VERSION 5.4 ;
NAMESCASESENSITIVE ON ;
BUSBITCHARS "[]" ;
DIVIDERCHAR "/" ;
UNITS
  DATABASE MICRONS 2000 ;
END UNITS
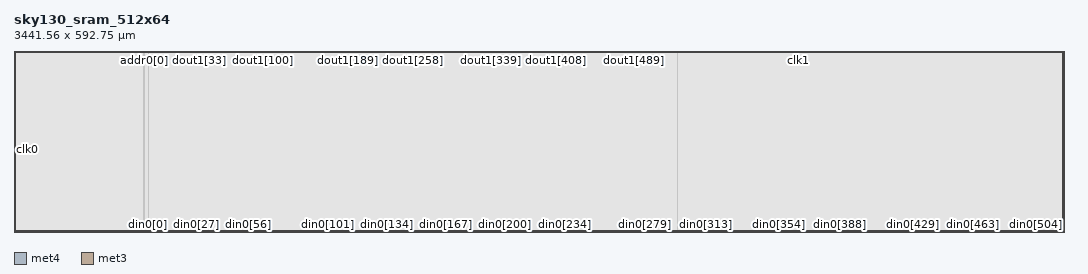
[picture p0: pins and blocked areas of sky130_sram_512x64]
MACRO sky130_sram_512x64
   CLASS BLOCK ;
   SIZE 3441.56 BY 592.75 ;
   SYMMETRY X Y R90 ;
   PIN din0[0]
      DIRECTION INPUT ;
      PORT
         LAYER met4 ;
         RECT  439.9 0.0 440.28 0.38 ;
      END
   END din0[0]
   PIN din0[1]
      DIRECTION INPUT ;
      PORT
         LAYER met4 ;
         RECT  445.74 0.0 446.12 0.38 ;
      END
   END din0[1]
   PIN din0[2]
      DIRECTION INPUT ;
      PORT
         LAYER met4 ;
         RECT  451.58 0.0 451.96 0.38 ;
      END
   END din0[2]
   PIN din0[3]
      DIRECTION INPUT ;
      PORT
         LAYER met4 ;
         RECT  457.42 0.0 457.8 0.38 ;
      END
   END din0[3]
   PIN din0[4]
      DIRECTION INPUT ;
      PORT
         LAYER met4 ;
         RECT  463.26 0.0 463.64 0.38 ;
      END
   END din0[4]
   PIN din0[5]
      DIRECTION INPUT ;
      PORT
         LAYER met4 ;
         RECT  469.1 0.0 469.48 0.38 ;
      END
   END din0[5]
   PIN din0[6]
      DIRECTION INPUT ;
      PORT
         LAYER met4 ;
         RECT  474.94 0.0 475.32 0.38 ;
      END
   END din0[6]
   PIN din0[7]
      DIRECTION INPUT ;
      PORT
         LAYER met4 ;
         RECT  480.78 0.0 481.16 0.38 ;
      END
   END din0[7]
   PIN din0[8]
      DIRECTION INPUT ;
      PORT
         LAYER met4 ;
         RECT  486.62 0.0 487.0 0.38 ;
      END
   END din0[8]
   PIN din0[9]
      DIRECTION INPUT ;
      PORT
         LAYER met4 ;
         RECT  492.46 0.0 492.84 0.38 ;
      END
   END din0[9]
   PIN din0[10]
      DIRECTION INPUT ;
      PORT
         LAYER met4 ;
         RECT  498.3 0.0 498.68 0.38 ;
      END
   END din0[10]
   PIN din0[11]
      DIRECTION INPUT ;
      PORT
         LAYER met4 ;
         RECT  504.14 0.0 504.52 0.38 ;
      END
   END din0[11]
   PIN din0[12]
      DIRECTION INPUT ;
      PORT
         LAYER met4 ;
         RECT  509.98 0.0 510.36 0.38 ;
      END
   END din0[12]
   PIN din0[13]
      DIRECTION INPUT ;
      PORT
         LAYER met4 ;
         RECT  515.82 0.0 516.2 0.38 ;
      END
   END din0[13]
   PIN din0[14]
      DIRECTION INPUT ;
      PORT
         LAYER met4 ;
         RECT  521.66 0.0 522.04 0.38 ;
      END
   END din0[14]
   PIN din0[15]
      DIRECTION INPUT ;
      PORT
         LAYER met4 ;
         RECT  527.5 0.0 527.88 0.38 ;
      END
   END din0[15]
   PIN din0[16]
      DIRECTION INPUT ;
      PORT
         LAYER met4 ;
         RECT  533.34 0.0 533.72 0.38 ;
      END
   END din0[16]
   PIN din0[17]
      DIRECTION INPUT ;
      PORT
         LAYER met4 ;
         RECT  539.18 0.0 539.56 0.38 ;
      END
   END din0[17]
   PIN din0[18]
      DIRECTION INPUT ;
      PORT
         LAYER met4 ;
         RECT  545.02 0.0 545.4 0.38 ;
      END
   END din0[18]
   PIN din0[19]
      DIRECTION INPUT ;
      PORT
         LAYER met4 ;
         RECT  550.86 0.0 551.24 0.38 ;
      END
   END din0[19]
   PIN din0[20]
      DIRECTION INPUT ;
      PORT
         LAYER met4 ;
         RECT  556.7 0.0 557.08 0.38 ;
      END
   END din0[20]
   PIN din0[21]
      DIRECTION INPUT ;
      PORT
         LAYER met4 ;
         RECT  562.54 0.0 562.92 0.38 ;
      END
   END din0[21]
   PIN din0[22]
      DIRECTION INPUT ;
      PORT
         LAYER met4 ;
         RECT  568.38 0.0 568.76 0.38 ;
      END
   END din0[22]
   PIN din0[23]
      DIRECTION INPUT ;
      PORT
         LAYER met4 ;
         RECT  574.22 0.0 574.6 0.38 ;
      END
   END din0[23]
   PIN din0[24]
      DIRECTION INPUT ;
      PORT
         LAYER met4 ;
         RECT  580.06 0.0 580.44 0.38 ;
      END
   END din0[24]
   PIN din0[25]
      DIRECTION INPUT ;
      PORT
         LAYER met4 ;
         RECT  585.9 0.0 586.28 0.38 ;
      END
   END din0[25]
   PIN din0[26]
      DIRECTION INPUT ;
      PORT
         LAYER met4 ;
         RECT  591.74 0.0 592.12 0.38 ;
      END
   END din0[26]
   PIN din0[27]
      DIRECTION INPUT ;
      PORT
         LAYER met4 ;
         RECT  597.58 0.0 597.96 0.38 ;
      END
   END din0[27]
   PIN din0[28]
      DIRECTION INPUT ;
      PORT
         LAYER met4 ;
         RECT  603.42 0.0 603.8 0.38 ;
      END
   END din0[28]
   PIN din0[29]
      DIRECTION INPUT ;
      PORT
         LAYER met4 ;
         RECT  609.26 0.0 609.64 0.38 ;
      END
   END din0[29]
   PIN din0[30]
      DIRECTION INPUT ;
      PORT
         LAYER met4 ;
         RECT  615.1 0.0 615.48 0.38 ;
      END
   END din0[30]
   PIN din0[31]
      DIRECTION INPUT ;
      PORT
         LAYER met4 ;
         RECT  620.94 0.0 621.32 0.38 ;
      END
   END din0[31]
   PIN din0[32]
      DIRECTION INPUT ;
      PORT
         LAYER met4 ;
         RECT  626.78 0.0 627.16 0.38 ;
      END
   END din0[32]
   PIN din0[33]
      DIRECTION INPUT ;
      PORT
         LAYER met4 ;
         RECT  632.62 0.0 633.0 0.38 ;
      END
   END din0[33]
   PIN din0[34]
      DIRECTION INPUT ;
      PORT
         LAYER met4 ;
         RECT  638.46 0.0 638.84 0.38 ;
      END
   END din0[34]
   PIN din0[35]
      DIRECTION INPUT ;
      PORT
         LAYER met4 ;
         RECT  644.3 0.0 644.68 0.38 ;
      END
   END din0[35]
   PIN din0[36]
      DIRECTION INPUT ;
      PORT
         LAYER met4 ;
         RECT  650.14 0.0 650.52 0.38 ;
      END
   END din0[36]
   PIN din0[37]
      DIRECTION INPUT ;
      PORT
         LAYER met4 ;
         RECT  655.98 0.0 656.36 0.38 ;
      END
   END din0[37]
   PIN din0[38]
      DIRECTION INPUT ;
      PORT
         LAYER met4 ;
         RECT  661.82 0.0 662.2 0.38 ;
      END
   END din0[38]
   PIN din0[39]
      DIRECTION INPUT ;
      PORT
         LAYER met4 ;
         RECT  667.66 0.0 668.04 0.38 ;
      END
   END din0[39]
   PIN din0[40]
      DIRECTION INPUT ;
      PORT
         LAYER met4 ;
         RECT  673.5 0.0 673.88 0.38 ;
      END
   END din0[40]
   PIN din0[41]
      DIRECTION INPUT ;
      PORT
         LAYER met4 ;
         RECT  679.34 0.0 679.72 0.38 ;
      END
   END din0[41]
   PIN din0[42]
      DIRECTION INPUT ;
      PORT
         LAYER met4 ;
         RECT  685.18 0.0 685.56 0.38 ;
      END
   END din0[42]
   PIN din0[43]
      DIRECTION INPUT ;
      PORT
         LAYER met4 ;
         RECT  691.02 0.0 691.4 0.38 ;
      END
   END din0[43]
   PIN din0[44]
      DIRECTION INPUT ;
      PORT
         LAYER met4 ;
         RECT  696.86 0.0 697.24 0.38 ;
      END
   END din0[44]
   PIN din0[45]
      DIRECTION INPUT ;
      PORT
         LAYER met4 ;
         RECT  702.7 0.0 703.08 0.38 ;
      END
   END din0[45]
   PIN din0[46]
      DIRECTION INPUT ;
      PORT
         LAYER met4 ;
         RECT  708.54 0.0 708.92 0.38 ;
      END
   END din0[46]
   PIN din0[47]
      DIRECTION INPUT ;
      PORT
         LAYER met4 ;
         RECT  714.38 0.0 714.76 0.38 ;
      END
   END din0[47]
   PIN din0[48]
      DIRECTION INPUT ;
      PORT
         LAYER met4 ;
         RECT  720.22 0.0 720.6 0.38 ;
      END
   END din0[48]
   PIN din0[49]
      DIRECTION INPUT ;
      PORT
         LAYER met4 ;
         RECT  726.06 0.0 726.44 0.38 ;
      END
   END din0[49]
   PIN din0[50]
      DIRECTION INPUT ;
      PORT
         LAYER met4 ;
         RECT  731.9 0.0 732.28 0.38 ;
      END
   END din0[50]
   PIN din0[51]
      DIRECTION INPUT ;
      PORT
         LAYER met4 ;
         RECT  737.74 0.0 738.12 0.38 ;
      END
   END din0[51]
   PIN din0[52]
      DIRECTION INPUT ;
      PORT
         LAYER met4 ;
         RECT  743.58 0.0 743.96 0.38 ;
      END
   END din0[52]
   PIN din0[53]
      DIRECTION INPUT ;
      PORT
         LAYER met4 ;
         RECT  749.42 0.0 749.8 0.38 ;
      END
   END din0[53]
   PIN din0[54]
      DIRECTION INPUT ;
      PORT
         LAYER met4 ;
         RECT  755.26 0.0 755.64 0.38 ;
      END
   END din0[54]
   PIN din0[55]
      DIRECTION INPUT ;
      PORT
         LAYER met4 ;
         RECT  761.1 0.0 761.48 0.38 ;
      END
   END din0[55]
   PIN din0[56]
      DIRECTION INPUT ;
      PORT
         LAYER met4 ;
         RECT  766.94 0.0 767.32 0.38 ;
      END
   END din0[56]
   PIN din0[57]
      DIRECTION INPUT ;
      PORT
         LAYER met4 ;
         RECT  772.78 0.0 773.16 0.38 ;
      END
   END din0[57]
   PIN din0[58]
      DIRECTION INPUT ;
      PORT
         LAYER met4 ;
         RECT  778.62 0.0 779.0 0.38 ;
      END
   END din0[58]
   PIN din0[59]
      DIRECTION INPUT ;
      PORT
         LAYER met4 ;
         RECT  784.46 0.0 784.84 0.38 ;
      END
   END din0[59]
   PIN din0[60]
      DIRECTION INPUT ;
      PORT
         LAYER met4 ;
         RECT  790.3 0.0 790.68 0.38 ;
      END
   END din0[60]
   PIN din0[61]
      DIRECTION INPUT ;
      PORT
         LAYER met4 ;
         RECT  796.14 0.0 796.52 0.38 ;
      END
   END din0[61]
   PIN din0[62]
      DIRECTION INPUT ;
      PORT
         LAYER met4 ;
         RECT  801.98 0.0 802.36 0.38 ;
      END
   END din0[62]
   PIN din0[63]
      DIRECTION INPUT ;
      PORT
         LAYER met4 ;
         RECT  807.82 0.0 808.2 0.38 ;
      END
   END din0[63]
   PIN din0[64]
      DIRECTION INPUT ;
      PORT
         LAYER met4 ;
         RECT  813.66 0.0 814.04 0.38 ;
      END
   END din0[64]
   PIN din0[65]
      DIRECTION INPUT ;
      PORT
         LAYER met4 ;
         RECT  819.5 0.0 819.88 0.38 ;
      END
   END din0[65]
   PIN din0[66]
      DIRECTION INPUT ;
      PORT
         LAYER met4 ;
         RECT  825.34 0.0 825.72 0.38 ;
      END
   END din0[66]
   PIN din0[67]
      DIRECTION INPUT ;
      PORT
         LAYER met4 ;
         RECT  831.18 0.0 831.56 0.38 ;
      END
   END din0[67]
   PIN din0[68]
      DIRECTION INPUT ;
      PORT
         LAYER met4 ;
         RECT  837.02 0.0 837.4 0.38 ;
      END
   END din0[68]
   PIN din0[69]
      DIRECTION INPUT ;
      PORT
         LAYER met4 ;
         RECT  842.86 0.0 843.24 0.38 ;
      END
   END din0[69]
   PIN din0[70]
      DIRECTION INPUT ;
      PORT
         LAYER met4 ;
         RECT  848.7 0.0 849.08 0.38 ;
      END
   END din0[70]
   PIN din0[71]
      DIRECTION INPUT ;
      PORT
         LAYER met4 ;
         RECT  854.54 0.0 854.92 0.38 ;
      END
   END din0[71]
   PIN din0[72]
      DIRECTION INPUT ;
      PORT
         LAYER met4 ;
         RECT  860.38 0.0 860.76 0.38 ;
      END
   END din0[72]
   PIN din0[73]
      DIRECTION INPUT ;
      PORT
         LAYER met4 ;
         RECT  866.22 0.0 866.6 0.38 ;
      END
   END din0[73]
   PIN din0[74]
      DIRECTION INPUT ;
      PORT
         LAYER met4 ;
         RECT  872.06 0.0 872.44 0.38 ;
      END
   END din0[74]
   PIN din0[75]
      DIRECTION INPUT ;
      PORT
         LAYER met4 ;
         RECT  877.9 0.0 878.28 0.38 ;
      END
   END din0[75]
   PIN din0[76]
      DIRECTION INPUT ;
      PORT
         LAYER met4 ;
         RECT  883.74 0.0 884.12 0.38 ;
      END
   END din0[76]
   PIN din0[77]
      DIRECTION INPUT ;
      PORT
         LAYER met4 ;
         RECT  889.58 0.0 889.96 0.38 ;
      END
   END din0[77]
   PIN din0[78]
      DIRECTION INPUT ;
      PORT
         LAYER met4 ;
         RECT  895.42 0.0 895.8 0.38 ;
      END
   END din0[78]
   PIN din0[79]
      DIRECTION INPUT ;
      PORT
         LAYER met4 ;
         RECT  901.26 0.0 901.64 0.38 ;
      END
   END din0[79]
   PIN din0[80]
      DIRECTION INPUT ;
      PORT
         LAYER met4 ;
         RECT  907.1 0.0 907.48 0.38 ;
      END
   END din0[80]
   PIN din0[81]
      DIRECTION INPUT ;
      PORT
         LAYER met4 ;
         RECT  912.94 0.0 913.32 0.38 ;
      END
   END din0[81]
   PIN din0[82]
      DIRECTION INPUT ;
      PORT
         LAYER met4 ;
         RECT  918.78 0.0 919.16 0.38 ;
      END
   END din0[82]
   PIN din0[83]
      DIRECTION INPUT ;
      PORT
         LAYER met4 ;
         RECT  924.62 0.0 925.0 0.38 ;
      END
   END din0[83]
   PIN din0[84]
      DIRECTION INPUT ;
      PORT
         LAYER met4 ;
         RECT  930.46 0.0 930.84 0.38 ;
      END
   END din0[84]
   PIN din0[85]
      DIRECTION INPUT ;
      PORT
         LAYER met4 ;
         RECT  936.3 0.0 936.68 0.38 ;
      END
   END din0[85]
   PIN din0[86]
      DIRECTION INPUT ;
      PORT
         LAYER met4 ;
         RECT  942.14 0.0 942.52 0.38 ;
      END
   END din0[86]
   PIN din0[87]
      DIRECTION INPUT ;
      PORT
         LAYER met4 ;
         RECT  947.98 0.0 948.36 0.38 ;
      END
   END din0[87]
   PIN din0[88]
      DIRECTION INPUT ;
      PORT
         LAYER met4 ;
         RECT  953.82 0.0 954.2 0.38 ;
      END
   END din0[88]
   PIN din0[89]
      DIRECTION INPUT ;
      PORT
         LAYER met4 ;
         RECT  959.66 0.0 960.04 0.38 ;
      END
   END din0[89]
   PIN din0[90]
      DIRECTION INPUT ;
      PORT
         LAYER met4 ;
         RECT  965.5 0.0 965.88 0.38 ;
      END
   END din0[90]
   PIN din0[91]
      DIRECTION INPUT ;
      PORT
         LAYER met4 ;
         RECT  971.34 0.0 971.72 0.38 ;
      END
   END din0[91]
   PIN din0[92]
      DIRECTION INPUT ;
      PORT
         LAYER met4 ;
         RECT  977.18 0.0 977.56 0.38 ;
      END
   END din0[92]
   PIN din0[93]
      DIRECTION INPUT ;
      PORT
         LAYER met4 ;
         RECT  983.02 0.0 983.4 0.38 ;
      END
   END din0[93]
   PIN din0[94]
      DIRECTION INPUT ;
      PORT
         LAYER met4 ;
         RECT  988.86 0.0 989.24 0.38 ;
      END
   END din0[94]
   PIN din0[95]
      DIRECTION INPUT ;
      PORT
         LAYER met4 ;
         RECT  994.7 0.0 995.08 0.38 ;
      END
   END din0[95]
   PIN din0[96]
      DIRECTION INPUT ;
      PORT
         LAYER met4 ;
         RECT  1000.54 0.0 1000.92 0.38 ;
      END
   END din0[96]
   PIN din0[97]
      DIRECTION INPUT ;
      PORT
         LAYER met4 ;
         RECT  1006.38 0.0 1006.76 0.38 ;
      END
   END din0[97]
   PIN din0[98]
      DIRECTION INPUT ;
      PORT
         LAYER met4 ;
         RECT  1012.22 0.0 1012.6 0.38 ;
      END
   END din0[98]
   PIN din0[99]
      DIRECTION INPUT ;
      PORT
         LAYER met4 ;
         RECT  1018.06 0.0 1018.44 0.38 ;
      END
   END din0[99]
   PIN din0[100]
      DIRECTION INPUT ;
      PORT
         LAYER met4 ;
         RECT  1023.9 0.0 1024.28 0.38 ;
      END
   END din0[100]
   PIN din0[101]
      DIRECTION INPUT ;
      PORT
         LAYER met4 ;
         RECT  1029.74 0.0 1030.12 0.38 ;
      END
   END din0[101]
   PIN din0[102]
      DIRECTION INPUT ;
      PORT
         LAYER met4 ;
         RECT  1035.58 0.0 1035.96 0.38 ;
      END
   END din0[102]
   PIN din0[103]
      DIRECTION INPUT ;
      PORT
         LAYER met4 ;
         RECT  1041.42 0.0 1041.8 0.38 ;
      END
   END din0[103]
   PIN din0[104]
      DIRECTION INPUT ;
      PORT
         LAYER met4 ;
         RECT  1047.26 0.0 1047.64 0.38 ;
      END
   END din0[104]
   PIN din0[105]
      DIRECTION INPUT ;
      PORT
         LAYER met4 ;
         RECT  1053.1 0.0 1053.48 0.38 ;
      END
   END din0[105]
   PIN din0[106]
      DIRECTION INPUT ;
      PORT
         LAYER met4 ;
         RECT  1058.94 0.0 1059.32 0.38 ;
      END
   END din0[106]
   PIN din0[107]
      DIRECTION INPUT ;
      PORT
         LAYER met4 ;
         RECT  1064.78 0.0 1065.16 0.38 ;
      END
   END din0[107]
   PIN din0[108]
      DIRECTION INPUT ;
      PORT
         LAYER met4 ;
         RECT  1070.62 0.0 1071.0 0.38 ;
      END
   END din0[108]
   PIN din0[109]
      DIRECTION INPUT ;
      PORT
         LAYER met4 ;
         RECT  1076.46 0.0 1076.84 0.38 ;
      END
   END din0[109]
   PIN din0[110]
      DIRECTION INPUT ;
      PORT
         LAYER met4 ;
         RECT  1082.3 0.0 1082.68 0.38 ;
      END
   END din0[110]
   PIN din0[111]
      DIRECTION INPUT ;
      PORT
         LAYER met4 ;
         RECT  1088.14 0.0 1088.52 0.38 ;
      END
   END din0[111]
   PIN din0[112]
      DIRECTION INPUT ;
      PORT
         LAYER met4 ;
         RECT  1093.98 0.0 1094.36 0.38 ;
      END
   END din0[112]
   PIN din0[113]
      DIRECTION INPUT ;
      PORT
         LAYER met4 ;
         RECT  1099.82 0.0 1100.2 0.38 ;
      END
   END din0[113]
   PIN din0[114]
      DIRECTION INPUT ;
      PORT
         LAYER met4 ;
         RECT  1105.66 0.0 1106.04 0.38 ;
      END
   END din0[114]
   PIN din0[115]
      DIRECTION INPUT ;
      PORT
         LAYER met4 ;
         RECT  1111.5 0.0 1111.88 0.38 ;
      END
   END din0[115]
   PIN din0[116]
      DIRECTION INPUT ;
      PORT
         LAYER met4 ;
         RECT  1117.34 0.0 1117.72 0.38 ;
      END
   END din0[116]
   PIN din0[117]
      DIRECTION INPUT ;
      PORT
         LAYER met4 ;
         RECT  1123.18 0.0 1123.56 0.38 ;
      END
   END din0[117]
   PIN din0[118]
      DIRECTION INPUT ;
      PORT
         LAYER met4 ;
         RECT  1129.02 0.0 1129.4 0.38 ;
      END
   END din0[118]
   PIN din0[119]
      DIRECTION INPUT ;
      PORT
         LAYER met4 ;
         RECT  1134.86 0.0 1135.24 0.38 ;
      END
   END din0[119]
   PIN din0[120]
      DIRECTION INPUT ;
      PORT
         LAYER met4 ;
         RECT  1140.7 0.0 1141.08 0.38 ;
      END
   END din0[120]
   PIN din0[121]
      DIRECTION INPUT ;
      PORT
         LAYER met4 ;
         RECT  1146.54 0.0 1146.92 0.38 ;
      END
   END din0[121]
   PIN din0[122]
      DIRECTION INPUT ;
      PORT
         LAYER met4 ;
         RECT  1152.38 0.0 1152.76 0.38 ;
      END
   END din0[122]
   PIN din0[123]
      DIRECTION INPUT ;
      PORT
         LAYER met4 ;
         RECT  1158.22 0.0 1158.6 0.38 ;
      END
   END din0[123]
   PIN din0[124]
      DIRECTION INPUT ;
      PORT
         LAYER met4 ;
         RECT  1164.06 0.0 1164.44 0.38 ;
      END
   END din0[124]
   PIN din0[125]
      DIRECTION INPUT ;
      PORT
         LAYER met4 ;
         RECT  1169.9 0.0 1170.28 0.38 ;
      END
   END din0[125]
   PIN din0[126]
      DIRECTION INPUT ;
      PORT
         LAYER met4 ;
         RECT  1175.74 0.0 1176.12 0.38 ;
      END
   END din0[126]
   PIN din0[127]
      DIRECTION INPUT ;
      PORT
         LAYER met4 ;
         RECT  1181.58 0.0 1181.96 0.38 ;
      END
   END din0[127]
   PIN din0[128]
      DIRECTION INPUT ;
      PORT
         LAYER met4 ;
         RECT  1187.42 0.0 1187.8 0.38 ;
      END
   END din0[128]
   PIN din0[129]
      DIRECTION INPUT ;
      PORT
         LAYER met4 ;
         RECT  1193.26 0.0 1193.64 0.38 ;
      END
   END din0[129]
   PIN din0[130]
      DIRECTION INPUT ;
      PORT
         LAYER met4 ;
         RECT  1199.1 0.0 1199.48 0.38 ;
      END
   END din0[130]
   PIN din0[131]
      DIRECTION INPUT ;
      PORT
         LAYER met4 ;
         RECT  1204.94 0.0 1205.32 0.38 ;
      END
   END din0[131]
   PIN din0[132]
      DIRECTION INPUT ;
      PORT
         LAYER met4 ;
         RECT  1210.78 0.0 1211.16 0.38 ;
      END
   END din0[132]
   PIN din0[133]
      DIRECTION INPUT ;
      PORT
         LAYER met4 ;
         RECT  1216.62 0.0 1217.0 0.38 ;
      END
   END din0[133]
   PIN din0[134]
      DIRECTION INPUT ;
      PORT
         LAYER met4 ;
         RECT  1222.46 0.0 1222.84 0.38 ;
      END
   END din0[134]
   PIN din0[135]
      DIRECTION INPUT ;
      PORT
         LAYER met4 ;
         RECT  1228.3 0.0 1228.68 0.38 ;
      END
   END din0[135]
   PIN din0[136]
      DIRECTION INPUT ;
      PORT
         LAYER met4 ;
         RECT  1234.14 0.0 1234.52 0.38 ;
      END
   END din0[136]
   PIN din0[137]
      DIRECTION INPUT ;
      PORT
         LAYER met4 ;
         RECT  1239.98 0.0 1240.36 0.38 ;
      END
   END din0[137]
   PIN din0[138]
      DIRECTION INPUT ;
      PORT
         LAYER met4 ;
         RECT  1245.82 0.0 1246.2 0.38 ;
      END
   END din0[138]
   PIN din0[139]
      DIRECTION INPUT ;
      PORT
         LAYER met4 ;
         RECT  1251.66 0.0 1252.04 0.38 ;
      END
   END din0[139]
   PIN din0[140]
      DIRECTION INPUT ;
      PORT
         LAYER met4 ;
         RECT  1257.5 0.0 1257.88 0.38 ;
      END
   END din0[140]
   PIN din0[141]
      DIRECTION INPUT ;
      PORT
         LAYER met4 ;
         RECT  1263.34 0.0 1263.72 0.38 ;
      END
   END din0[141]
   PIN din0[142]
      DIRECTION INPUT ;
      PORT
         LAYER met4 ;
         RECT  1269.18 0.0 1269.56 0.38 ;
      END
   END din0[142]
   PIN din0[143]
      DIRECTION INPUT ;
      PORT
         LAYER met4 ;
         RECT  1275.02 0.0 1275.4 0.38 ;
      END
   END din0[143]
   PIN din0[144]
      DIRECTION INPUT ;
      PORT
         LAYER met4 ;
         RECT  1280.86 0.0 1281.24 0.38 ;
      END
   END din0[144]
   PIN din0[145]
      DIRECTION INPUT ;
      PORT
         LAYER met4 ;
         RECT  1286.7 0.0 1287.08 0.38 ;
      END
   END din0[145]
   PIN din0[146]
      DIRECTION INPUT ;
      PORT
         LAYER met4 ;
         RECT  1292.54 0.0 1292.92 0.38 ;
      END
   END din0[146]
   PIN din0[147]
      DIRECTION INPUT ;
      PORT
         LAYER met4 ;
         RECT  1298.38 0.0 1298.76 0.38 ;
      END
   END din0[147]
   PIN din0[148]
      DIRECTION INPUT ;
      PORT
         LAYER met4 ;
         RECT  1304.22 0.0 1304.6 0.38 ;
      END
   END din0[148]
   PIN din0[149]
      DIRECTION INPUT ;
      PORT
         LAYER met4 ;
         RECT  1310.06 0.0 1310.44 0.38 ;
      END
   END din0[149]
   PIN din0[150]
      DIRECTION INPUT ;
      PORT
         LAYER met4 ;
         RECT  1315.9 0.0 1316.28 0.38 ;
      END
   END din0[150]
   PIN din0[151]
      DIRECTION INPUT ;
      PORT
         LAYER met4 ;
         RECT  1321.74 0.0 1322.12 0.38 ;
      END
   END din0[151]
   PIN din0[152]
      DIRECTION INPUT ;
      PORT
         LAYER met4 ;
         RECT  1327.58 0.0 1327.96 0.38 ;
      END
   END din0[152]
   PIN din0[153]
      DIRECTION INPUT ;
      PORT
         LAYER met4 ;
         RECT  1333.42 0.0 1333.8 0.38 ;
      END
   END din0[153]
   PIN din0[154]
      DIRECTION INPUT ;
      PORT
         LAYER met4 ;
         RECT  1339.26 0.0 1339.64 0.38 ;
      END
   END din0[154]
   PIN din0[155]
      DIRECTION INPUT ;
      PORT
         LAYER met4 ;
         RECT  1345.1 0.0 1345.48 0.38 ;
      END
   END din0[155]
   PIN din0[156]
      DIRECTION INPUT ;
      PORT
         LAYER met4 ;
         RECT  1350.94 0.0 1351.32 0.38 ;
      END
   END din0[156]
   PIN din0[157]
      DIRECTION INPUT ;
      PORT
         LAYER met4 ;
         RECT  1356.78 0.0 1357.16 0.38 ;
      END
   END din0[157]
   PIN din0[158]
      DIRECTION INPUT ;
      PORT
         LAYER met4 ;
         RECT  1362.62 0.0 1363.0 0.38 ;
      END
   END din0[158]
   PIN din0[159]
      DIRECTION INPUT ;
      PORT
         LAYER met4 ;
         RECT  1368.46 0.0 1368.84 0.38 ;
      END
   END din0[159]
   PIN din0[160]
      DIRECTION INPUT ;
      PORT
         LAYER met4 ;
         RECT  1374.3 0.0 1374.68 0.38 ;
      END
   END din0[160]
   PIN din0[161]
      DIRECTION INPUT ;
      PORT
         LAYER met4 ;
         RECT  1380.14 0.0 1380.52 0.38 ;
      END
   END din0[161]
   PIN din0[162]
      DIRECTION INPUT ;
      PORT
         LAYER met4 ;
         RECT  1385.98 0.0 1386.36 0.38 ;
      END
   END din0[162]
   PIN din0[163]
      DIRECTION INPUT ;
      PORT
         LAYER met4 ;
         RECT  1391.82 0.0 1392.2 0.38 ;
      END
   END din0[163]
   PIN din0[164]
      DIRECTION INPUT ;
      PORT
         LAYER met4 ;
         RECT  1397.66 0.0 1398.04 0.38 ;
      END
   END din0[164]
   PIN din0[165]
      DIRECTION INPUT ;
      PORT
         LAYER met4 ;
         RECT  1403.5 0.0 1403.88 0.38 ;
      END
   END din0[165]
   PIN din0[166]
      DIRECTION INPUT ;
      PORT
         LAYER met4 ;
         RECT  1409.34 0.0 1409.72 0.38 ;
      END
   END din0[166]
   PIN din0[167]
      DIRECTION INPUT ;
      PORT
         LAYER met4 ;
         RECT  1415.18 0.0 1415.56 0.38 ;
      END
   END din0[167]
   PIN din0[168]
      DIRECTION INPUT ;
      PORT
         LAYER met4 ;
         RECT  1421.02 0.0 1421.4 0.38 ;
      END
   END din0[168]
   PIN din0[169]
      DIRECTION INPUT ;
      PORT
         LAYER met4 ;
         RECT  1426.86 0.0 1427.24 0.38 ;
      END
   END din0[169]
   PIN din0[170]
      DIRECTION INPUT ;
      PORT
         LAYER met4 ;
         RECT  1432.7 0.0 1433.08 0.38 ;
      END
   END din0[170]
   PIN din0[171]
      DIRECTION INPUT ;
      PORT
         LAYER met4 ;
         RECT  1438.54 0.0 1438.92 0.38 ;
      END
   END din0[171]
   PIN din0[172]
      DIRECTION INPUT ;
      PORT
         LAYER met4 ;
         RECT  1444.38 0.0 1444.76 0.38 ;
      END
   END din0[172]
   PIN din0[173]
      DIRECTION INPUT ;
      PORT
         LAYER met4 ;
         RECT  1450.22 0.0 1450.6 0.38 ;
      END
   END din0[173]
   PIN din0[174]
      DIRECTION INPUT ;
      PORT
         LAYER met4 ;
         RECT  1456.06 0.0 1456.44 0.38 ;
      END
   END din0[174]
   PIN din0[175]
      DIRECTION INPUT ;
      PORT
         LAYER met4 ;
         RECT  1461.9 0.0 1462.28 0.38 ;
      END
   END din0[175]
   PIN din0[176]
      DIRECTION INPUT ;
      PORT
         LAYER met4 ;
         RECT  1467.74 0.0 1468.12 0.38 ;
      END
   END din0[176]
   PIN din0[177]
      DIRECTION INPUT ;
      PORT
         LAYER met4 ;
         RECT  1473.58 0.0 1473.96 0.38 ;
      END
   END din0[177]
   PIN din0[178]
      DIRECTION INPUT ;
      PORT
         LAYER met4 ;
         RECT  1479.42 0.0 1479.8 0.38 ;
      END
   END din0[178]
   PIN din0[179]
      DIRECTION INPUT ;
      PORT
         LAYER met4 ;
         RECT  1485.26 0.0 1485.64 0.38 ;
      END
   END din0[179]
   PIN din0[180]
      DIRECTION INPUT ;
      PORT
         LAYER met4 ;
         RECT  1491.1 0.0 1491.48 0.38 ;
      END
   END din0[180]
   PIN din0[181]
      DIRECTION INPUT ;
      PORT
         LAYER met4 ;
         RECT  1496.94 0.0 1497.32 0.38 ;
      END
   END din0[181]
   PIN din0[182]
      DIRECTION INPUT ;
      PORT
         LAYER met4 ;
         RECT  1502.78 0.0 1503.16 0.38 ;
      END
   END din0[182]
   PIN din0[183]
      DIRECTION INPUT ;
      PORT
         LAYER met4 ;
         RECT  1508.62 0.0 1509.0 0.38 ;
      END
   END din0[183]
   PIN din0[184]
      DIRECTION INPUT ;
      PORT
         LAYER met4 ;
         RECT  1514.46 0.0 1514.84 0.38 ;
      END
   END din0[184]
   PIN din0[185]
      DIRECTION INPUT ;
      PORT
         LAYER met4 ;
         RECT  1520.3 0.0 1520.68 0.38 ;
      END
   END din0[185]
   PIN din0[186]
      DIRECTION INPUT ;
      PORT
         LAYER met4 ;
         RECT  1526.14 0.0 1526.52 0.38 ;
      END
   END din0[186]
   PIN din0[187]
      DIRECTION INPUT ;
      PORT
         LAYER met4 ;
         RECT  1531.98 0.0 1532.36 0.38 ;
      END
   END din0[187]
   PIN din0[188]
      DIRECTION INPUT ;
      PORT
         LAYER met4 ;
         RECT  1537.82 0.0 1538.2 0.38 ;
      END
   END din0[188]
   PIN din0[189]
      DIRECTION INPUT ;
      PORT
         LAYER met4 ;
         RECT  1543.66 0.0 1544.04 0.38 ;
      END
   END din0[189]
   PIN din0[190]
      DIRECTION INPUT ;
      PORT
         LAYER met4 ;
         RECT  1549.5 0.0 1549.88 0.38 ;
      END
   END din0[190]
   PIN din0[191]
      DIRECTION INPUT ;
      PORT
         LAYER met4 ;
         RECT  1555.34 0.0 1555.72 0.38 ;
      END
   END din0[191]
   PIN din0[192]
      DIRECTION INPUT ;
      PORT
         LAYER met4 ;
         RECT  1561.18 0.0 1561.56 0.38 ;
      END
   END din0[192]
   PIN din0[193]
      DIRECTION INPUT ;
      PORT
         LAYER met4 ;
         RECT  1567.02 0.0 1567.4 0.38 ;
      END
   END din0[193]
   PIN din0[194]
      DIRECTION INPUT ;
      PORT
         LAYER met4 ;
         RECT  1572.86 0.0 1573.24 0.38 ;
      END
   END din0[194]
   PIN din0[195]
      DIRECTION INPUT ;
      PORT
         LAYER met4 ;
         RECT  1578.7 0.0 1579.08 0.38 ;
      END
   END din0[195]
   PIN din0[196]
      DIRECTION INPUT ;
      PORT
         LAYER met4 ;
         RECT  1584.54 0.0 1584.92 0.38 ;
      END
   END din0[196]
   PIN din0[197]
      DIRECTION INPUT ;
      PORT
         LAYER met4 ;
         RECT  1590.38 0.0 1590.76 0.38 ;
      END
   END din0[197]
   PIN din0[198]
      DIRECTION INPUT ;
      PORT
         LAYER met4 ;
         RECT  1596.22 0.0 1596.6 0.38 ;
      END
   END din0[198]
   PIN din0[199]
      DIRECTION INPUT ;
      PORT
         LAYER met4 ;
         RECT  1602.06 0.0 1602.44 0.38 ;
      END
   END din0[199]
   PIN din0[200]
      DIRECTION INPUT ;
      PORT
         LAYER met4 ;
         RECT  1607.9 0.0 1608.28 0.38 ;
      END
   END din0[200]
   PIN din0[201]
      DIRECTION INPUT ;
      PORT
         LAYER met4 ;
         RECT  1613.74 0.0 1614.12 0.38 ;
      END
   END din0[201]
   PIN din0[202]
      DIRECTION INPUT ;
      PORT
         LAYER met4 ;
         RECT  1619.58 0.0 1619.96 0.38 ;
      END
   END din0[202]
   PIN din0[203]
      DIRECTION INPUT ;
      PORT
         LAYER met4 ;
         RECT  1625.42 0.0 1625.8 0.38 ;
      END
   END din0[203]
   PIN din0[204]
      DIRECTION INPUT ;
      PORT
         LAYER met4 ;
         RECT  1631.26 0.0 1631.64 0.38 ;
      END
   END din0[204]
   PIN din0[205]
      DIRECTION INPUT ;
      PORT
         LAYER met4 ;
         RECT  1637.1 0.0 1637.48 0.38 ;
      END
   END din0[205]
   PIN din0[206]
      DIRECTION INPUT ;
      PORT
         LAYER met4 ;
         RECT  1642.94 0.0 1643.32 0.38 ;
      END
   END din0[206]
   PIN din0[207]
      DIRECTION INPUT ;
      PORT
         LAYER met4 ;
         RECT  1648.78 0.0 1649.16 0.38 ;
      END
   END din0[207]
   PIN din0[208]
      DIRECTION INPUT ;
      PORT
         LAYER met4 ;
         RECT  1654.62 0.0 1655.0 0.38 ;
      END
   END din0[208]
   PIN din0[209]
      DIRECTION INPUT ;
      PORT
         LAYER met4 ;
         RECT  1660.46 0.0 1660.84 0.38 ;
      END
   END din0[209]
   PIN din0[210]
      DIRECTION INPUT ;
      PORT
         LAYER met4 ;
         RECT  1666.3 0.0 1666.68 0.38 ;
      END
   END din0[210]
   PIN din0[211]
      DIRECTION INPUT ;
      PORT
         LAYER met4 ;
         RECT  1672.14 0.0 1672.52 0.38 ;
      END
   END din0[211]
   PIN din0[212]
      DIRECTION INPUT ;
      PORT
         LAYER met4 ;
         RECT  1677.98 0.0 1678.36 0.38 ;
      END
   END din0[212]
   PIN din0[213]
      DIRECTION INPUT ;
      PORT
         LAYER met4 ;
         RECT  1683.82 0.0 1684.2 0.38 ;
      END
   END din0[213]
   PIN din0[214]
      DIRECTION INPUT ;
      PORT
         LAYER met4 ;
         RECT  1689.66 0.0 1690.04 0.38 ;
      END
   END din0[214]
   PIN din0[215]
      DIRECTION INPUT ;
      PORT
         LAYER met4 ;
         RECT  1695.5 0.0 1695.88 0.38 ;
      END
   END din0[215]
   PIN din0[216]
      DIRECTION INPUT ;
      PORT
         LAYER met4 ;
         RECT  1701.34 0.0 1701.72 0.38 ;
      END
   END din0[216]
   PIN din0[217]
      DIRECTION INPUT ;
      PORT
         LAYER met4 ;
         RECT  1707.18 0.0 1707.56 0.38 ;
      END
   END din0[217]
   PIN din0[218]
      DIRECTION INPUT ;
      PORT
         LAYER met4 ;
         RECT  1713.02 0.0 1713.4 0.38 ;
      END
   END din0[218]
   PIN din0[219]
      DIRECTION INPUT ;
      PORT
         LAYER met4 ;
         RECT  1718.86 0.0 1719.24 0.38 ;
      END
   END din0[219]
   PIN din0[220]
      DIRECTION INPUT ;
      PORT
         LAYER met4 ;
         RECT  1724.7 0.0 1725.08 0.38 ;
      END
   END din0[220]
   PIN din0[221]
      DIRECTION INPUT ;
      PORT
         LAYER met4 ;
         RECT  1730.54 0.0 1730.92 0.38 ;
      END
   END din0[221]
   PIN din0[222]
      DIRECTION INPUT ;
      PORT
         LAYER met4 ;
         RECT  1736.38 0.0 1736.76 0.38 ;
      END
   END din0[222]
   PIN din0[223]
      DIRECTION INPUT ;
      PORT
         LAYER met4 ;
         RECT  1742.22 0.0 1742.6 0.38 ;
      END
   END din0[223]
   PIN din0[224]
      DIRECTION INPUT ;
      PORT
         LAYER met4 ;
         RECT  1748.06 0.0 1748.44 0.38 ;
      END
   END din0[224]
   PIN din0[225]
      DIRECTION INPUT ;
      PORT
         LAYER met4 ;
         RECT  1753.9 0.0 1754.28 0.38 ;
      END
   END din0[225]
   PIN din0[226]
      DIRECTION INPUT ;
      PORT
         LAYER met4 ;
         RECT  1759.74 0.0 1760.12 0.38 ;
      END
   END din0[226]
   PIN din0[227]
      DIRECTION INPUT ;
      PORT
         LAYER met4 ;
         RECT  1765.58 0.0 1765.96 0.38 ;
      END
   END din0[227]
   PIN din0[228]
      DIRECTION INPUT ;
      PORT
         LAYER met4 ;
         RECT  1771.42 0.0 1771.8 0.38 ;
      END
   END din0[228]
   PIN din0[229]
      DIRECTION INPUT ;
      PORT
         LAYER met4 ;
         RECT  1777.26 0.0 1777.64 0.38 ;
      END
   END din0[229]
   PIN din0[230]
      DIRECTION INPUT ;
      PORT
         LAYER met4 ;
         RECT  1783.1 0.0 1783.48 0.38 ;
      END
   END din0[230]
   PIN din0[231]
      DIRECTION INPUT ;
      PORT
         LAYER met4 ;
         RECT  1788.94 0.0 1789.32 0.38 ;
      END
   END din0[231]
   PIN din0[232]
      DIRECTION INPUT ;
      PORT
         LAYER met4 ;
         RECT  1794.78 0.0 1795.16 0.38 ;
      END
   END din0[232]
   PIN din0[233]
      DIRECTION INPUT ;
      PORT
         LAYER met4 ;
         RECT  1800.62 0.0 1801.0 0.38 ;
      END
   END din0[233]
   PIN din0[234]
      DIRECTION INPUT ;
      PORT
         LAYER met4 ;
         RECT  1806.46 0.0 1806.84 0.38 ;
      END
   END din0[234]
   PIN din0[235]
      DIRECTION INPUT ;
      PORT
         LAYER met4 ;
         RECT  1812.3 0.0 1812.68 0.38 ;
      END
   END din0[235]
   PIN din0[236]
      DIRECTION INPUT ;
      PORT
         LAYER met4 ;
         RECT  1818.14 0.0 1818.52 0.38 ;
      END
   END din0[236]
   PIN din0[237]
      DIRECTION INPUT ;
      PORT
         LAYER met4 ;
         RECT  1823.98 0.0 1824.36 0.38 ;
      END
   END din0[237]
   PIN din0[238]
      DIRECTION INPUT ;
      PORT
         LAYER met4 ;
         RECT  1829.82 0.0 1830.2 0.38 ;
      END
   END din0[238]
   PIN din0[239]
      DIRECTION INPUT ;
      PORT
         LAYER met4 ;
         RECT  1835.66 0.0 1836.04 0.38 ;
      END
   END din0[239]
   PIN din0[240]
      DIRECTION INPUT ;
      PORT
         LAYER met4 ;
         RECT  1841.5 0.0 1841.88 0.38 ;
      END
   END din0[240]
   PIN din0[241]
      DIRECTION INPUT ;
      PORT
         LAYER met4 ;
         RECT  1847.34 0.0 1847.72 0.38 ;
      END
   END din0[241]
   PIN din0[242]
      DIRECTION INPUT ;
      PORT
         LAYER met4 ;
         RECT  1853.18 0.0 1853.56 0.38 ;
      END
   END din0[242]
   PIN din0[243]
      DIRECTION INPUT ;
      PORT
         LAYER met4 ;
         RECT  1859.02 0.0 1859.4 0.38 ;
      END
   END din0[243]
   PIN din0[244]
      DIRECTION INPUT ;
      PORT
         LAYER met4 ;
         RECT  1864.86 0.0 1865.24 0.38 ;
      END
   END din0[244]
   PIN din0[245]
      DIRECTION INPUT ;
      PORT
         LAYER met4 ;
         RECT  1870.7 0.0 1871.08 0.38 ;
      END
   END din0[245]
   PIN din0[246]
      DIRECTION INPUT ;
      PORT
         LAYER met4 ;
         RECT  1876.54 0.0 1876.92 0.38 ;
      END
   END din0[246]
   PIN din0[247]
      DIRECTION INPUT ;
      PORT
         LAYER met4 ;
         RECT  1882.38 0.0 1882.76 0.38 ;
      END
   END din0[247]
   PIN din0[248]
      DIRECTION INPUT ;
      PORT
         LAYER met4 ;
         RECT  1888.22 0.0 1888.6 0.38 ;
      END
   END din0[248]
   PIN din0[249]
      DIRECTION INPUT ;
      PORT
         LAYER met4 ;
         RECT  1894.06 0.0 1894.44 0.38 ;
      END
   END din0[249]
   PIN din0[250]
      DIRECTION INPUT ;
      PORT
         LAYER met4 ;
         RECT  1899.9 0.0 1900.28 0.38 ;
      END
   END din0[250]
   PIN din0[251]
      DIRECTION INPUT ;
      PORT
         LAYER met4 ;
         RECT  1905.74 0.0 1906.12 0.38 ;
      END
   END din0[251]
   PIN din0[252]
      DIRECTION INPUT ;
      PORT
         LAYER met4 ;
         RECT  1911.58 0.0 1911.96 0.38 ;
      END
   END din0[252]
   PIN din0[253]
      DIRECTION INPUT ;
      PORT
         LAYER met4 ;
         RECT  1917.42 0.0 1917.8 0.38 ;
      END
   END din0[253]
   PIN din0[254]
      DIRECTION INPUT ;
      PORT
         LAYER met4 ;
         RECT  1923.26 0.0 1923.64 0.38 ;
      END
   END din0[254]
   PIN din0[255]
      DIRECTION INPUT ;
      PORT
         LAYER met4 ;
         RECT  1929.1 0.0 1929.48 0.38 ;
      END
   END din0[255]
   PIN din0[256]
      DIRECTION INPUT ;
      PORT
         LAYER met4 ;
         RECT  1934.94 0.0 1935.32 0.38 ;
      END
   END din0[256]
   PIN din0[257]
      DIRECTION INPUT ;
      PORT
         LAYER met4 ;
         RECT  1940.78 0.0 1941.16 0.38 ;
      END
   END din0[257]
   PIN din0[258]
      DIRECTION INPUT ;
      PORT
         LAYER met4 ;
         RECT  1946.62 0.0 1947.0 0.38 ;
      END
   END din0[258]
   PIN din0[259]
      DIRECTION INPUT ;
      PORT
         LAYER met4 ;
         RECT  1952.46 0.0 1952.84 0.38 ;
      END
   END din0[259]
   PIN din0[260]
      DIRECTION INPUT ;
      PORT
         LAYER met4 ;
         RECT  1958.3 0.0 1958.68 0.38 ;
      END
   END din0[260]
   PIN din0[261]
      DIRECTION INPUT ;
      PORT
         LAYER met4 ;
         RECT  1964.14 0.0 1964.52 0.38 ;
      END
   END din0[261]
   PIN din0[262]
      DIRECTION INPUT ;
      PORT
         LAYER met4 ;
         RECT  1969.98 0.0 1970.36 0.38 ;
      END
   END din0[262]
   PIN din0[263]
      DIRECTION INPUT ;
      PORT
         LAYER met4 ;
         RECT  1975.82 0.0 1976.2 0.38 ;
      END
   END din0[263]
   PIN din0[264]
      DIRECTION INPUT ;
      PORT
         LAYER met4 ;
         RECT  1981.66 0.0 1982.04 0.38 ;
      END
   END din0[264]
   PIN din0[265]
      DIRECTION INPUT ;
      PORT
         LAYER met4 ;
         RECT  1987.5 0.0 1987.88 0.38 ;
      END
   END din0[265]
   PIN din0[266]
      DIRECTION INPUT ;
      PORT
         LAYER met4 ;
         RECT  1993.34 0.0 1993.72 0.38 ;
      END
   END din0[266]
   PIN din0[267]
      DIRECTION INPUT ;
      PORT
         LAYER met4 ;
         RECT  1999.18 0.0 1999.56 0.38 ;
      END
   END din0[267]
   PIN din0[268]
      DIRECTION INPUT ;
      PORT
         LAYER met4 ;
         RECT  2005.02 0.0 2005.4 0.38 ;
      END
   END din0[268]
   PIN din0[269]
      DIRECTION INPUT ;
      PORT
         LAYER met4 ;
         RECT  2010.86 0.0 2011.24 0.38 ;
      END
   END din0[269]
   PIN din0[270]
      DIRECTION INPUT ;
      PORT
         LAYER met4 ;
         RECT  2016.7 0.0 2017.08 0.38 ;
      END
   END din0[270]
   PIN din0[271]
      DIRECTION INPUT ;
      PORT
         LAYER met4 ;
         RECT  2022.54 0.0 2022.92 0.38 ;
      END
   END din0[271]
   PIN din0[272]
      DIRECTION INPUT ;
      PORT
         LAYER met4 ;
         RECT  2028.38 0.0 2028.76 0.38 ;
      END
   END din0[272]
   PIN din0[273]
      DIRECTION INPUT ;
      PORT
         LAYER met4 ;
         RECT  2034.22 0.0 2034.6 0.38 ;
      END
   END din0[273]
   PIN din0[274]
      DIRECTION INPUT ;
      PORT
         LAYER met4 ;
         RECT  2040.06 0.0 2040.44 0.38 ;
      END
   END din0[274]
   PIN din0[275]
      DIRECTION INPUT ;
      PORT
         LAYER met4 ;
         RECT  2045.9 0.0 2046.28 0.38 ;
      END
   END din0[275]
   PIN din0[276]
      DIRECTION INPUT ;
      PORT
         LAYER met4 ;
         RECT  2051.74 0.0 2052.12 0.38 ;
      END
   END din0[276]
   PIN din0[277]
      DIRECTION INPUT ;
      PORT
         LAYER met4 ;
         RECT  2057.58 0.0 2057.96 0.38 ;
      END
   END din0[277]
   PIN din0[278]
      DIRECTION INPUT ;
      PORT
         LAYER met4 ;
         RECT  2063.42 0.0 2063.8 0.38 ;
      END
   END din0[278]
   PIN din0[279]
      DIRECTION INPUT ;
      PORT
         LAYER met4 ;
         RECT  2069.26 0.0 2069.64 0.38 ;
      END
   END din0[279]
   PIN din0[280]
      DIRECTION INPUT ;
      PORT
         LAYER met4 ;
         RECT  2075.1 0.0 2075.48 0.38 ;
      END
   END din0[280]
   PIN din0[281]
      DIRECTION INPUT ;
      PORT
         LAYER met4 ;
         RECT  2080.94 0.0 2081.32 0.38 ;
      END
   END din0[281]
   PIN din0[282]
      DIRECTION INPUT ;
      PORT
         LAYER met4 ;
         RECT  2086.78 0.0 2087.16 0.38 ;
      END
   END din0[282]
   PIN din0[283]
      DIRECTION INPUT ;
      PORT
         LAYER met4 ;
         RECT  2092.62 0.0 2093.0 0.38 ;
      END
   END din0[283]
   PIN din0[284]
      DIRECTION INPUT ;
      PORT
         LAYER met4 ;
         RECT  2098.46 0.0 2098.84 0.38 ;
      END
   END din0[284]
   PIN din0[285]
      DIRECTION INPUT ;
      PORT
         LAYER met4 ;
         RECT  2104.3 0.0 2104.68 0.38 ;
      END
   END din0[285]
   PIN din0[286]
      DIRECTION INPUT ;
      PORT
         LAYER met4 ;
         RECT  2110.14 0.0 2110.52 0.38 ;
      END
   END din0[286]
   PIN din0[287]
      DIRECTION INPUT ;
      PORT
         LAYER met4 ;
         RECT  2115.98 0.0 2116.36 0.38 ;
      END
   END din0[287]
   PIN din0[288]
      DIRECTION INPUT ;
      PORT
         LAYER met4 ;
         RECT  2121.82 0.0 2122.2 0.38 ;
      END
   END din0[288]
   PIN din0[289]
      DIRECTION INPUT ;
      PORT
         LAYER met4 ;
         RECT  2127.66 0.0 2128.04 0.38 ;
      END
   END din0[289]
   PIN din0[290]
      DIRECTION INPUT ;
      PORT
         LAYER met4 ;
         RECT  2133.5 0.0 2133.88 0.38 ;
      END
   END din0[290]
   PIN din0[291]
      DIRECTION INPUT ;
      PORT
         LAYER met4 ;
         RECT  2139.34 0.0 2139.72 0.38 ;
      END
   END din0[291]
   PIN din0[292]
      DIRECTION INPUT ;
      PORT
         LAYER met4 ;
         RECT  2145.18 0.0 2145.56 0.38 ;
      END
   END din0[292]
   PIN din0[293]
      DIRECTION INPUT ;
      PORT
         LAYER met4 ;
         RECT  2151.02 0.0 2151.4 0.38 ;
      END
   END din0[293]
   PIN din0[294]
      DIRECTION INPUT ;
      PORT
         LAYER met4 ;
         RECT  2156.86 0.0 2157.24 0.38 ;
      END
   END din0[294]
   PIN din0[295]
      DIRECTION INPUT ;
      PORT
         LAYER met4 ;
         RECT  2162.7 0.0 2163.08 0.38 ;
      END
   END din0[295]
   PIN din0[296]
      DIRECTION INPUT ;
      PORT
         LAYER met4 ;
         RECT  2168.54 0.0 2168.92 0.38 ;
      END
   END din0[296]
   PIN din0[297]
      DIRECTION INPUT ;
      PORT
         LAYER met4 ;
         RECT  2174.38 0.0 2174.76 0.38 ;
      END
   END din0[297]
   PIN din0[298]
      DIRECTION INPUT ;
      PORT
         LAYER met4 ;
         RECT  2180.22 0.0 2180.6 0.38 ;
      END
   END din0[298]
   PIN din0[299]
      DIRECTION INPUT ;
      PORT
         LAYER met4 ;
         RECT  2186.06 0.0 2186.44 0.38 ;
      END
   END din0[299]
   PIN din0[300]
      DIRECTION INPUT ;
      PORT
         LAYER met4 ;
         RECT  2191.9 0.0 2192.28 0.38 ;
      END
   END din0[300]
   PIN din0[301]
      DIRECTION INPUT ;
      PORT
         LAYER met4 ;
         RECT  2197.74 0.0 2198.12 0.38 ;
      END
   END din0[301]
   PIN din0[302]
      DIRECTION INPUT ;
      PORT
         LAYER met4 ;
         RECT  2203.58 0.0 2203.96 0.38 ;
      END
   END din0[302]
   PIN din0[303]
      DIRECTION INPUT ;
      PORT
         LAYER met4 ;
         RECT  2209.42 0.0 2209.8 0.38 ;
      END
   END din0[303]
   PIN din0[304]
      DIRECTION INPUT ;
      PORT
         LAYER met4 ;
         RECT  2215.26 0.0 2215.64 0.38 ;
      END
   END din0[304]
   PIN din0[305]
      DIRECTION INPUT ;
      PORT
         LAYER met4 ;
         RECT  2221.1 0.0 2221.48 0.38 ;
      END
   END din0[305]
   PIN din0[306]
      DIRECTION INPUT ;
      PORT
         LAYER met4 ;
         RECT  2226.94 0.0 2227.32 0.38 ;
      END
   END din0[306]
   PIN din0[307]
      DIRECTION INPUT ;
      PORT
         LAYER met4 ;
         RECT  2232.78 0.0 2233.16 0.38 ;
      END
   END din0[307]
   PIN din0[308]
      DIRECTION INPUT ;
      PORT
         LAYER met4 ;
         RECT  2238.62 0.0 2239.0 0.38 ;
      END
   END din0[308]
   PIN din0[309]
      DIRECTION INPUT ;
      PORT
         LAYER met4 ;
         RECT  2244.46 0.0 2244.84 0.38 ;
      END
   END din0[309]
   PIN din0[310]
      DIRECTION INPUT ;
      PORT
         LAYER met4 ;
         RECT  2250.3 0.0 2250.68 0.38 ;
      END
   END din0[310]
   PIN din0[311]
      DIRECTION INPUT ;
      PORT
         LAYER met4 ;
         RECT  2256.14 0.0 2256.52 0.38 ;
      END
   END din0[311]
   PIN din0[312]
      DIRECTION INPUT ;
      PORT
         LAYER met4 ;
         RECT  2261.98 0.0 2262.36 0.38 ;
      END
   END din0[312]
   PIN din0[313]
      DIRECTION INPUT ;
      PORT
         LAYER met4 ;
         RECT  2267.82 0.0 2268.2 0.38 ;
      END
   END din0[313]
   PIN din0[314]
      DIRECTION INPUT ;
      PORT
         LAYER met4 ;
         RECT  2273.66 0.0 2274.04 0.38 ;
      END
   END din0[314]
   PIN din0[315]
      DIRECTION INPUT ;
      PORT
         LAYER met4 ;
         RECT  2279.5 0.0 2279.88 0.38 ;
      END
   END din0[315]
   PIN din0[316]
      DIRECTION INPUT ;
      PORT
         LAYER met4 ;
         RECT  2285.34 0.0 2285.72 0.38 ;
      END
   END din0[316]
   PIN din0[317]
      DIRECTION INPUT ;
      PORT
         LAYER met4 ;
         RECT  2291.18 0.0 2291.56 0.38 ;
      END
   END din0[317]
   PIN din0[318]
      DIRECTION INPUT ;
      PORT
         LAYER met4 ;
         RECT  2297.02 0.0 2297.4 0.38 ;
      END
   END din0[318]
   PIN din0[319]
      DIRECTION INPUT ;
      PORT
         LAYER met4 ;
         RECT  2302.86 0.0 2303.24 0.38 ;
      END
   END din0[319]
   PIN din0[320]
      DIRECTION INPUT ;
      PORT
         LAYER met4 ;
         RECT  2308.7 0.0 2309.08 0.38 ;
      END
   END din0[320]
   PIN din0[321]
      DIRECTION INPUT ;
      PORT
         LAYER met4 ;
         RECT  2314.54 0.0 2314.92 0.38 ;
      END
   END din0[321]
   PIN din0[322]
      DIRECTION INPUT ;
      PORT
         LAYER met4 ;
         RECT  2320.38 0.0 2320.76 0.38 ;
      END
   END din0[322]
   PIN din0[323]
      DIRECTION INPUT ;
      PORT
         LAYER met4 ;
         RECT  2326.22 0.0 2326.6 0.38 ;
      END
   END din0[323]
   PIN din0[324]
      DIRECTION INPUT ;
      PORT
         LAYER met4 ;
         RECT  2332.06 0.0 2332.44 0.38 ;
      END
   END din0[324]
   PIN din0[325]
      DIRECTION INPUT ;
      PORT
         LAYER met4 ;
         RECT  2337.9 0.0 2338.28 0.38 ;
      END
   END din0[325]
   PIN din0[326]
      DIRECTION INPUT ;
      PORT
         LAYER met4 ;
         RECT  2343.74 0.0 2344.12 0.38 ;
      END
   END din0[326]
   PIN din0[327]
      DIRECTION INPUT ;
      PORT
         LAYER met4 ;
         RECT  2349.58 0.0 2349.96 0.38 ;
      END
   END din0[327]
   PIN din0[328]
      DIRECTION INPUT ;
      PORT
         LAYER met4 ;
         RECT  2355.42 0.0 2355.8 0.38 ;
      END
   END din0[328]
   PIN din0[329]
      DIRECTION INPUT ;
      PORT
         LAYER met4 ;
         RECT  2361.26 0.0 2361.64 0.38 ;
      END
   END din0[329]
   PIN din0[330]
      DIRECTION INPUT ;
      PORT
         LAYER met4 ;
         RECT  2367.1 0.0 2367.48 0.38 ;
      END
   END din0[330]
   PIN din0[331]
      DIRECTION INPUT ;
      PORT
         LAYER met4 ;
         RECT  2372.94 0.0 2373.32 0.38 ;
      END
   END din0[331]
   PIN din0[332]
      DIRECTION INPUT ;
      PORT
         LAYER met4 ;
         RECT  2378.78 0.0 2379.16 0.38 ;
      END
   END din0[332]
   PIN din0[333]
      DIRECTION INPUT ;
      PORT
         LAYER met4 ;
         RECT  2384.62 0.0 2385.0 0.38 ;
      END
   END din0[333]
   PIN din0[334]
      DIRECTION INPUT ;
      PORT
         LAYER met4 ;
         RECT  2390.46 0.0 2390.84 0.38 ;
      END
   END din0[334]
   PIN din0[335]
      DIRECTION INPUT ;
      PORT
         LAYER met4 ;
         RECT  2396.3 0.0 2396.68 0.38 ;
      END
   END din0[335]
   PIN din0[336]
      DIRECTION INPUT ;
      PORT
         LAYER met4 ;
         RECT  2402.14 0.0 2402.52 0.38 ;
      END
   END din0[336]
   PIN din0[337]
      DIRECTION INPUT ;
      PORT
         LAYER met4 ;
         RECT  2407.98 0.0 2408.36 0.38 ;
      END
   END din0[337]
   PIN din0[338]
      DIRECTION INPUT ;
      PORT
         LAYER met4 ;
         RECT  2413.82 0.0 2414.2 0.38 ;
      END
   END din0[338]
   PIN din0[339]
      DIRECTION INPUT ;
      PORT
         LAYER met4 ;
         RECT  2419.66 0.0 2420.04 0.38 ;
      END
   END din0[339]
   PIN din0[340]
      DIRECTION INPUT ;
      PORT
         LAYER met4 ;
         RECT  2425.5 0.0 2425.88 0.38 ;
      END
   END din0[340]
   PIN din0[341]
      DIRECTION INPUT ;
      PORT
         LAYER met4 ;
         RECT  2431.34 0.0 2431.72 0.38 ;
      END
   END din0[341]
   PIN din0[342]
      DIRECTION INPUT ;
      PORT
         LAYER met4 ;
         RECT  2437.18 0.0 2437.56 0.38 ;
      END
   END din0[342]
   PIN din0[343]
      DIRECTION INPUT ;
      PORT
         LAYER met4 ;
         RECT  2443.02 0.0 2443.4 0.38 ;
      END
   END din0[343]
   PIN din0[344]
      DIRECTION INPUT ;
      PORT
         LAYER met4 ;
         RECT  2448.86 0.0 2449.24 0.38 ;
      END
   END din0[344]
   PIN din0[345]
      DIRECTION INPUT ;
      PORT
         LAYER met4 ;
         RECT  2454.7 0.0 2455.08 0.38 ;
      END
   END din0[345]
   PIN din0[346]
      DIRECTION INPUT ;
      PORT
         LAYER met4 ;
         RECT  2460.54 0.0 2460.92 0.38 ;
      END
   END din0[346]
   PIN din0[347]
      DIRECTION INPUT ;
      PORT
         LAYER met4 ;
         RECT  2466.38 0.0 2466.76 0.38 ;
      END
   END din0[347]
   PIN din0[348]
      DIRECTION INPUT ;
      PORT
         LAYER met4 ;
         RECT  2472.22 0.0 2472.6 0.38 ;
      END
   END din0[348]
   PIN din0[349]
      DIRECTION INPUT ;
      PORT
         LAYER met4 ;
         RECT  2478.06 0.0 2478.44 0.38 ;
      END
   END din0[349]
   PIN din0[350]
      DIRECTION INPUT ;
      PORT
         LAYER met4 ;
         RECT  2483.9 0.0 2484.28 0.38 ;
      END
   END din0[350]
   PIN din0[351]
      DIRECTION INPUT ;
      PORT
         LAYER met4 ;
         RECT  2489.74 0.0 2490.12 0.38 ;
      END
   END din0[351]
   PIN din0[352]
      DIRECTION INPUT ;
      PORT
         LAYER met4 ;
         RECT  2495.58 0.0 2495.96 0.38 ;
      END
   END din0[352]
   PIN din0[353]
      DIRECTION INPUT ;
      PORT
         LAYER met4 ;
         RECT  2501.42 0.0 2501.8 0.38 ;
      END
   END din0[353]
   PIN din0[354]
      DIRECTION INPUT ;
      PORT
         LAYER met4 ;
         RECT  2507.26 0.0 2507.64 0.38 ;
      END
   END din0[354]
   PIN din0[355]
      DIRECTION INPUT ;
      PORT
         LAYER met4 ;
         RECT  2513.1 0.0 2513.48 0.38 ;
      END
   END din0[355]
   PIN din0[356]
      DIRECTION INPUT ;
      PORT
         LAYER met4 ;
         RECT  2518.94 0.0 2519.32 0.38 ;
      END
   END din0[356]
   PIN din0[357]
      DIRECTION INPUT ;
      PORT
         LAYER met4 ;
         RECT  2524.78 0.0 2525.16 0.38 ;
      END
   END din0[357]
   PIN din0[358]
      DIRECTION INPUT ;
      PORT
         LAYER met4 ;
         RECT  2530.62 0.0 2531.0 0.38 ;
      END
   END din0[358]
   PIN din0[359]
      DIRECTION INPUT ;
      PORT
         LAYER met4 ;
         RECT  2536.46 0.0 2536.84 0.38 ;
      END
   END din0[359]
   PIN din0[360]
      DIRECTION INPUT ;
      PORT
         LAYER met4 ;
         RECT  2542.3 0.0 2542.68 0.38 ;
      END
   END din0[360]
   PIN din0[361]
      DIRECTION INPUT ;
      PORT
         LAYER met4 ;
         RECT  2548.14 0.0 2548.52 0.38 ;
      END
   END din0[361]
   PIN din0[362]
      DIRECTION INPUT ;
      PORT
         LAYER met4 ;
         RECT  2553.98 0.0 2554.36 0.38 ;
      END
   END din0[362]
   PIN din0[363]
      DIRECTION INPUT ;
      PORT
         LAYER met4 ;
         RECT  2559.82 0.0 2560.2 0.38 ;
      END
   END din0[363]
   PIN din0[364]
      DIRECTION INPUT ;
      PORT
         LAYER met4 ;
         RECT  2565.66 0.0 2566.04 0.38 ;
      END
   END din0[364]
   PIN din0[365]
      DIRECTION INPUT ;
      PORT
         LAYER met4 ;
         RECT  2571.5 0.0 2571.88 0.38 ;
      END
   END din0[365]
   PIN din0[366]
      DIRECTION INPUT ;
      PORT
         LAYER met4 ;
         RECT  2577.34 0.0 2577.72 0.38 ;
      END
   END din0[366]
   PIN din0[367]
      DIRECTION INPUT ;
      PORT
         LAYER met4 ;
         RECT  2583.18 0.0 2583.56 0.38 ;
      END
   END din0[367]
   PIN din0[368]
      DIRECTION INPUT ;
      PORT
         LAYER met4 ;
         RECT  2589.02 0.0 2589.4 0.38 ;
      END
   END din0[368]
   PIN din0[369]
      DIRECTION INPUT ;
      PORT
         LAYER met4 ;
         RECT  2594.86 0.0 2595.24 0.38 ;
      END
   END din0[369]
   PIN din0[370]
      DIRECTION INPUT ;
      PORT
         LAYER met4 ;
         RECT  2600.7 0.0 2601.08 0.38 ;
      END
   END din0[370]
   PIN din0[371]
      DIRECTION INPUT ;
      PORT
         LAYER met4 ;
         RECT  2606.54 0.0 2606.92 0.38 ;
      END
   END din0[371]
   PIN din0[372]
      DIRECTION INPUT ;
      PORT
         LAYER met4 ;
         RECT  2612.38 0.0 2612.76 0.38 ;
      END
   END din0[372]
   PIN din0[373]
      DIRECTION INPUT ;
      PORT
         LAYER met4 ;
         RECT  2618.22 0.0 2618.6 0.38 ;
      END
   END din0[373]
   PIN din0[374]
      DIRECTION INPUT ;
      PORT
         LAYER met4 ;
         RECT  2624.06 0.0 2624.44 0.38 ;
      END
   END din0[374]
   PIN din0[375]
      DIRECTION INPUT ;
      PORT
         LAYER met4 ;
         RECT  2629.9 0.0 2630.28 0.38 ;
      END
   END din0[375]
   PIN din0[376]
      DIRECTION INPUT ;
      PORT
         LAYER met4 ;
         RECT  2635.74 0.0 2636.12 0.38 ;
      END
   END din0[376]
   PIN din0[377]
      DIRECTION INPUT ;
      PORT
         LAYER met4 ;
         RECT  2641.58 0.0 2641.96 0.38 ;
      END
   END din0[377]
   PIN din0[378]
      DIRECTION INPUT ;
      PORT
         LAYER met4 ;
         RECT  2647.42 0.0 2647.8 0.38 ;
      END
   END din0[378]
   PIN din0[379]
      DIRECTION INPUT ;
      PORT
         LAYER met4 ;
         RECT  2653.26 0.0 2653.64 0.38 ;
      END
   END din0[379]
   PIN din0[380]
      DIRECTION INPUT ;
      PORT
         LAYER met4 ;
         RECT  2659.1 0.0 2659.48 0.38 ;
      END
   END din0[380]
   PIN din0[381]
      DIRECTION INPUT ;
      PORT
         LAYER met4 ;
         RECT  2664.94 0.0 2665.32 0.38 ;
      END
   END din0[381]
   PIN din0[382]
      DIRECTION INPUT ;
      PORT
         LAYER met4 ;
         RECT  2670.78 0.0 2671.16 0.38 ;
      END
   END din0[382]
   PIN din0[383]
      DIRECTION INPUT ;
      PORT
         LAYER met4 ;
         RECT  2676.62 0.0 2677.0 0.38 ;
      END
   END din0[383]
   PIN din0[384]
      DIRECTION INPUT ;
      PORT
         LAYER met4 ;
         RECT  2682.46 0.0 2682.84 0.38 ;
      END
   END din0[384]
   PIN din0[385]
      DIRECTION INPUT ;
      PORT
         LAYER met4 ;
         RECT  2688.3 0.0 2688.68 0.38 ;
      END
   END din0[385]
   PIN din0[386]
      DIRECTION INPUT ;
      PORT
         LAYER met4 ;
         RECT  2694.14 0.0 2694.52 0.38 ;
      END
   END din0[386]
   PIN din0[387]
      DIRECTION INPUT ;
      PORT
         LAYER met4 ;
         RECT  2699.98 0.0 2700.36 0.38 ;
      END
   END din0[387]
   PIN din0[388]
      DIRECTION INPUT ;
      PORT
         LAYER met4 ;
         RECT  2705.82 0.0 2706.2 0.38 ;
      END
   END din0[388]
   PIN din0[389]
      DIRECTION INPUT ;
      PORT
         LAYER met4 ;
         RECT  2711.66 0.0 2712.04 0.38 ;
      END
   END din0[389]
   PIN din0[390]
      DIRECTION INPUT ;
      PORT
         LAYER met4 ;
         RECT  2717.5 0.0 2717.88 0.38 ;
      END
   END din0[390]
   PIN din0[391]
      DIRECTION INPUT ;
      PORT
         LAYER met4 ;
         RECT  2723.34 0.0 2723.72 0.38 ;
      END
   END din0[391]
   PIN din0[392]
      DIRECTION INPUT ;
      PORT
         LAYER met4 ;
         RECT  2729.18 0.0 2729.56 0.38 ;
      END
   END din0[392]
   PIN din0[393]
      DIRECTION INPUT ;
      PORT
         LAYER met4 ;
         RECT  2735.02 0.0 2735.4 0.38 ;
      END
   END din0[393]
   PIN din0[394]
      DIRECTION INPUT ;
      PORT
         LAYER met4 ;
         RECT  2740.86 0.0 2741.24 0.38 ;
      END
   END din0[394]
   PIN din0[395]
      DIRECTION INPUT ;
      PORT
         LAYER met4 ;
         RECT  2746.7 0.0 2747.08 0.38 ;
      END
   END din0[395]
   PIN din0[396]
      DIRECTION INPUT ;
      PORT
         LAYER met4 ;
         RECT  2752.54 0.0 2752.92 0.38 ;
      END
   END din0[396]
   PIN din0[397]
      DIRECTION INPUT ;
      PORT
         LAYER met4 ;
         RECT  2758.38 0.0 2758.76 0.38 ;
      END
   END din0[397]
   PIN din0[398]
      DIRECTION INPUT ;
      PORT
         LAYER met4 ;
         RECT  2764.22 0.0 2764.6 0.38 ;
      END
   END din0[398]
   PIN din0[399]
      DIRECTION INPUT ;
      PORT
         LAYER met4 ;
         RECT  2770.06 0.0 2770.44 0.38 ;
      END
   END din0[399]
   PIN din0[400]
      DIRECTION INPUT ;
      PORT
         LAYER met4 ;
         RECT  2775.9 0.0 2776.28 0.38 ;
      END
   END din0[400]
   PIN din0[401]
      DIRECTION INPUT ;
      PORT
         LAYER met4 ;
         RECT  2781.74 0.0 2782.12 0.38 ;
      END
   END din0[401]
   PIN din0[402]
      DIRECTION INPUT ;
      PORT
         LAYER met4 ;
         RECT  2787.58 0.0 2787.96 0.38 ;
      END
   END din0[402]
   PIN din0[403]
      DIRECTION INPUT ;
      PORT
         LAYER met4 ;
         RECT  2793.42 0.0 2793.8 0.38 ;
      END
   END din0[403]
   PIN din0[404]
      DIRECTION INPUT ;
      PORT
         LAYER met4 ;
         RECT  2799.26 0.0 2799.64 0.38 ;
      END
   END din0[404]
   PIN din0[405]
      DIRECTION INPUT ;
      PORT
         LAYER met4 ;
         RECT  2805.1 0.0 2805.48 0.38 ;
      END
   END din0[405]
   PIN din0[406]
      DIRECTION INPUT ;
      PORT
         LAYER met4 ;
         RECT  2810.94 0.0 2811.32 0.38 ;
      END
   END din0[406]
   PIN din0[407]
      DIRECTION INPUT ;
      PORT
         LAYER met4 ;
         RECT  2816.78 0.0 2817.16 0.38 ;
      END
   END din0[407]
   PIN din0[408]
      DIRECTION INPUT ;
      PORT
         LAYER met4 ;
         RECT  2822.62 0.0 2823.0 0.38 ;
      END
   END din0[408]
   PIN din0[409]
      DIRECTION INPUT ;
      PORT
         LAYER met4 ;
         RECT  2828.46 0.0 2828.84 0.38 ;
      END
   END din0[409]
   PIN din0[410]
      DIRECTION INPUT ;
      PORT
         LAYER met4 ;
         RECT  2834.3 0.0 2834.68 0.38 ;
      END
   END din0[410]
   PIN din0[411]
      DIRECTION INPUT ;
      PORT
         LAYER met4 ;
         RECT  2840.14 0.0 2840.52 0.38 ;
      END
   END din0[411]
   PIN din0[412]
      DIRECTION INPUT ;
      PORT
         LAYER met4 ;
         RECT  2845.98 0.0 2846.36 0.38 ;
      END
   END din0[412]
   PIN din0[413]
      DIRECTION INPUT ;
      PORT
         LAYER met4 ;
         RECT  2851.82 0.0 2852.2 0.38 ;
      END
   END din0[413]
   PIN din0[414]
      DIRECTION INPUT ;
      PORT
         LAYER met4 ;
         RECT  2857.66 0.0 2858.04 0.38 ;
      END
   END din0[414]
   PIN din0[415]
      DIRECTION INPUT ;
      PORT
         LAYER met4 ;
         RECT  2863.5 0.0 2863.88 0.38 ;
      END
   END din0[415]
   PIN din0[416]
      DIRECTION INPUT ;
      PORT
         LAYER met4 ;
         RECT  2869.34 0.0 2869.72 0.38 ;
      END
   END din0[416]
   PIN din0[417]
      DIRECTION INPUT ;
      PORT
         LAYER met4 ;
         RECT  2875.18 0.0 2875.56 0.38 ;
      END
   END din0[417]
   PIN din0[418]
      DIRECTION INPUT ;
      PORT
         LAYER met4 ;
         RECT  2881.02 0.0 2881.4 0.38 ;
      END
   END din0[418]
   PIN din0[419]
      DIRECTION INPUT ;
      PORT
         LAYER met4 ;
         RECT  2886.86 0.0 2887.24 0.38 ;
      END
   END din0[419]
   PIN din0[420]
      DIRECTION INPUT ;
      PORT
         LAYER met4 ;
         RECT  2892.7 0.0 2893.08 0.38 ;
      END
   END din0[420]
   PIN din0[421]
      DIRECTION INPUT ;
      PORT
         LAYER met4 ;
         RECT  2898.54 0.0 2898.92 0.38 ;
      END
   END din0[421]
   PIN din0[422]
      DIRECTION INPUT ;
      PORT
         LAYER met4 ;
         RECT  2904.38 0.0 2904.76 0.38 ;
      END
   END din0[422]
   PIN din0[423]
      DIRECTION INPUT ;
      PORT
         LAYER met4 ;
         RECT  2910.22 0.0 2910.6 0.38 ;
      END
   END din0[423]
   PIN din0[424]
      DIRECTION INPUT ;
      PORT
         LAYER met4 ;
         RECT  2916.06 0.0 2916.44 0.38 ;
      END
   END din0[424]
   PIN din0[425]
      DIRECTION INPUT ;
      PORT
         LAYER met4 ;
         RECT  2921.9 0.0 2922.28 0.38 ;
      END
   END din0[425]
   PIN din0[426]
      DIRECTION INPUT ;
      PORT
         LAYER met4 ;
         RECT  2927.74 0.0 2928.12 0.38 ;
      END
   END din0[426]
   PIN din0[427]
      DIRECTION INPUT ;
      PORT
         LAYER met4 ;
         RECT  2933.58 0.0 2933.96 0.38 ;
      END
   END din0[427]
   PIN din0[428]
      DIRECTION INPUT ;
      PORT
         LAYER met4 ;
         RECT  2939.42 0.0 2939.8 0.38 ;
      END
   END din0[428]
   PIN din0[429]
      DIRECTION INPUT ;
      PORT
         LAYER met4 ;
         RECT  2945.26 0.0 2945.64 0.38 ;
      END
   END din0[429]
   PIN din0[430]
      DIRECTION INPUT ;
      PORT
         LAYER met4 ;
         RECT  2951.1 0.0 2951.48 0.38 ;
      END
   END din0[430]
   PIN din0[431]
      DIRECTION INPUT ;
      PORT
         LAYER met4 ;
         RECT  2956.94 0.0 2957.32 0.38 ;
      END
   END din0[431]
   PIN din0[432]
      DIRECTION INPUT ;
      PORT
         LAYER met4 ;
         RECT  2962.78 0.0 2963.16 0.38 ;
      END
   END din0[432]
   PIN din0[433]
      DIRECTION INPUT ;
      PORT
         LAYER met4 ;
         RECT  2968.62 0.0 2969.0 0.38 ;
      END
   END din0[433]
   PIN din0[434]
      DIRECTION INPUT ;
      PORT
         LAYER met4 ;
         RECT  2974.46 0.0 2974.84 0.38 ;
      END
   END din0[434]
   PIN din0[435]
      DIRECTION INPUT ;
      PORT
         LAYER met4 ;
         RECT  2980.3 0.0 2980.68 0.38 ;
      END
   END din0[435]
   PIN din0[436]
      DIRECTION INPUT ;
      PORT
         LAYER met4 ;
         RECT  2986.14 0.0 2986.52 0.38 ;
      END
   END din0[436]
   PIN din0[437]
      DIRECTION INPUT ;
      PORT
         LAYER met4 ;
         RECT  2991.98 0.0 2992.36 0.38 ;
      END
   END din0[437]
   PIN din0[438]
      DIRECTION INPUT ;
      PORT
         LAYER met4 ;
         RECT  2997.82 0.0 2998.2 0.38 ;
      END
   END din0[438]
   PIN din0[439]
      DIRECTION INPUT ;
      PORT
         LAYER met4 ;
         RECT  3003.66 0.0 3004.04 0.38 ;
      END
   END din0[439]
   PIN din0[440]
      DIRECTION INPUT ;
      PORT
         LAYER met4 ;
         RECT  3009.5 0.0 3009.88 0.38 ;
      END
   END din0[440]
   PIN din0[441]
      DIRECTION INPUT ;
      PORT
         LAYER met4 ;
         RECT  3015.34 0.0 3015.72 0.38 ;
      END
   END din0[441]
   PIN din0[442]
      DIRECTION INPUT ;
      PORT
         LAYER met4 ;
         RECT  3021.18 0.0 3021.56 0.38 ;
      END
   END din0[442]
   PIN din0[443]
      DIRECTION INPUT ;
      PORT
         LAYER met4 ;
         RECT  3027.02 0.0 3027.4 0.38 ;
      END
   END din0[443]
   PIN din0[444]
      DIRECTION INPUT ;
      PORT
         LAYER met4 ;
         RECT  3032.86 0.0 3033.24 0.38 ;
      END
   END din0[444]
   PIN din0[445]
      DIRECTION INPUT ;
      PORT
         LAYER met4 ;
         RECT  3038.7 0.0 3039.08 0.38 ;
      END
   END din0[445]
   PIN din0[446]
      DIRECTION INPUT ;
      PORT
         LAYER met4 ;
         RECT  3044.54 0.0 3044.92 0.38 ;
      END
   END din0[446]
   PIN din0[447]
      DIRECTION INPUT ;
      PORT
         LAYER met4 ;
         RECT  3050.38 0.0 3050.76 0.38 ;
      END
   END din0[447]
   PIN din0[448]
      DIRECTION INPUT ;
      PORT
         LAYER met4 ;
         RECT  3056.22 0.0 3056.6 0.38 ;
      END
   END din0[448]
   PIN din0[449]
      DIRECTION INPUT ;
      PORT
         LAYER met4 ;
         RECT  3062.06 0.0 3062.44 0.38 ;
      END
   END din0[449]
   PIN din0[450]
      DIRECTION INPUT ;
      PORT
         LAYER met4 ;
         RECT  3067.9 0.0 3068.28 0.38 ;
      END
   END din0[450]
   PIN din0[451]
      DIRECTION INPUT ;
      PORT
         LAYER met4 ;
         RECT  3073.74 0.0 3074.12 0.38 ;
      END
   END din0[451]
   PIN din0[452]
      DIRECTION INPUT ;
      PORT
         LAYER met4 ;
         RECT  3079.58 0.0 3079.96 0.38 ;
      END
   END din0[452]
   PIN din0[453]
      DIRECTION INPUT ;
      PORT
         LAYER met4 ;
         RECT  3085.42 0.0 3085.8 0.38 ;
      END
   END din0[453]
   PIN din0[454]
      DIRECTION INPUT ;
      PORT
         LAYER met4 ;
         RECT  3091.26 0.0 3091.64 0.38 ;
      END
   END din0[454]
   PIN din0[455]
      DIRECTION INPUT ;
      PORT
         LAYER met4 ;
         RECT  3097.1 0.0 3097.48 0.38 ;
      END
   END din0[455]
   PIN din0[456]
      DIRECTION INPUT ;
      PORT
         LAYER met4 ;
         RECT  3102.94 0.0 3103.32 0.38 ;
      END
   END din0[456]
   PIN din0[457]
      DIRECTION INPUT ;
      PORT
         LAYER met4 ;
         RECT  3108.78 0.0 3109.16 0.38 ;
      END
   END din0[457]
   PIN din0[458]
      DIRECTION INPUT ;
      PORT
         LAYER met4 ;
         RECT  3114.62 0.0 3115.0 0.38 ;
      END
   END din0[458]
   PIN din0[459]
      DIRECTION INPUT ;
      PORT
         LAYER met4 ;
         RECT  3120.46 0.0 3120.84 0.38 ;
      END
   END din0[459]
   PIN din0[460]
      DIRECTION INPUT ;
      PORT
         LAYER met4 ;
         RECT  3126.3 0.0 3126.68 0.38 ;
      END
   END din0[460]
   PIN din0[461]
      DIRECTION INPUT ;
      PORT
         LAYER met4 ;
         RECT  3132.14 0.0 3132.52 0.38 ;
      END
   END din0[461]
   PIN din0[462]
      DIRECTION INPUT ;
      PORT
         LAYER met4 ;
         RECT  3137.98 0.0 3138.36 0.38 ;
      END
   END din0[462]
   PIN din0[463]
      DIRECTION INPUT ;
      PORT
         LAYER met4 ;
         RECT  3143.82 0.0 3144.2 0.38 ;
      END
   END din0[463]
   PIN din0[464]
      DIRECTION INPUT ;
      PORT
         LAYER met4 ;
         RECT  3149.66 0.0 3150.04 0.38 ;
      END
   END din0[464]
   PIN din0[465]
      DIRECTION INPUT ;
      PORT
         LAYER met4 ;
         RECT  3155.5 0.0 3155.88 0.38 ;
      END
   END din0[465]
   PIN din0[466]
      DIRECTION INPUT ;
      PORT
         LAYER met4 ;
         RECT  3161.34 0.0 3161.72 0.38 ;
      END
   END din0[466]
   PIN din0[467]
      DIRECTION INPUT ;
      PORT
         LAYER met4 ;
         RECT  3167.18 0.0 3167.56 0.38 ;
      END
   END din0[467]
   PIN din0[468]
      DIRECTION INPUT ;
      PORT
         LAYER met4 ;
         RECT  3173.02 0.0 3173.4 0.38 ;
      END
   END din0[468]
   PIN din0[469]
      DIRECTION INPUT ;
      PORT
         LAYER met4 ;
         RECT  3178.86 0.0 3179.24 0.38 ;
      END
   END din0[469]
   PIN din0[470]
      DIRECTION INPUT ;
      PORT
         LAYER met4 ;
         RECT  3184.7 0.0 3185.08 0.38 ;
      END
   END din0[470]
   PIN din0[471]
      DIRECTION INPUT ;
      PORT
         LAYER met4 ;
         RECT  3190.54 0.0 3190.92 0.38 ;
      END
   END din0[471]
   PIN din0[472]
      DIRECTION INPUT ;
      PORT
         LAYER met4 ;
         RECT  3196.38 0.0 3196.76 0.38 ;
      END
   END din0[472]
   PIN din0[473]
      DIRECTION INPUT ;
      PORT
         LAYER met4 ;
         RECT  3202.22 0.0 3202.6 0.38 ;
      END
   END din0[473]
   PIN din0[474]
      DIRECTION INPUT ;
      PORT
         LAYER met4 ;
         RECT  3208.06 0.0 3208.44 0.38 ;
      END
   END din0[474]
   PIN din0[475]
      DIRECTION INPUT ;
      PORT
         LAYER met4 ;
         RECT  3213.9 0.0 3214.28 0.38 ;
      END
   END din0[475]
   PIN din0[476]
      DIRECTION INPUT ;
      PORT
         LAYER met4 ;
         RECT  3219.74 0.0 3220.12 0.38 ;
      END
   END din0[476]
   PIN din0[477]
      DIRECTION INPUT ;
      PORT
         LAYER met4 ;
         RECT  3225.58 0.0 3225.96 0.38 ;
      END
   END din0[477]
   PIN din0[478]
      DIRECTION INPUT ;
      PORT
         LAYER met4 ;
         RECT  3231.42 0.0 3231.8 0.38 ;
      END
   END din0[478]
   PIN din0[479]
      DIRECTION INPUT ;
      PORT
         LAYER met4 ;
         RECT  3237.26 0.0 3237.64 0.38 ;
      END
   END din0[479]
   PIN din0[480]
      DIRECTION INPUT ;
      PORT
         LAYER met4 ;
         RECT  3243.1 0.0 3243.48 0.38 ;
      END
   END din0[480]
   PIN din0[481]
      DIRECTION INPUT ;
      PORT
         LAYER met4 ;
         RECT  3248.94 0.0 3249.32 0.38 ;
      END
   END din0[481]
   PIN din0[482]
      DIRECTION INPUT ;
      PORT
         LAYER met4 ;
         RECT  3254.78 0.0 3255.16 0.38 ;
      END
   END din0[482]
   PIN din0[483]
      DIRECTION INPUT ;
      PORT
         LAYER met4 ;
         RECT  3260.62 0.0 3261.0 0.38 ;
      END
   END din0[483]
   PIN din0[484]
      DIRECTION INPUT ;
      PORT
         LAYER met4 ;
         RECT  3266.46 0.0 3266.84 0.38 ;
      END
   END din0[484]
   PIN din0[485]
      DIRECTION INPUT ;
      PORT
         LAYER met4 ;
         RECT  3272.3 0.0 3272.68 0.38 ;
      END
   END din0[485]
   PIN din0[486]
      DIRECTION INPUT ;
      PORT
         LAYER met4 ;
         RECT  3278.14 0.0 3278.52 0.38 ;
      END
   END din0[486]
   PIN din0[487]
      DIRECTION INPUT ;
      PORT
         LAYER met4 ;
         RECT  3283.98 0.0 3284.36 0.38 ;
      END
   END din0[487]
   PIN din0[488]
      DIRECTION INPUT ;
      PORT
         LAYER met4 ;
         RECT  3289.82 0.0 3290.2 0.38 ;
      END
   END din0[488]
   PIN din0[489]
      DIRECTION INPUT ;
      PORT
         LAYER met4 ;
         RECT  3295.66 0.0 3296.04 0.38 ;
      END
   END din0[489]
   PIN din0[490]
      DIRECTION INPUT ;
      PORT
         LAYER met4 ;
         RECT  3301.5 0.0 3301.88 0.38 ;
      END
   END din0[490]
   PIN din0[491]
      DIRECTION INPUT ;
      PORT
         LAYER met4 ;
         RECT  3307.34 0.0 3307.72 0.38 ;
      END
   END din0[491]
   PIN din0[492]
      DIRECTION INPUT ;
      PORT
         LAYER met4 ;
         RECT  3313.18 0.0 3313.56 0.38 ;
      END
   END din0[492]
   PIN din0[493]
      DIRECTION INPUT ;
      PORT
         LAYER met4 ;
         RECT  3319.02 0.0 3319.4 0.38 ;
      END
   END din0[493]
   PIN din0[494]
      DIRECTION INPUT ;
      PORT
         LAYER met4 ;
         RECT  3324.86 0.0 3325.24 0.38 ;
      END
   END din0[494]
   PIN din0[495]
      DIRECTION INPUT ;
      PORT
         LAYER met4 ;
         RECT  3330.7 0.0 3331.08 0.38 ;
      END
   END din0[495]
   PIN din0[496]
      DIRECTION INPUT ;
      PORT
         LAYER met4 ;
         RECT  3336.54 0.0 3336.92 0.38 ;
      END
   END din0[496]
   PIN din0[497]
      DIRECTION INPUT ;
      PORT
         LAYER met4 ;
         RECT  3342.38 0.0 3342.76 0.38 ;
      END
   END din0[497]
   PIN din0[498]
      DIRECTION INPUT ;
      PORT
         LAYER met4 ;
         RECT  3348.22 0.0 3348.6 0.38 ;
      END
   END din0[498]
   PIN din0[499]
      DIRECTION INPUT ;
      PORT
         LAYER met4 ;
         RECT  3354.06 0.0 3354.44 0.38 ;
      END
   END din0[499]
   PIN din0[500]
      DIRECTION INPUT ;
      PORT
         LAYER met4 ;
         RECT  3359.9 0.0 3360.28 0.38 ;
      END
   END din0[500]
   PIN din0[501]
      DIRECTION INPUT ;
      PORT
         LAYER met4 ;
         RECT  3365.74 0.0 3366.12 0.38 ;
      END
   END din0[501]
   PIN din0[502]
      DIRECTION INPUT ;
      PORT
         LAYER met4 ;
         RECT  3371.58 0.0 3371.96 0.38 ;
      END
   END din0[502]
   PIN din0[503]
      DIRECTION INPUT ;
      PORT
         LAYER met4 ;
         RECT  3377.42 0.0 3377.8 0.38 ;
      END
   END din0[503]
   PIN din0[504]
      DIRECTION INPUT ;
      PORT
         LAYER met4 ;
         RECT  3383.26 0.0 3383.64 0.38 ;
      END
   END din0[504]
   PIN din0[505]
      DIRECTION INPUT ;
      PORT
         LAYER met4 ;
         RECT  3389.1 0.0 3389.48 0.38 ;
      END
   END din0[505]
   PIN din0[506]
      DIRECTION INPUT ;
      PORT
         LAYER met4 ;
         RECT  3394.94 0.0 3395.32 0.38 ;
      END
   END din0[506]
   PIN din0[507]
      DIRECTION INPUT ;
      PORT
         LAYER met4 ;
         RECT  3400.78 0.0 3401.16 0.38 ;
      END
   END din0[507]
   PIN din0[508]
      DIRECTION INPUT ;
      PORT
         LAYER met4 ;
         RECT  3406.62 0.0 3407.0 0.38 ;
      END
   END din0[508]
   PIN din0[509]
      DIRECTION INPUT ;
      PORT
         LAYER met4 ;
         RECT  3412.46 0.0 3412.84 0.38 ;
      END
   END din0[509]
   PIN din0[510]
      DIRECTION INPUT ;
      PORT
         LAYER met4 ;
         RECT  3418.3 0.0 3418.68 0.38 ;
      END
   END din0[510]
   PIN din0[511]
      DIRECTION INPUT ;
      PORT
         LAYER met4 ;
         RECT  3424.14 0.0 3424.52 0.38 ;
      END
   END din0[511]
   PIN addr0[0]
      DIRECTION INPUT ;
      PORT
         LAYER met4 ;
         RECT  425.99 592.37 426.37 592.75 ;
      END
   END addr0[0]
   PIN addr0[1]
      DIRECTION INPUT ;
      PORT
         LAYER met4 ;
         RECT  430.345 592.37 430.725 592.75 ;
      END
   END addr0[1]
   PIN addr0[2]
      DIRECTION INPUT ;
      PORT
         LAYER met4 ;
         RECT  426.68 592.37 427.06 592.75 ;
      END
   END addr0[2]
   PIN addr0[3]
      DIRECTION INPUT ;
      PORT
         LAYER met4 ;
         RECT  429.655 592.37 430.035 592.75 ;
      END
   END addr0[3]
   PIN addr0[4]
      DIRECTION INPUT ;
      PORT
         LAYER met4 ;
         RECT  428.965 592.37 429.345 592.75 ;
      END
   END addr0[4]
   PIN addr0[5]
      DIRECTION INPUT ;
      PORT
         LAYER met4 ;
         RECT  428.22 592.37 428.6 592.75 ;
      END
   END addr0[5]
   PIN addr1[0]
      DIRECTION INPUT ;
      PORT
         LAYER met4 ;
         RECT  2174.54 592.37 2174.92 592.75 ;
      END
   END addr1[0]
   PIN addr1[1]
      DIRECTION INPUT ;
      PORT
         LAYER met4 ;
         RECT  2173.795 592.37 2174.175 592.75 ;
      END
   END addr1[1]
   PIN addr1[2]
      DIRECTION INPUT ;
      PORT
         LAYER met4 ;
         RECT  2173.105 592.37 2173.485 592.75 ;
      END
   END addr1[2]
   PIN addr1[3]
      DIRECTION INPUT ;
      PORT
         LAYER met4 ;
         RECT  2176.08 0.0 2176.46 0.38 ;
      END
   END addr1[3]
   PIN addr1[4]
      DIRECTION INPUT ;
      PORT
         LAYER met4 ;
         RECT  2172.575 0.0 2172.955 0.38 ;
      END
   END addr1[4]
   PIN addr1[5]
      DIRECTION INPUT ;
      PORT
         LAYER met4 ;
         RECT  2174.54 0.0 2174.92 0.38 ;
      END
   END addr1[5]
   PIN csb0
      DIRECTION INPUT ;
      PORT
         LAYER met3 ;
         RECT  0.0 269.185 0.38 269.565 ;
      END
   END csb0
   PIN csb1
      DIRECTION INPUT ;
      PORT
         LAYER met4 ;
         RECT  2589.27 592.37 2589.65 592.75 ;
      END
   END csb1
   PIN clk0
      DIRECTION INPUT ;
      PORT
         LAYER met3 ;
         RECT  0.0 270.675 0.38 271.055 ;
      END
   END clk0
   PIN clk1
      DIRECTION INPUT ;
      PORT
         LAYER met4 ;
         RECT  2572.5 592.37 2572.88 592.75 ;
      END
   END clk1
   PIN dout1[0]
      DIRECTION OUTPUT ;
      PORT
         LAYER met4 ;
         RECT  503.085 592.37 503.465 592.75 ;
      END
   END dout1[0]
   PIN dout1[1]
      DIRECTION OUTPUT ;
      PORT
         LAYER met4 ;
         RECT  508.055 592.37 508.435 592.75 ;
      END
   END dout1[1]
   PIN dout1[2]
      DIRECTION OUTPUT ;
      PORT
         LAYER met4 ;
         RECT  509.325 592.37 509.705 592.75 ;
      END
   END dout1[2]
   PIN dout1[3]
      DIRECTION OUTPUT ;
      PORT
         LAYER met4 ;
         RECT  514.295 592.37 514.675 592.75 ;
      END
   END dout1[3]
   PIN dout1[4]
      DIRECTION OUTPUT ;
      PORT
         LAYER met4 ;
         RECT  515.565 592.37 515.945 592.75 ;
      END
   END dout1[4]
   PIN dout1[5]
      DIRECTION OUTPUT ;
      PORT
         LAYER met4 ;
         RECT  520.535 592.37 520.915 592.75 ;
      END
   END dout1[5]
   PIN dout1[6]
      DIRECTION OUTPUT ;
      PORT
         LAYER met4 ;
         RECT  521.805 592.37 522.185 592.75 ;
      END
   END dout1[6]
   PIN dout1[7]
      DIRECTION OUTPUT ;
      PORT
         LAYER met4 ;
         RECT  526.775 592.37 527.155 592.75 ;
      END
   END dout1[7]
   PIN dout1[8]
      DIRECTION OUTPUT ;
      PORT
         LAYER met4 ;
         RECT  528.045 592.37 528.425 592.75 ;
      END
   END dout1[8]
   PIN dout1[9]
      DIRECTION OUTPUT ;
      PORT
         LAYER met4 ;
         RECT  533.015 592.37 533.395 592.75 ;
      END
   END dout1[9]
   PIN dout1[10]
      DIRECTION OUTPUT ;
      PORT
         LAYER met4 ;
         RECT  534.285 592.37 534.665 592.75 ;
      END
   END dout1[10]
   PIN dout1[11]
      DIRECTION OUTPUT ;
      PORT
         LAYER met4 ;
         RECT  539.255 592.37 539.635 592.75 ;
      END
   END dout1[11]
   PIN dout1[12]
      DIRECTION OUTPUT ;
      PORT
         LAYER met4 ;
         RECT  540.525 592.37 540.905 592.75 ;
      END
   END dout1[12]
   PIN dout1[13]
      DIRECTION OUTPUT ;
      PORT
         LAYER met4 ;
         RECT  545.495 592.37 545.875 592.75 ;
      END
   END dout1[13]
   PIN dout1[14]
      DIRECTION OUTPUT ;
      PORT
         LAYER met4 ;
         RECT  546.765 592.37 547.145 592.75 ;
      END
   END dout1[14]
   PIN dout1[15]
      DIRECTION OUTPUT ;
      PORT
         LAYER met4 ;
         RECT  551.735 592.37 552.115 592.75 ;
      END
   END dout1[15]
   PIN dout1[16]
      DIRECTION OUTPUT ;
      PORT
         LAYER met4 ;
         RECT  553.005 592.37 553.385 592.75 ;
      END
   END dout1[16]
   PIN dout1[17]
      DIRECTION OUTPUT ;
      PORT
         LAYER met4 ;
         RECT  557.975 592.37 558.355 592.75 ;
      END
   END dout1[17]
   PIN dout1[18]
      DIRECTION OUTPUT ;
      PORT
         LAYER met4 ;
         RECT  559.245 592.37 559.625 592.75 ;
      END
   END dout1[18]
   PIN dout1[19]
      DIRECTION OUTPUT ;
      PORT
         LAYER met4 ;
         RECT  564.215 592.37 564.595 592.75 ;
      END
   END dout1[19]
   PIN dout1[20]
      DIRECTION OUTPUT ;
      PORT
         LAYER met4 ;
         RECT  565.485 592.37 565.865 592.75 ;
      END
   END dout1[20]
   PIN dout1[21]
      DIRECTION OUTPUT ;
      PORT
         LAYER met4 ;
         RECT  570.455 592.37 570.835 592.75 ;
      END
   END dout1[21]
   PIN dout1[22]
      DIRECTION OUTPUT ;
      PORT
         LAYER met4 ;
         RECT  571.725 592.37 572.105 592.75 ;
      END
   END dout1[22]
   PIN dout1[23]
      DIRECTION OUTPUT ;
      PORT
         LAYER met4 ;
         RECT  576.695 592.37 577.075 592.75 ;
      END
   END dout1[23]
   PIN dout1[24]
      DIRECTION OUTPUT ;
      PORT
         LAYER met4 ;
         RECT  577.965 592.37 578.345 592.75 ;
      END
   END dout1[24]
   PIN dout1[25]
      DIRECTION OUTPUT ;
      PORT
         LAYER met4 ;
         RECT  582.935 592.37 583.315 592.75 ;
      END
   END dout1[25]
   PIN dout1[26]
      DIRECTION OUTPUT ;
      PORT
         LAYER met4 ;
         RECT  584.205 592.37 584.585 592.75 ;
      END
   END dout1[26]
   PIN dout1[27]
      DIRECTION OUTPUT ;
      PORT
         LAYER met4 ;
         RECT  589.175 592.37 589.555 592.75 ;
      END
   END dout1[27]
   PIN dout1[28]
      DIRECTION OUTPUT ;
      PORT
         LAYER met4 ;
         RECT  590.445 592.37 590.825 592.75 ;
      END
   END dout1[28]
   PIN dout1[29]
      DIRECTION OUTPUT ;
      PORT
         LAYER met4 ;
         RECT  595.415 592.37 595.795 592.75 ;
      END
   END dout1[29]
   PIN dout1[30]
      DIRECTION OUTPUT ;
      PORT
         LAYER met4 ;
         RECT  596.685 592.37 597.065 592.75 ;
      END
   END dout1[30]
   PIN dout1[31]
      DIRECTION OUTPUT ;
      PORT
         LAYER met4 ;
         RECT  601.655 592.37 602.035 592.75 ;
      END
   END dout1[31]
   PIN dout1[32]
      DIRECTION OUTPUT ;
      PORT
         LAYER met4 ;
         RECT  602.925 592.37 603.305 592.75 ;
      END
   END dout1[32]
   PIN dout1[33]
      DIRECTION OUTPUT ;
      PORT
         LAYER met4 ;
         RECT  607.895 592.37 608.275 592.75 ;
      END
   END dout1[33]
   PIN dout1[34]
      DIRECTION OUTPUT ;
      PORT
         LAYER met4 ;
         RECT  609.165 592.37 609.545 592.75 ;
      END
   END dout1[34]
   PIN dout1[35]
      DIRECTION OUTPUT ;
      PORT
         LAYER met4 ;
         RECT  614.135 592.37 614.515 592.75 ;
      END
   END dout1[35]
   PIN dout1[36]
      DIRECTION OUTPUT ;
      PORT
         LAYER met4 ;
         RECT  615.405 592.37 615.785 592.75 ;
      END
   END dout1[36]
   PIN dout1[37]
      DIRECTION OUTPUT ;
      PORT
         LAYER met4 ;
         RECT  620.375 592.37 620.755 592.75 ;
      END
   END dout1[37]
   PIN dout1[38]
      DIRECTION OUTPUT ;
      PORT
         LAYER met4 ;
         RECT  621.645 592.37 622.025 592.75 ;
      END
   END dout1[38]
   PIN dout1[39]
      DIRECTION OUTPUT ;
      PORT
         LAYER met4 ;
         RECT  626.615 592.37 626.995 592.75 ;
      END
   END dout1[39]
   PIN dout1[40]
      DIRECTION OUTPUT ;
      PORT
         LAYER met4 ;
         RECT  627.885 592.37 628.265 592.75 ;
      END
   END dout1[40]
   PIN dout1[41]
      DIRECTION OUTPUT ;
      PORT
         LAYER met4 ;
         RECT  632.855 592.37 633.235 592.75 ;
      END
   END dout1[41]
   PIN dout1[42]
      DIRECTION OUTPUT ;
      PORT
         LAYER met4 ;
         RECT  634.125 592.37 634.505 592.75 ;
      END
   END dout1[42]
   PIN dout1[43]
      DIRECTION OUTPUT ;
      PORT
         LAYER met4 ;
         RECT  639.095 592.37 639.475 592.75 ;
      END
   END dout1[43]
   PIN dout1[44]
      DIRECTION OUTPUT ;
      PORT
         LAYER met4 ;
         RECT  640.365 592.37 640.745 592.75 ;
      END
   END dout1[44]
   PIN dout1[45]
      DIRECTION OUTPUT ;
      PORT
         LAYER met4 ;
         RECT  645.335 592.37 645.715 592.75 ;
      END
   END dout1[45]
   PIN dout1[46]
      DIRECTION OUTPUT ;
      PORT
         LAYER met4 ;
         RECT  646.605 592.37 646.985 592.75 ;
      END
   END dout1[46]
   PIN dout1[47]
      DIRECTION OUTPUT ;
      PORT
         LAYER met4 ;
         RECT  651.575 592.37 651.955 592.75 ;
      END
   END dout1[47]
   PIN dout1[48]
      DIRECTION OUTPUT ;
      PORT
         LAYER met4 ;
         RECT  652.845 592.37 653.225 592.75 ;
      END
   END dout1[48]
   PIN dout1[49]
      DIRECTION OUTPUT ;
      PORT
         LAYER met4 ;
         RECT  657.815 592.37 658.195 592.75 ;
      END
   END dout1[49]
   PIN dout1[50]
      DIRECTION OUTPUT ;
      PORT
         LAYER met4 ;
         RECT  659.085 592.37 659.465 592.75 ;
      END
   END dout1[50]
   PIN dout1[51]
      DIRECTION OUTPUT ;
      PORT
         LAYER met4 ;
         RECT  664.055 592.37 664.435 592.75 ;
      END
   END dout1[51]
   PIN dout1[52]
      DIRECTION OUTPUT ;
      PORT
         LAYER met4 ;
         RECT  665.325 592.37 665.705 592.75 ;
      END
   END dout1[52]
   PIN dout1[53]
      DIRECTION OUTPUT ;
      PORT
         LAYER met4 ;
         RECT  670.295 592.37 670.675 592.75 ;
      END
   END dout1[53]
   PIN dout1[54]
      DIRECTION OUTPUT ;
      PORT
         LAYER met4 ;
         RECT  671.565 592.37 671.945 592.75 ;
      END
   END dout1[54]
   PIN dout1[55]
      DIRECTION OUTPUT ;
      PORT
         LAYER met4 ;
         RECT  676.535 592.37 676.915 592.75 ;
      END
   END dout1[55]
   PIN dout1[56]
      DIRECTION OUTPUT ;
      PORT
         LAYER met4 ;
         RECT  677.805 592.37 678.185 592.75 ;
      END
   END dout1[56]
   PIN dout1[57]
      DIRECTION OUTPUT ;
      PORT
         LAYER met4 ;
         RECT  682.775 592.37 683.155 592.75 ;
      END
   END dout1[57]
   PIN dout1[58]
      DIRECTION OUTPUT ;
      PORT
         LAYER met4 ;
         RECT  684.045 592.37 684.425 592.75 ;
      END
   END dout1[58]
   PIN dout1[59]
      DIRECTION OUTPUT ;
      PORT
         LAYER met4 ;
         RECT  689.015 592.37 689.395 592.75 ;
      END
   END dout1[59]
   PIN dout1[60]
      DIRECTION OUTPUT ;
      PORT
         LAYER met4 ;
         RECT  690.285 592.37 690.665 592.75 ;
      END
   END dout1[60]
   PIN dout1[61]
      DIRECTION OUTPUT ;
      PORT
         LAYER met4 ;
         RECT  695.255 592.37 695.635 592.75 ;
      END
   END dout1[61]
   PIN dout1[62]
      DIRECTION OUTPUT ;
      PORT
         LAYER met4 ;
         RECT  696.525 592.37 696.905 592.75 ;
      END
   END dout1[62]
   PIN dout1[63]
      DIRECTION OUTPUT ;
      PORT
         LAYER met4 ;
         RECT  701.495 592.37 701.875 592.75 ;
      END
   END dout1[63]
   PIN dout1[64]
      DIRECTION OUTPUT ;
      PORT
         LAYER met4 ;
         RECT  702.765 592.37 703.145 592.75 ;
      END
   END dout1[64]
   PIN dout1[65]
      DIRECTION OUTPUT ;
      PORT
         LAYER met4 ;
         RECT  707.735 592.37 708.115 592.75 ;
      END
   END dout1[65]
   PIN dout1[66]
      DIRECTION OUTPUT ;
      PORT
         LAYER met4 ;
         RECT  709.005 592.37 709.385 592.75 ;
      END
   END dout1[66]
   PIN dout1[67]
      DIRECTION OUTPUT ;
      PORT
         LAYER met4 ;
         RECT  713.975 592.37 714.355 592.75 ;
      END
   END dout1[67]
   PIN dout1[68]
      DIRECTION OUTPUT ;
      PORT
         LAYER met4 ;
         RECT  715.245 592.37 715.625 592.75 ;
      END
   END dout1[68]
   PIN dout1[69]
      DIRECTION OUTPUT ;
      PORT
         LAYER met4 ;
         RECT  720.215 592.37 720.595 592.75 ;
      END
   END dout1[69]
   PIN dout1[70]
      DIRECTION OUTPUT ;
      PORT
         LAYER met4 ;
         RECT  721.485 592.37 721.865 592.75 ;
      END
   END dout1[70]
   PIN dout1[71]
      DIRECTION OUTPUT ;
      PORT
         LAYER met4 ;
         RECT  726.455 592.37 726.835 592.75 ;
      END
   END dout1[71]
   PIN dout1[72]
      DIRECTION OUTPUT ;
      PORT
         LAYER met4 ;
         RECT  727.725 592.37 728.105 592.75 ;
      END
   END dout1[72]
   PIN dout1[73]
      DIRECTION OUTPUT ;
      PORT
         LAYER met4 ;
         RECT  732.695 592.37 733.075 592.75 ;
      END
   END dout1[73]
   PIN dout1[74]
      DIRECTION OUTPUT ;
      PORT
         LAYER met4 ;
         RECT  733.965 592.37 734.345 592.75 ;
      END
   END dout1[74]
   PIN dout1[75]
      DIRECTION OUTPUT ;
      PORT
         LAYER met4 ;
         RECT  738.935 592.37 739.315 592.75 ;
      END
   END dout1[75]
   PIN dout1[76]
      DIRECTION OUTPUT ;
      PORT
         LAYER met4 ;
         RECT  740.205 592.37 740.585 592.75 ;
      END
   END dout1[76]
   PIN dout1[77]
      DIRECTION OUTPUT ;
      PORT
         LAYER met4 ;
         RECT  745.175 592.37 745.555 592.75 ;
      END
   END dout1[77]
   PIN dout1[78]
      DIRECTION OUTPUT ;
      PORT
         LAYER met4 ;
         RECT  746.445 592.37 746.825 592.75 ;
      END
   END dout1[78]
   PIN dout1[79]
      DIRECTION OUTPUT ;
      PORT
         LAYER met4 ;
         RECT  751.415 592.37 751.795 592.75 ;
      END
   END dout1[79]
   PIN dout1[80]
      DIRECTION OUTPUT ;
      PORT
         LAYER met4 ;
         RECT  752.685 592.37 753.065 592.75 ;
      END
   END dout1[80]
   PIN dout1[81]
      DIRECTION OUTPUT ;
      PORT
         LAYER met4 ;
         RECT  757.655 592.37 758.035 592.75 ;
      END
   END dout1[81]
   PIN dout1[82]
      DIRECTION OUTPUT ;
      PORT
         LAYER met4 ;
         RECT  758.925 592.37 759.305 592.75 ;
      END
   END dout1[82]
   PIN dout1[83]
      DIRECTION OUTPUT ;
      PORT
         LAYER met4 ;
         RECT  763.895 592.37 764.275 592.75 ;
      END
   END dout1[83]
   PIN dout1[84]
      DIRECTION OUTPUT ;
      PORT
         LAYER met4 ;
         RECT  765.165 592.37 765.545 592.75 ;
      END
   END dout1[84]
   PIN dout1[85]
      DIRECTION OUTPUT ;
      PORT
         LAYER met4 ;
         RECT  770.135 592.37 770.515 592.75 ;
      END
   END dout1[85]
   PIN dout1[86]
      DIRECTION OUTPUT ;
      PORT
         LAYER met4 ;
         RECT  771.405 592.37 771.785 592.75 ;
      END
   END dout1[86]
   PIN dout1[87]
      DIRECTION OUTPUT ;
      PORT
         LAYER met4 ;
         RECT  776.375 592.37 776.755 592.75 ;
      END
   END dout1[87]
   PIN dout1[88]
      DIRECTION OUTPUT ;
      PORT
         LAYER met4 ;
         RECT  777.645 592.37 778.025 592.75 ;
      END
   END dout1[88]
   PIN dout1[89]
      DIRECTION OUTPUT ;
      PORT
         LAYER met4 ;
         RECT  782.615 592.37 782.995 592.75 ;
      END
   END dout1[89]
   PIN dout1[90]
      DIRECTION OUTPUT ;
      PORT
         LAYER met4 ;
         RECT  783.885 592.37 784.265 592.75 ;
      END
   END dout1[90]
   PIN dout1[91]
      DIRECTION OUTPUT ;
      PORT
         LAYER met4 ;
         RECT  788.855 592.37 789.235 592.75 ;
      END
   END dout1[91]
   PIN dout1[92]
      DIRECTION OUTPUT ;
      PORT
         LAYER met4 ;
         RECT  790.125 592.37 790.505 592.75 ;
      END
   END dout1[92]
   PIN dout1[93]
      DIRECTION OUTPUT ;
      PORT
         LAYER met4 ;
         RECT  795.095 592.37 795.475 592.75 ;
      END
   END dout1[93]
   PIN dout1[94]
      DIRECTION OUTPUT ;
      PORT
         LAYER met4 ;
         RECT  796.365 592.37 796.745 592.75 ;
      END
   END dout1[94]
   PIN dout1[95]
      DIRECTION OUTPUT ;
      PORT
         LAYER met4 ;
         RECT  801.335 592.37 801.715 592.75 ;
      END
   END dout1[95]
   PIN dout1[96]
      DIRECTION OUTPUT ;
      PORT
         LAYER met4 ;
         RECT  802.605 592.37 802.985 592.75 ;
      END
   END dout1[96]
   PIN dout1[97]
      DIRECTION OUTPUT ;
      PORT
         LAYER met4 ;
         RECT  807.575 592.37 807.955 592.75 ;
      END
   END dout1[97]
   PIN dout1[98]
      DIRECTION OUTPUT ;
      PORT
         LAYER met4 ;
         RECT  808.845 592.37 809.225 592.75 ;
      END
   END dout1[98]
   PIN dout1[99]
      DIRECTION OUTPUT ;
      PORT
         LAYER met4 ;
         RECT  813.815 592.37 814.195 592.75 ;
      END
   END dout1[99]
   PIN dout1[100]
      DIRECTION OUTPUT ;
      PORT
         LAYER met4 ;
         RECT  815.085 592.37 815.465 592.75 ;
      END
   END dout1[100]
   PIN dout1[101]
      DIRECTION OUTPUT ;
      PORT
         LAYER met4 ;
         RECT  820.055 592.37 820.435 592.75 ;
      END
   END dout1[101]
   PIN dout1[102]
      DIRECTION OUTPUT ;
      PORT
         LAYER met4 ;
         RECT  821.325 592.37 821.705 592.75 ;
      END
   END dout1[102]
   PIN dout1[103]
      DIRECTION OUTPUT ;
      PORT
         LAYER met4 ;
         RECT  826.295 592.37 826.675 592.75 ;
      END
   END dout1[103]
   PIN dout1[104]
      DIRECTION OUTPUT ;
      PORT
         LAYER met4 ;
         RECT  827.565 592.37 827.945 592.75 ;
      END
   END dout1[104]
   PIN dout1[105]
      DIRECTION OUTPUT ;
      PORT
         LAYER met4 ;
         RECT  832.535 592.37 832.915 592.75 ;
      END
   END dout1[105]
   PIN dout1[106]
      DIRECTION OUTPUT ;
      PORT
         LAYER met4 ;
         RECT  833.805 592.37 834.185 592.75 ;
      END
   END dout1[106]
   PIN dout1[107]
      DIRECTION OUTPUT ;
      PORT
         LAYER met4 ;
         RECT  838.775 592.37 839.155 592.75 ;
      END
   END dout1[107]
   PIN dout1[108]
      DIRECTION OUTPUT ;
      PORT
         LAYER met4 ;
         RECT  840.045 592.37 840.425 592.75 ;
      END
   END dout1[108]
   PIN dout1[109]
      DIRECTION OUTPUT ;
      PORT
         LAYER met4 ;
         RECT  845.015 592.37 845.395 592.75 ;
      END
   END dout1[109]
   PIN dout1[110]
      DIRECTION OUTPUT ;
      PORT
         LAYER met4 ;
         RECT  846.285 592.37 846.665 592.75 ;
      END
   END dout1[110]
   PIN dout1[111]
      DIRECTION OUTPUT ;
      PORT
         LAYER met4 ;
         RECT  851.255 592.37 851.635 592.75 ;
      END
   END dout1[111]
   PIN dout1[112]
      DIRECTION OUTPUT ;
      PORT
         LAYER met4 ;
         RECT  852.525 592.37 852.905 592.75 ;
      END
   END dout1[112]
   PIN dout1[113]
      DIRECTION OUTPUT ;
      PORT
         LAYER met4 ;
         RECT  857.495 592.37 857.875 592.75 ;
      END
   END dout1[113]
   PIN dout1[114]
      DIRECTION OUTPUT ;
      PORT
         LAYER met4 ;
         RECT  858.765 592.37 859.145 592.75 ;
      END
   END dout1[114]
   PIN dout1[115]
      DIRECTION OUTPUT ;
      PORT
         LAYER met4 ;
         RECT  863.735 592.37 864.115 592.75 ;
      END
   END dout1[115]
   PIN dout1[116]
      DIRECTION OUTPUT ;
      PORT
         LAYER met4 ;
         RECT  865.005 592.37 865.385 592.75 ;
      END
   END dout1[116]
   PIN dout1[117]
      DIRECTION OUTPUT ;
      PORT
         LAYER met4 ;
         RECT  869.975 592.37 870.355 592.75 ;
      END
   END dout1[117]
   PIN dout1[118]
      DIRECTION OUTPUT ;
      PORT
         LAYER met4 ;
         RECT  871.245 592.37 871.625 592.75 ;
      END
   END dout1[118]
   PIN dout1[119]
      DIRECTION OUTPUT ;
      PORT
         LAYER met4 ;
         RECT  876.215 592.37 876.595 592.75 ;
      END
   END dout1[119]
   PIN dout1[120]
      DIRECTION OUTPUT ;
      PORT
         LAYER met4 ;
         RECT  877.485 592.37 877.865 592.75 ;
      END
   END dout1[120]
   PIN dout1[121]
      DIRECTION OUTPUT ;
      PORT
         LAYER met4 ;
         RECT  882.455 592.37 882.835 592.75 ;
      END
   END dout1[121]
   PIN dout1[122]
      DIRECTION OUTPUT ;
      PORT
         LAYER met4 ;
         RECT  883.725 592.37 884.105 592.75 ;
      END
   END dout1[122]
   PIN dout1[123]
      DIRECTION OUTPUT ;
      PORT
         LAYER met4 ;
         RECT  888.695 592.37 889.075 592.75 ;
      END
   END dout1[123]
   PIN dout1[124]
      DIRECTION OUTPUT ;
      PORT
         LAYER met4 ;
         RECT  889.965 592.37 890.345 592.75 ;
      END
   END dout1[124]
   PIN dout1[125]
      DIRECTION OUTPUT ;
      PORT
         LAYER met4 ;
         RECT  894.935 592.37 895.315 592.75 ;
      END
   END dout1[125]
   PIN dout1[126]
      DIRECTION OUTPUT ;
      PORT
         LAYER met4 ;
         RECT  896.205 592.37 896.585 592.75 ;
      END
   END dout1[126]
   PIN dout1[127]
      DIRECTION OUTPUT ;
      PORT
         LAYER met4 ;
         RECT  901.175 592.37 901.555 592.75 ;
      END
   END dout1[127]
   PIN dout1[128]
      DIRECTION OUTPUT ;
      PORT
         LAYER met4 ;
         RECT  902.445 592.37 902.825 592.75 ;
      END
   END dout1[128]
   PIN dout1[129]
      DIRECTION OUTPUT ;
      PORT
         LAYER met4 ;
         RECT  907.415 592.37 907.795 592.75 ;
      END
   END dout1[129]
   PIN dout1[130]
      DIRECTION OUTPUT ;
      PORT
         LAYER met4 ;
         RECT  908.685 592.37 909.065 592.75 ;
      END
   END dout1[130]
   PIN dout1[131]
      DIRECTION OUTPUT ;
      PORT
         LAYER met4 ;
         RECT  913.655 592.37 914.035 592.75 ;
      END
   END dout1[131]
   PIN dout1[132]
      DIRECTION OUTPUT ;
      PORT
         LAYER met4 ;
         RECT  914.925 592.37 915.305 592.75 ;
      END
   END dout1[132]
   PIN dout1[133]
      DIRECTION OUTPUT ;
      PORT
         LAYER met4 ;
         RECT  919.895 592.37 920.275 592.75 ;
      END
   END dout1[133]
   PIN dout1[134]
      DIRECTION OUTPUT ;
      PORT
         LAYER met4 ;
         RECT  921.165 592.37 921.545 592.75 ;
      END
   END dout1[134]
   PIN dout1[135]
      DIRECTION OUTPUT ;
      PORT
         LAYER met4 ;
         RECT  926.135 592.37 926.515 592.75 ;
      END
   END dout1[135]
   PIN dout1[136]
      DIRECTION OUTPUT ;
      PORT
         LAYER met4 ;
         RECT  927.405 592.37 927.785 592.75 ;
      END
   END dout1[136]
   PIN dout1[137]
      DIRECTION OUTPUT ;
      PORT
         LAYER met4 ;
         RECT  932.375 592.37 932.755 592.75 ;
      END
   END dout1[137]
   PIN dout1[138]
      DIRECTION OUTPUT ;
      PORT
         LAYER met4 ;
         RECT  933.645 592.37 934.025 592.75 ;
      END
   END dout1[138]
   PIN dout1[139]
      DIRECTION OUTPUT ;
      PORT
         LAYER met4 ;
         RECT  938.615 592.37 938.995 592.75 ;
      END
   END dout1[139]
   PIN dout1[140]
      DIRECTION OUTPUT ;
      PORT
         LAYER met4 ;
         RECT  939.885 592.37 940.265 592.75 ;
      END
   END dout1[140]
   PIN dout1[141]
      DIRECTION OUTPUT ;
      PORT
         LAYER met4 ;
         RECT  944.855 592.37 945.235 592.75 ;
      END
   END dout1[141]
   PIN dout1[142]
      DIRECTION OUTPUT ;
      PORT
         LAYER met4 ;
         RECT  946.125 592.37 946.505 592.75 ;
      END
   END dout1[142]
   PIN dout1[143]
      DIRECTION OUTPUT ;
      PORT
         LAYER met4 ;
         RECT  951.095 592.37 951.475 592.75 ;
      END
   END dout1[143]
   PIN dout1[144]
      DIRECTION OUTPUT ;
      PORT
         LAYER met4 ;
         RECT  952.365 592.37 952.745 592.75 ;
      END
   END dout1[144]
   PIN dout1[145]
      DIRECTION OUTPUT ;
      PORT
         LAYER met4 ;
         RECT  957.335 592.37 957.715 592.75 ;
      END
   END dout1[145]
   PIN dout1[146]
      DIRECTION OUTPUT ;
      PORT
         LAYER met4 ;
         RECT  958.605 592.37 958.985 592.75 ;
      END
   END dout1[146]
   PIN dout1[147]
      DIRECTION OUTPUT ;
      PORT
         LAYER met4 ;
         RECT  963.575 592.37 963.955 592.75 ;
      END
   END dout1[147]
   PIN dout1[148]
      DIRECTION OUTPUT ;
      PORT
         LAYER met4 ;
         RECT  964.845 592.37 965.225 592.75 ;
      END
   END dout1[148]
   PIN dout1[149]
      DIRECTION OUTPUT ;
      PORT
         LAYER met4 ;
         RECT  969.815 592.37 970.195 592.75 ;
      END
   END dout1[149]
   PIN dout1[150]
      DIRECTION OUTPUT ;
      PORT
         LAYER met4 ;
         RECT  971.085 592.37 971.465 592.75 ;
      END
   END dout1[150]
   PIN dout1[151]
      DIRECTION OUTPUT ;
      PORT
         LAYER met4 ;
         RECT  976.055 592.37 976.435 592.75 ;
      END
   END dout1[151]
   PIN dout1[152]
      DIRECTION OUTPUT ;
      PORT
         LAYER met4 ;
         RECT  977.325 592.37 977.705 592.75 ;
      END
   END dout1[152]
   PIN dout1[153]
      DIRECTION OUTPUT ;
      PORT
         LAYER met4 ;
         RECT  982.295 592.37 982.675 592.75 ;
      END
   END dout1[153]
   PIN dout1[154]
      DIRECTION OUTPUT ;
      PORT
         LAYER met4 ;
         RECT  983.565 592.37 983.945 592.75 ;
      END
   END dout1[154]
   PIN dout1[155]
      DIRECTION OUTPUT ;
      PORT
         LAYER met4 ;
         RECT  988.535 592.37 988.915 592.75 ;
      END
   END dout1[155]
   PIN dout1[156]
      DIRECTION OUTPUT ;
      PORT
         LAYER met4 ;
         RECT  989.805 592.37 990.185 592.75 ;
      END
   END dout1[156]
   PIN dout1[157]
      DIRECTION OUTPUT ;
      PORT
         LAYER met4 ;
         RECT  994.775 592.37 995.155 592.75 ;
      END
   END dout1[157]
   PIN dout1[158]
      DIRECTION OUTPUT ;
      PORT
         LAYER met4 ;
         RECT  996.045 592.37 996.425 592.75 ;
      END
   END dout1[158]
   PIN dout1[159]
      DIRECTION OUTPUT ;
      PORT
         LAYER met4 ;
         RECT  1001.015 592.37 1001.395 592.75 ;
      END
   END dout1[159]
   PIN dout1[160]
      DIRECTION OUTPUT ;
      PORT
         LAYER met4 ;
         RECT  1002.285 592.37 1002.665 592.75 ;
      END
   END dout1[160]
   PIN dout1[161]
      DIRECTION OUTPUT ;
      PORT
         LAYER met4 ;
         RECT  1007.255 592.37 1007.635 592.75 ;
      END
   END dout1[161]
   PIN dout1[162]
      DIRECTION OUTPUT ;
      PORT
         LAYER met4 ;
         RECT  1008.525 592.37 1008.905 592.75 ;
      END
   END dout1[162]
   PIN dout1[163]
      DIRECTION OUTPUT ;
      PORT
         LAYER met4 ;
         RECT  1013.495 592.37 1013.875 592.75 ;
      END
   END dout1[163]
   PIN dout1[164]
      DIRECTION OUTPUT ;
      PORT
         LAYER met4 ;
         RECT  1014.765 592.37 1015.145 592.75 ;
      END
   END dout1[164]
   PIN dout1[165]
      DIRECTION OUTPUT ;
      PORT
         LAYER met4 ;
         RECT  1019.735 592.37 1020.115 592.75 ;
      END
   END dout1[165]
   PIN dout1[166]
      DIRECTION OUTPUT ;
      PORT
         LAYER met4 ;
         RECT  1021.005 592.37 1021.385 592.75 ;
      END
   END dout1[166]
   PIN dout1[167]
      DIRECTION OUTPUT ;
      PORT
         LAYER met4 ;
         RECT  1025.975 592.37 1026.355 592.75 ;
      END
   END dout1[167]
   PIN dout1[168]
      DIRECTION OUTPUT ;
      PORT
         LAYER met4 ;
         RECT  1027.245 592.37 1027.625 592.75 ;
      END
   END dout1[168]
   PIN dout1[169]
      DIRECTION OUTPUT ;
      PORT
         LAYER met4 ;
         RECT  1032.215 592.37 1032.595 592.75 ;
      END
   END dout1[169]
   PIN dout1[170]
      DIRECTION OUTPUT ;
      PORT
         LAYER met4 ;
         RECT  1033.485 592.37 1033.865 592.75 ;
      END
   END dout1[170]
   PIN dout1[171]
      DIRECTION OUTPUT ;
      PORT
         LAYER met4 ;
         RECT  1038.455 592.37 1038.835 592.75 ;
      END
   END dout1[171]
   PIN dout1[172]
      DIRECTION OUTPUT ;
      PORT
         LAYER met4 ;
         RECT  1039.725 592.37 1040.105 592.75 ;
      END
   END dout1[172]
   PIN dout1[173]
      DIRECTION OUTPUT ;
      PORT
         LAYER met4 ;
         RECT  1044.695 592.37 1045.075 592.75 ;
      END
   END dout1[173]
   PIN dout1[174]
      DIRECTION OUTPUT ;
      PORT
         LAYER met4 ;
         RECT  1045.965 592.37 1046.345 592.75 ;
      END
   END dout1[174]
   PIN dout1[175]
      DIRECTION OUTPUT ;
      PORT
         LAYER met4 ;
         RECT  1050.935 592.37 1051.315 592.75 ;
      END
   END dout1[175]
   PIN dout1[176]
      DIRECTION OUTPUT ;
      PORT
         LAYER met4 ;
         RECT  1052.205 592.37 1052.585 592.75 ;
      END
   END dout1[176]
   PIN dout1[177]
      DIRECTION OUTPUT ;
      PORT
         LAYER met4 ;
         RECT  1057.175 592.37 1057.555 592.75 ;
      END
   END dout1[177]
   PIN dout1[178]
      DIRECTION OUTPUT ;
      PORT
         LAYER met4 ;
         RECT  1058.445 592.37 1058.825 592.75 ;
      END
   END dout1[178]
   PIN dout1[179]
      DIRECTION OUTPUT ;
      PORT
         LAYER met4 ;
         RECT  1063.415 592.37 1063.795 592.75 ;
      END
   END dout1[179]
   PIN dout1[180]
      DIRECTION OUTPUT ;
      PORT
         LAYER met4 ;
         RECT  1064.685 592.37 1065.065 592.75 ;
      END
   END dout1[180]
   PIN dout1[181]
      DIRECTION OUTPUT ;
      PORT
         LAYER met4 ;
         RECT  1069.655 592.37 1070.035 592.75 ;
      END
   END dout1[181]
   PIN dout1[182]
      DIRECTION OUTPUT ;
      PORT
         LAYER met4 ;
         RECT  1070.925 592.37 1071.305 592.75 ;
      END
   END dout1[182]
   PIN dout1[183]
      DIRECTION OUTPUT ;
      PORT
         LAYER met4 ;
         RECT  1075.895 592.37 1076.275 592.75 ;
      END
   END dout1[183]
   PIN dout1[184]
      DIRECTION OUTPUT ;
      PORT
         LAYER met4 ;
         RECT  1077.165 592.37 1077.545 592.75 ;
      END
   END dout1[184]
   PIN dout1[185]
      DIRECTION OUTPUT ;
      PORT
         LAYER met4 ;
         RECT  1082.135 592.37 1082.515 592.75 ;
      END
   END dout1[185]
   PIN dout1[186]
      DIRECTION OUTPUT ;
      PORT
         LAYER met4 ;
         RECT  1083.405 592.37 1083.785 592.75 ;
      END
   END dout1[186]
   PIN dout1[187]
      DIRECTION OUTPUT ;
      PORT
         LAYER met4 ;
         RECT  1088.375 592.37 1088.755 592.75 ;
      END
   END dout1[187]
   PIN dout1[188]
      DIRECTION OUTPUT ;
      PORT
         LAYER met4 ;
         RECT  1089.645 592.37 1090.025 592.75 ;
      END
   END dout1[188]
   PIN dout1[189]
      DIRECTION OUTPUT ;
      PORT
         LAYER met4 ;
         RECT  1094.615 592.37 1094.995 592.75 ;
      END
   END dout1[189]
   PIN dout1[190]
      DIRECTION OUTPUT ;
      PORT
         LAYER met4 ;
         RECT  1095.885 592.37 1096.265 592.75 ;
      END
   END dout1[190]
   PIN dout1[191]
      DIRECTION OUTPUT ;
      PORT
         LAYER met4 ;
         RECT  1100.855 592.37 1101.235 592.75 ;
      END
   END dout1[191]
   PIN dout1[192]
      DIRECTION OUTPUT ;
      PORT
         LAYER met4 ;
         RECT  1102.125 592.37 1102.505 592.75 ;
      END
   END dout1[192]
   PIN dout1[193]
      DIRECTION OUTPUT ;
      PORT
         LAYER met4 ;
         RECT  1107.095 592.37 1107.475 592.75 ;
      END
   END dout1[193]
   PIN dout1[194]
      DIRECTION OUTPUT ;
      PORT
         LAYER met4 ;
         RECT  1108.365 592.37 1108.745 592.75 ;
      END
   END dout1[194]
   PIN dout1[195]
      DIRECTION OUTPUT ;
      PORT
         LAYER met4 ;
         RECT  1113.335 592.37 1113.715 592.75 ;
      END
   END dout1[195]
   PIN dout1[196]
      DIRECTION OUTPUT ;
      PORT
         LAYER met4 ;
         RECT  1114.605 592.37 1114.985 592.75 ;
      END
   END dout1[196]
   PIN dout1[197]
      DIRECTION OUTPUT ;
      PORT
         LAYER met4 ;
         RECT  1119.575 592.37 1119.955 592.75 ;
      END
   END dout1[197]
   PIN dout1[198]
      DIRECTION OUTPUT ;
      PORT
         LAYER met4 ;
         RECT  1120.845 592.37 1121.225 592.75 ;
      END
   END dout1[198]
   PIN dout1[199]
      DIRECTION OUTPUT ;
      PORT
         LAYER met4 ;
         RECT  1125.815 592.37 1126.195 592.75 ;
      END
   END dout1[199]
   PIN dout1[200]
      DIRECTION OUTPUT ;
      PORT
         LAYER met4 ;
         RECT  1127.085 592.37 1127.465 592.75 ;
      END
   END dout1[200]
   PIN dout1[201]
      DIRECTION OUTPUT ;
      PORT
         LAYER met4 ;
         RECT  1132.055 592.37 1132.435 592.75 ;
      END
   END dout1[201]
   PIN dout1[202]
      DIRECTION OUTPUT ;
      PORT
         LAYER met4 ;
         RECT  1133.325 592.37 1133.705 592.75 ;
      END
   END dout1[202]
   PIN dout1[203]
      DIRECTION OUTPUT ;
      PORT
         LAYER met4 ;
         RECT  1138.295 592.37 1138.675 592.75 ;
      END
   END dout1[203]
   PIN dout1[204]
      DIRECTION OUTPUT ;
      PORT
         LAYER met4 ;
         RECT  1139.565 592.37 1139.945 592.75 ;
      END
   END dout1[204]
   PIN dout1[205]
      DIRECTION OUTPUT ;
      PORT
         LAYER met4 ;
         RECT  1144.535 592.37 1144.915 592.75 ;
      END
   END dout1[205]
   PIN dout1[206]
      DIRECTION OUTPUT ;
      PORT
         LAYER met4 ;
         RECT  1145.805 592.37 1146.185 592.75 ;
      END
   END dout1[206]
   PIN dout1[207]
      DIRECTION OUTPUT ;
      PORT
         LAYER met4 ;
         RECT  1150.775 592.37 1151.155 592.75 ;
      END
   END dout1[207]
   PIN dout1[208]
      DIRECTION OUTPUT ;
      PORT
         LAYER met4 ;
         RECT  1152.045 592.37 1152.425 592.75 ;
      END
   END dout1[208]
   PIN dout1[209]
      DIRECTION OUTPUT ;
      PORT
         LAYER met4 ;
         RECT  1157.015 592.37 1157.395 592.75 ;
      END
   END dout1[209]
   PIN dout1[210]
      DIRECTION OUTPUT ;
      PORT
         LAYER met4 ;
         RECT  1158.285 592.37 1158.665 592.75 ;
      END
   END dout1[210]
   PIN dout1[211]
      DIRECTION OUTPUT ;
      PORT
         LAYER met4 ;
         RECT  1163.255 592.37 1163.635 592.75 ;
      END
   END dout1[211]
   PIN dout1[212]
      DIRECTION OUTPUT ;
      PORT
         LAYER met4 ;
         RECT  1164.525 592.37 1164.905 592.75 ;
      END
   END dout1[212]
   PIN dout1[213]
      DIRECTION OUTPUT ;
      PORT
         LAYER met4 ;
         RECT  1169.495 592.37 1169.875 592.75 ;
      END
   END dout1[213]
   PIN dout1[214]
      DIRECTION OUTPUT ;
      PORT
         LAYER met4 ;
         RECT  1170.765 592.37 1171.145 592.75 ;
      END
   END dout1[214]
   PIN dout1[215]
      DIRECTION OUTPUT ;
      PORT
         LAYER met4 ;
         RECT  1175.735 592.37 1176.115 592.75 ;
      END
   END dout1[215]
   PIN dout1[216]
      DIRECTION OUTPUT ;
      PORT
         LAYER met4 ;
         RECT  1177.005 592.37 1177.385 592.75 ;
      END
   END dout1[216]
   PIN dout1[217]
      DIRECTION OUTPUT ;
      PORT
         LAYER met4 ;
         RECT  1181.975 592.37 1182.355 592.75 ;
      END
   END dout1[217]
   PIN dout1[218]
      DIRECTION OUTPUT ;
      PORT
         LAYER met4 ;
         RECT  1183.245 592.37 1183.625 592.75 ;
      END
   END dout1[218]
   PIN dout1[219]
      DIRECTION OUTPUT ;
      PORT
         LAYER met4 ;
         RECT  1188.215 592.37 1188.595 592.75 ;
      END
   END dout1[219]
   PIN dout1[220]
      DIRECTION OUTPUT ;
      PORT
         LAYER met4 ;
         RECT  1189.485 592.37 1189.865 592.75 ;
      END
   END dout1[220]
   PIN dout1[221]
      DIRECTION OUTPUT ;
      PORT
         LAYER met4 ;
         RECT  1194.455 592.37 1194.835 592.75 ;
      END
   END dout1[221]
   PIN dout1[222]
      DIRECTION OUTPUT ;
      PORT
         LAYER met4 ;
         RECT  1195.725 592.37 1196.105 592.75 ;
      END
   END dout1[222]
   PIN dout1[223]
      DIRECTION OUTPUT ;
      PORT
         LAYER met4 ;
         RECT  1200.695 592.37 1201.075 592.75 ;
      END
   END dout1[223]
   PIN dout1[224]
      DIRECTION OUTPUT ;
      PORT
         LAYER met4 ;
         RECT  1201.965 592.37 1202.345 592.75 ;
      END
   END dout1[224]
   PIN dout1[225]
      DIRECTION OUTPUT ;
      PORT
         LAYER met4 ;
         RECT  1206.935 592.37 1207.315 592.75 ;
      END
   END dout1[225]
   PIN dout1[226]
      DIRECTION OUTPUT ;
      PORT
         LAYER met4 ;
         RECT  1208.205 592.37 1208.585 592.75 ;
      END
   END dout1[226]
   PIN dout1[227]
      DIRECTION OUTPUT ;
      PORT
         LAYER met4 ;
         RECT  1213.175 592.37 1213.555 592.75 ;
      END
   END dout1[227]
   PIN dout1[228]
      DIRECTION OUTPUT ;
      PORT
         LAYER met4 ;
         RECT  1214.445 592.37 1214.825 592.75 ;
      END
   END dout1[228]
   PIN dout1[229]
      DIRECTION OUTPUT ;
      PORT
         LAYER met4 ;
         RECT  1219.415 592.37 1219.795 592.75 ;
      END
   END dout1[229]
   PIN dout1[230]
      DIRECTION OUTPUT ;
      PORT
         LAYER met4 ;
         RECT  1220.685 592.37 1221.065 592.75 ;
      END
   END dout1[230]
   PIN dout1[231]
      DIRECTION OUTPUT ;
      PORT
         LAYER met4 ;
         RECT  1225.655 592.37 1226.035 592.75 ;
      END
   END dout1[231]
   PIN dout1[232]
      DIRECTION OUTPUT ;
      PORT
         LAYER met4 ;
         RECT  1226.925 592.37 1227.305 592.75 ;
      END
   END dout1[232]
   PIN dout1[233]
      DIRECTION OUTPUT ;
      PORT
         LAYER met4 ;
         RECT  1231.895 592.37 1232.275 592.75 ;
      END
   END dout1[233]
   PIN dout1[234]
      DIRECTION OUTPUT ;
      PORT
         LAYER met4 ;
         RECT  1233.165 592.37 1233.545 592.75 ;
      END
   END dout1[234]
   PIN dout1[235]
      DIRECTION OUTPUT ;
      PORT
         LAYER met4 ;
         RECT  1238.135 592.37 1238.515 592.75 ;
      END
   END dout1[235]
   PIN dout1[236]
      DIRECTION OUTPUT ;
      PORT
         LAYER met4 ;
         RECT  1239.405 592.37 1239.785 592.75 ;
      END
   END dout1[236]
   PIN dout1[237]
      DIRECTION OUTPUT ;
      PORT
         LAYER met4 ;
         RECT  1244.375 592.37 1244.755 592.75 ;
      END
   END dout1[237]
   PIN dout1[238]
      DIRECTION OUTPUT ;
      PORT
         LAYER met4 ;
         RECT  1245.645 592.37 1246.025 592.75 ;
      END
   END dout1[238]
   PIN dout1[239]
      DIRECTION OUTPUT ;
      PORT
         LAYER met4 ;
         RECT  1250.615 592.37 1250.995 592.75 ;
      END
   END dout1[239]
   PIN dout1[240]
      DIRECTION OUTPUT ;
      PORT
         LAYER met4 ;
         RECT  1251.885 592.37 1252.265 592.75 ;
      END
   END dout1[240]
   PIN dout1[241]
      DIRECTION OUTPUT ;
      PORT
         LAYER met4 ;
         RECT  1256.855 592.37 1257.235 592.75 ;
      END
   END dout1[241]
   PIN dout1[242]
      DIRECTION OUTPUT ;
      PORT
         LAYER met4 ;
         RECT  1258.125 592.37 1258.505 592.75 ;
      END
   END dout1[242]
   PIN dout1[243]
      DIRECTION OUTPUT ;
      PORT
         LAYER met4 ;
         RECT  1263.095 592.37 1263.475 592.75 ;
      END
   END dout1[243]
   PIN dout1[244]
      DIRECTION OUTPUT ;
      PORT
         LAYER met4 ;
         RECT  1264.365 592.37 1264.745 592.75 ;
      END
   END dout1[244]
   PIN dout1[245]
      DIRECTION OUTPUT ;
      PORT
         LAYER met4 ;
         RECT  1269.335 592.37 1269.715 592.75 ;
      END
   END dout1[245]
   PIN dout1[246]
      DIRECTION OUTPUT ;
      PORT
         LAYER met4 ;
         RECT  1270.605 592.37 1270.985 592.75 ;
      END
   END dout1[246]
   PIN dout1[247]
      DIRECTION OUTPUT ;
      PORT
         LAYER met4 ;
         RECT  1275.575 592.37 1275.955 592.75 ;
      END
   END dout1[247]
   PIN dout1[248]
      DIRECTION OUTPUT ;
      PORT
         LAYER met4 ;
         RECT  1276.845 592.37 1277.225 592.75 ;
      END
   END dout1[248]
   PIN dout1[249]
      DIRECTION OUTPUT ;
      PORT
         LAYER met4 ;
         RECT  1281.815 592.37 1282.195 592.75 ;
      END
   END dout1[249]
   PIN dout1[250]
      DIRECTION OUTPUT ;
      PORT
         LAYER met4 ;
         RECT  1283.085 592.37 1283.465 592.75 ;
      END
   END dout1[250]
   PIN dout1[251]
      DIRECTION OUTPUT ;
      PORT
         LAYER met4 ;
         RECT  1288.055 592.37 1288.435 592.75 ;
      END
   END dout1[251]
   PIN dout1[252]
      DIRECTION OUTPUT ;
      PORT
         LAYER met4 ;
         RECT  1289.325 592.37 1289.705 592.75 ;
      END
   END dout1[252]
   PIN dout1[253]
      DIRECTION OUTPUT ;
      PORT
         LAYER met4 ;
         RECT  1294.295 592.37 1294.675 592.75 ;
      END
   END dout1[253]
   PIN dout1[254]
      DIRECTION OUTPUT ;
      PORT
         LAYER met4 ;
         RECT  1295.565 592.37 1295.945 592.75 ;
      END
   END dout1[254]
   PIN dout1[255]
      DIRECTION OUTPUT ;
      PORT
         LAYER met4 ;
         RECT  1300.535 592.37 1300.915 592.75 ;
      END
   END dout1[255]
   PIN dout1[256]
      DIRECTION OUTPUT ;
      PORT
         LAYER met4 ;
         RECT  1301.805 592.37 1302.185 592.75 ;
      END
   END dout1[256]
   PIN dout1[257]
      DIRECTION OUTPUT ;
      PORT
         LAYER met4 ;
         RECT  1306.775 592.37 1307.155 592.75 ;
      END
   END dout1[257]
   PIN dout1[258]
      DIRECTION OUTPUT ;
      PORT
         LAYER met4 ;
         RECT  1308.045 592.37 1308.425 592.75 ;
      END
   END dout1[258]
   PIN dout1[259]
      DIRECTION OUTPUT ;
      PORT
         LAYER met4 ;
         RECT  1313.015 592.37 1313.395 592.75 ;
      END
   END dout1[259]
   PIN dout1[260]
      DIRECTION OUTPUT ;
      PORT
         LAYER met4 ;
         RECT  1314.285 592.37 1314.665 592.75 ;
      END
   END dout1[260]
   PIN dout1[261]
      DIRECTION OUTPUT ;
      PORT
         LAYER met4 ;
         RECT  1319.255 592.37 1319.635 592.75 ;
      END
   END dout1[261]
   PIN dout1[262]
      DIRECTION OUTPUT ;
      PORT
         LAYER met4 ;
         RECT  1320.525 592.37 1320.905 592.75 ;
      END
   END dout1[262]
   PIN dout1[263]
      DIRECTION OUTPUT ;
      PORT
         LAYER met4 ;
         RECT  1325.495 592.37 1325.875 592.75 ;
      END
   END dout1[263]
   PIN dout1[264]
      DIRECTION OUTPUT ;
      PORT
         LAYER met4 ;
         RECT  1326.765 592.37 1327.145 592.75 ;
      END
   END dout1[264]
   PIN dout1[265]
      DIRECTION OUTPUT ;
      PORT
         LAYER met4 ;
         RECT  1331.735 592.37 1332.115 592.75 ;
      END
   END dout1[265]
   PIN dout1[266]
      DIRECTION OUTPUT ;
      PORT
         LAYER met4 ;
         RECT  1333.005 592.37 1333.385 592.75 ;
      END
   END dout1[266]
   PIN dout1[267]
      DIRECTION OUTPUT ;
      PORT
         LAYER met4 ;
         RECT  1337.975 592.37 1338.355 592.75 ;
      END
   END dout1[267]
   PIN dout1[268]
      DIRECTION OUTPUT ;
      PORT
         LAYER met4 ;
         RECT  1339.245 592.37 1339.625 592.75 ;
      END
   END dout1[268]
   PIN dout1[269]
      DIRECTION OUTPUT ;
      PORT
         LAYER met4 ;
         RECT  1344.215 592.37 1344.595 592.75 ;
      END
   END dout1[269]
   PIN dout1[270]
      DIRECTION OUTPUT ;
      PORT
         LAYER met4 ;
         RECT  1345.485 592.37 1345.865 592.75 ;
      END
   END dout1[270]
   PIN dout1[271]
      DIRECTION OUTPUT ;
      PORT
         LAYER met4 ;
         RECT  1350.455 592.37 1350.835 592.75 ;
      END
   END dout1[271]
   PIN dout1[272]
      DIRECTION OUTPUT ;
      PORT
         LAYER met4 ;
         RECT  1351.725 592.37 1352.105 592.75 ;
      END
   END dout1[272]
   PIN dout1[273]
      DIRECTION OUTPUT ;
      PORT
         LAYER met4 ;
         RECT  1356.695 592.37 1357.075 592.75 ;
      END
   END dout1[273]
   PIN dout1[274]
      DIRECTION OUTPUT ;
      PORT
         LAYER met4 ;
         RECT  1357.965 592.37 1358.345 592.75 ;
      END
   END dout1[274]
   PIN dout1[275]
      DIRECTION OUTPUT ;
      PORT
         LAYER met4 ;
         RECT  1362.935 592.37 1363.315 592.75 ;
      END
   END dout1[275]
   PIN dout1[276]
      DIRECTION OUTPUT ;
      PORT
         LAYER met4 ;
         RECT  1364.205 592.37 1364.585 592.75 ;
      END
   END dout1[276]
   PIN dout1[277]
      DIRECTION OUTPUT ;
      PORT
         LAYER met4 ;
         RECT  1369.175 592.37 1369.555 592.75 ;
      END
   END dout1[277]
   PIN dout1[278]
      DIRECTION OUTPUT ;
      PORT
         LAYER met4 ;
         RECT  1370.445 592.37 1370.825 592.75 ;
      END
   END dout1[278]
   PIN dout1[279]
      DIRECTION OUTPUT ;
      PORT
         LAYER met4 ;
         RECT  1375.415 592.37 1375.795 592.75 ;
      END
   END dout1[279]
   PIN dout1[280]
      DIRECTION OUTPUT ;
      PORT
         LAYER met4 ;
         RECT  1376.685 592.37 1377.065 592.75 ;
      END
   END dout1[280]
   PIN dout1[281]
      DIRECTION OUTPUT ;
      PORT
         LAYER met4 ;
         RECT  1381.655 592.37 1382.035 592.75 ;
      END
   END dout1[281]
   PIN dout1[282]
      DIRECTION OUTPUT ;
      PORT
         LAYER met4 ;
         RECT  1382.925 592.37 1383.305 592.75 ;
      END
   END dout1[282]
   PIN dout1[283]
      DIRECTION OUTPUT ;
      PORT
         LAYER met4 ;
         RECT  1387.895 592.37 1388.275 592.75 ;
      END
   END dout1[283]
   PIN dout1[284]
      DIRECTION OUTPUT ;
      PORT
         LAYER met4 ;
         RECT  1389.165 592.37 1389.545 592.75 ;
      END
   END dout1[284]
   PIN dout1[285]
      DIRECTION OUTPUT ;
      PORT
         LAYER met4 ;
         RECT  1394.135 592.37 1394.515 592.75 ;
      END
   END dout1[285]
   PIN dout1[286]
      DIRECTION OUTPUT ;
      PORT
         LAYER met4 ;
         RECT  1395.405 592.37 1395.785 592.75 ;
      END
   END dout1[286]
   PIN dout1[287]
      DIRECTION OUTPUT ;
      PORT
         LAYER met4 ;
         RECT  1400.375 592.37 1400.755 592.75 ;
      END
   END dout1[287]
   PIN dout1[288]
      DIRECTION OUTPUT ;
      PORT
         LAYER met4 ;
         RECT  1401.645 592.37 1402.025 592.75 ;
      END
   END dout1[288]
   PIN dout1[289]
      DIRECTION OUTPUT ;
      PORT
         LAYER met4 ;
         RECT  1406.615 592.37 1406.995 592.75 ;
      END
   END dout1[289]
   PIN dout1[290]
      DIRECTION OUTPUT ;
      PORT
         LAYER met4 ;
         RECT  1407.885 592.37 1408.265 592.75 ;
      END
   END dout1[290]
   PIN dout1[291]
      DIRECTION OUTPUT ;
      PORT
         LAYER met4 ;
         RECT  1412.855 592.37 1413.235 592.75 ;
      END
   END dout1[291]
   PIN dout1[292]
      DIRECTION OUTPUT ;
      PORT
         LAYER met4 ;
         RECT  1414.125 592.37 1414.505 592.75 ;
      END
   END dout1[292]
   PIN dout1[293]
      DIRECTION OUTPUT ;
      PORT
         LAYER met4 ;
         RECT  1419.095 592.37 1419.475 592.75 ;
      END
   END dout1[293]
   PIN dout1[294]
      DIRECTION OUTPUT ;
      PORT
         LAYER met4 ;
         RECT  1420.365 592.37 1420.745 592.75 ;
      END
   END dout1[294]
   PIN dout1[295]
      DIRECTION OUTPUT ;
      PORT
         LAYER met4 ;
         RECT  1425.335 592.37 1425.715 592.75 ;
      END
   END dout1[295]
   PIN dout1[296]
      DIRECTION OUTPUT ;
      PORT
         LAYER met4 ;
         RECT  1426.605 592.37 1426.985 592.75 ;
      END
   END dout1[296]
   PIN dout1[297]
      DIRECTION OUTPUT ;
      PORT
         LAYER met4 ;
         RECT  1431.575 592.37 1431.955 592.75 ;
      END
   END dout1[297]
   PIN dout1[298]
      DIRECTION OUTPUT ;
      PORT
         LAYER met4 ;
         RECT  1432.845 592.37 1433.225 592.75 ;
      END
   END dout1[298]
   PIN dout1[299]
      DIRECTION OUTPUT ;
      PORT
         LAYER met4 ;
         RECT  1437.815 592.37 1438.195 592.75 ;
      END
   END dout1[299]
   PIN dout1[300]
      DIRECTION OUTPUT ;
      PORT
         LAYER met4 ;
         RECT  1439.085 592.37 1439.465 592.75 ;
      END
   END dout1[300]
   PIN dout1[301]
      DIRECTION OUTPUT ;
      PORT
         LAYER met4 ;
         RECT  1444.055 592.37 1444.435 592.75 ;
      END
   END dout1[301]
   PIN dout1[302]
      DIRECTION OUTPUT ;
      PORT
         LAYER met4 ;
         RECT  1445.325 592.37 1445.705 592.75 ;
      END
   END dout1[302]
   PIN dout1[303]
      DIRECTION OUTPUT ;
      PORT
         LAYER met4 ;
         RECT  1450.295 592.37 1450.675 592.75 ;
      END
   END dout1[303]
   PIN dout1[304]
      DIRECTION OUTPUT ;
      PORT
         LAYER met4 ;
         RECT  1451.565 592.37 1451.945 592.75 ;
      END
   END dout1[304]
   PIN dout1[305]
      DIRECTION OUTPUT ;
      PORT
         LAYER met4 ;
         RECT  1456.535 592.37 1456.915 592.75 ;
      END
   END dout1[305]
   PIN dout1[306]
      DIRECTION OUTPUT ;
      PORT
         LAYER met4 ;
         RECT  1457.805 592.37 1458.185 592.75 ;
      END
   END dout1[306]
   PIN dout1[307]
      DIRECTION OUTPUT ;
      PORT
         LAYER met4 ;
         RECT  1462.775 592.37 1463.155 592.75 ;
      END
   END dout1[307]
   PIN dout1[308]
      DIRECTION OUTPUT ;
      PORT
         LAYER met4 ;
         RECT  1464.045 592.37 1464.425 592.75 ;
      END
   END dout1[308]
   PIN dout1[309]
      DIRECTION OUTPUT ;
      PORT
         LAYER met4 ;
         RECT  1469.015 592.37 1469.395 592.75 ;
      END
   END dout1[309]
   PIN dout1[310]
      DIRECTION OUTPUT ;
      PORT
         LAYER met4 ;
         RECT  1470.285 592.37 1470.665 592.75 ;
      END
   END dout1[310]
   PIN dout1[311]
      DIRECTION OUTPUT ;
      PORT
         LAYER met4 ;
         RECT  1475.255 592.37 1475.635 592.75 ;
      END
   END dout1[311]
   PIN dout1[312]
      DIRECTION OUTPUT ;
      PORT
         LAYER met4 ;
         RECT  1476.525 592.37 1476.905 592.75 ;
      END
   END dout1[312]
   PIN dout1[313]
      DIRECTION OUTPUT ;
      PORT
         LAYER met4 ;
         RECT  1481.495 592.37 1481.875 592.75 ;
      END
   END dout1[313]
   PIN dout1[314]
      DIRECTION OUTPUT ;
      PORT
         LAYER met4 ;
         RECT  1482.765 592.37 1483.145 592.75 ;
      END
   END dout1[314]
   PIN dout1[315]
      DIRECTION OUTPUT ;
      PORT
         LAYER met4 ;
         RECT  1487.735 592.37 1488.115 592.75 ;
      END
   END dout1[315]
   PIN dout1[316]
      DIRECTION OUTPUT ;
      PORT
         LAYER met4 ;
         RECT  1489.005 592.37 1489.385 592.75 ;
      END
   END dout1[316]
   PIN dout1[317]
      DIRECTION OUTPUT ;
      PORT
         LAYER met4 ;
         RECT  1493.975 592.37 1494.355 592.75 ;
      END
   END dout1[317]
   PIN dout1[318]
      DIRECTION OUTPUT ;
      PORT
         LAYER met4 ;
         RECT  1495.245 592.37 1495.625 592.75 ;
      END
   END dout1[318]
   PIN dout1[319]
      DIRECTION OUTPUT ;
      PORT
         LAYER met4 ;
         RECT  1500.215 592.37 1500.595 592.75 ;
      END
   END dout1[319]
   PIN dout1[320]
      DIRECTION OUTPUT ;
      PORT
         LAYER met4 ;
         RECT  1501.485 592.37 1501.865 592.75 ;
      END
   END dout1[320]
   PIN dout1[321]
      DIRECTION OUTPUT ;
      PORT
         LAYER met4 ;
         RECT  1506.455 592.37 1506.835 592.75 ;
      END
   END dout1[321]
   PIN dout1[322]
      DIRECTION OUTPUT ;
      PORT
         LAYER met4 ;
         RECT  1507.725 592.37 1508.105 592.75 ;
      END
   END dout1[322]
   PIN dout1[323]
      DIRECTION OUTPUT ;
      PORT
         LAYER met4 ;
         RECT  1512.695 592.37 1513.075 592.75 ;
      END
   END dout1[323]
   PIN dout1[324]
      DIRECTION OUTPUT ;
      PORT
         LAYER met4 ;
         RECT  1513.965 592.37 1514.345 592.75 ;
      END
   END dout1[324]
   PIN dout1[325]
      DIRECTION OUTPUT ;
      PORT
         LAYER met4 ;
         RECT  1518.935 592.37 1519.315 592.75 ;
      END
   END dout1[325]
   PIN dout1[326]
      DIRECTION OUTPUT ;
      PORT
         LAYER met4 ;
         RECT  1520.205 592.37 1520.585 592.75 ;
      END
   END dout1[326]
   PIN dout1[327]
      DIRECTION OUTPUT ;
      PORT
         LAYER met4 ;
         RECT  1525.175 592.37 1525.555 592.75 ;
      END
   END dout1[327]
   PIN dout1[328]
      DIRECTION OUTPUT ;
      PORT
         LAYER met4 ;
         RECT  1526.445 592.37 1526.825 592.75 ;
      END
   END dout1[328]
   PIN dout1[329]
      DIRECTION OUTPUT ;
      PORT
         LAYER met4 ;
         RECT  1531.415 592.37 1531.795 592.75 ;
      END
   END dout1[329]
   PIN dout1[330]
      DIRECTION OUTPUT ;
      PORT
         LAYER met4 ;
         RECT  1532.685 592.37 1533.065 592.75 ;
      END
   END dout1[330]
   PIN dout1[331]
      DIRECTION OUTPUT ;
      PORT
         LAYER met4 ;
         RECT  1537.655 592.37 1538.035 592.75 ;
      END
   END dout1[331]
   PIN dout1[332]
      DIRECTION OUTPUT ;
      PORT
         LAYER met4 ;
         RECT  1538.925 592.37 1539.305 592.75 ;
      END
   END dout1[332]
   PIN dout1[333]
      DIRECTION OUTPUT ;
      PORT
         LAYER met4 ;
         RECT  1543.895 592.37 1544.275 592.75 ;
      END
   END dout1[333]
   PIN dout1[334]
      DIRECTION OUTPUT ;
      PORT
         LAYER met4 ;
         RECT  1545.165 592.37 1545.545 592.75 ;
      END
   END dout1[334]
   PIN dout1[335]
      DIRECTION OUTPUT ;
      PORT
         LAYER met4 ;
         RECT  1550.135 592.37 1550.515 592.75 ;
      END
   END dout1[335]
   PIN dout1[336]
      DIRECTION OUTPUT ;
      PORT
         LAYER met4 ;
         RECT  1551.405 592.37 1551.785 592.75 ;
      END
   END dout1[336]
   PIN dout1[337]
      DIRECTION OUTPUT ;
      PORT
         LAYER met4 ;
         RECT  1556.375 592.37 1556.755 592.75 ;
      END
   END dout1[337]
   PIN dout1[338]
      DIRECTION OUTPUT ;
      PORT
         LAYER met4 ;
         RECT  1557.645 592.37 1558.025 592.75 ;
      END
   END dout1[338]
   PIN dout1[339]
      DIRECTION OUTPUT ;
      PORT
         LAYER met4 ;
         RECT  1562.615 592.37 1562.995 592.75 ;
      END
   END dout1[339]
   PIN dout1[340]
      DIRECTION OUTPUT ;
      PORT
         LAYER met4 ;
         RECT  1563.885 592.37 1564.265 592.75 ;
      END
   END dout1[340]
   PIN dout1[341]
      DIRECTION OUTPUT ;
      PORT
         LAYER met4 ;
         RECT  1568.855 592.37 1569.235 592.75 ;
      END
   END dout1[341]
   PIN dout1[342]
      DIRECTION OUTPUT ;
      PORT
         LAYER met4 ;
         RECT  1570.125 592.37 1570.505 592.75 ;
      END
   END dout1[342]
   PIN dout1[343]
      DIRECTION OUTPUT ;
      PORT
         LAYER met4 ;
         RECT  1575.095 592.37 1575.475 592.75 ;
      END
   END dout1[343]
   PIN dout1[344]
      DIRECTION OUTPUT ;
      PORT
         LAYER met4 ;
         RECT  1576.365 592.37 1576.745 592.75 ;
      END
   END dout1[344]
   PIN dout1[345]
      DIRECTION OUTPUT ;
      PORT
         LAYER met4 ;
         RECT  1581.335 592.37 1581.715 592.75 ;
      END
   END dout1[345]
   PIN dout1[346]
      DIRECTION OUTPUT ;
      PORT
         LAYER met4 ;
         RECT  1582.605 592.37 1582.985 592.75 ;
      END
   END dout1[346]
   PIN dout1[347]
      DIRECTION OUTPUT ;
      PORT
         LAYER met4 ;
         RECT  1587.575 592.37 1587.955 592.75 ;
      END
   END dout1[347]
   PIN dout1[348]
      DIRECTION OUTPUT ;
      PORT
         LAYER met4 ;
         RECT  1588.845 592.37 1589.225 592.75 ;
      END
   END dout1[348]
   PIN dout1[349]
      DIRECTION OUTPUT ;
      PORT
         LAYER met4 ;
         RECT  1593.815 592.37 1594.195 592.75 ;
      END
   END dout1[349]
   PIN dout1[350]
      DIRECTION OUTPUT ;
      PORT
         LAYER met4 ;
         RECT  1595.085 592.37 1595.465 592.75 ;
      END
   END dout1[350]
   PIN dout1[351]
      DIRECTION OUTPUT ;
      PORT
         LAYER met4 ;
         RECT  1600.055 592.37 1600.435 592.75 ;
      END
   END dout1[351]
   PIN dout1[352]
      DIRECTION OUTPUT ;
      PORT
         LAYER met4 ;
         RECT  1601.325 592.37 1601.705 592.75 ;
      END
   END dout1[352]
   PIN dout1[353]
      DIRECTION OUTPUT ;
      PORT
         LAYER met4 ;
         RECT  1606.295 592.37 1606.675 592.75 ;
      END
   END dout1[353]
   PIN dout1[354]
      DIRECTION OUTPUT ;
      PORT
         LAYER met4 ;
         RECT  1607.565 592.37 1607.945 592.75 ;
      END
   END dout1[354]
   PIN dout1[355]
      DIRECTION OUTPUT ;
      PORT
         LAYER met4 ;
         RECT  1612.535 592.37 1612.915 592.75 ;
      END
   END dout1[355]
   PIN dout1[356]
      DIRECTION OUTPUT ;
      PORT
         LAYER met4 ;
         RECT  1613.805 592.37 1614.185 592.75 ;
      END
   END dout1[356]
   PIN dout1[357]
      DIRECTION OUTPUT ;
      PORT
         LAYER met4 ;
         RECT  1618.775 592.37 1619.155 592.75 ;
      END
   END dout1[357]
   PIN dout1[358]
      DIRECTION OUTPUT ;
      PORT
         LAYER met4 ;
         RECT  1620.045 592.37 1620.425 592.75 ;
      END
   END dout1[358]
   PIN dout1[359]
      DIRECTION OUTPUT ;
      PORT
         LAYER met4 ;
         RECT  1625.015 592.37 1625.395 592.75 ;
      END
   END dout1[359]
   PIN dout1[360]
      DIRECTION OUTPUT ;
      PORT
         LAYER met4 ;
         RECT  1626.285 592.37 1626.665 592.75 ;
      END
   END dout1[360]
   PIN dout1[361]
      DIRECTION OUTPUT ;
      PORT
         LAYER met4 ;
         RECT  1631.255 592.37 1631.635 592.75 ;
      END
   END dout1[361]
   PIN dout1[362]
      DIRECTION OUTPUT ;
      PORT
         LAYER met4 ;
         RECT  1632.525 592.37 1632.905 592.75 ;
      END
   END dout1[362]
   PIN dout1[363]
      DIRECTION OUTPUT ;
      PORT
         LAYER met4 ;
         RECT  1637.495 592.37 1637.875 592.75 ;
      END
   END dout1[363]
   PIN dout1[364]
      DIRECTION OUTPUT ;
      PORT
         LAYER met4 ;
         RECT  1638.765 592.37 1639.145 592.75 ;
      END
   END dout1[364]
   PIN dout1[365]
      DIRECTION OUTPUT ;
      PORT
         LAYER met4 ;
         RECT  1643.735 592.37 1644.115 592.75 ;
      END
   END dout1[365]
   PIN dout1[366]
      DIRECTION OUTPUT ;
      PORT
         LAYER met4 ;
         RECT  1645.005 592.37 1645.385 592.75 ;
      END
   END dout1[366]
   PIN dout1[367]
      DIRECTION OUTPUT ;
      PORT
         LAYER met4 ;
         RECT  1649.975 592.37 1650.355 592.75 ;
      END
   END dout1[367]
   PIN dout1[368]
      DIRECTION OUTPUT ;
      PORT
         LAYER met4 ;
         RECT  1651.245 592.37 1651.625 592.75 ;
      END
   END dout1[368]
   PIN dout1[369]
      DIRECTION OUTPUT ;
      PORT
         LAYER met4 ;
         RECT  1656.215 592.37 1656.595 592.75 ;
      END
   END dout1[369]
   PIN dout1[370]
      DIRECTION OUTPUT ;
      PORT
         LAYER met4 ;
         RECT  1657.485 592.37 1657.865 592.75 ;
      END
   END dout1[370]
   PIN dout1[371]
      DIRECTION OUTPUT ;
      PORT
         LAYER met4 ;
         RECT  1662.455 592.37 1662.835 592.75 ;
      END
   END dout1[371]
   PIN dout1[372]
      DIRECTION OUTPUT ;
      PORT
         LAYER met4 ;
         RECT  1663.725 592.37 1664.105 592.75 ;
      END
   END dout1[372]
   PIN dout1[373]
      DIRECTION OUTPUT ;
      PORT
         LAYER met4 ;
         RECT  1668.695 592.37 1669.075 592.75 ;
      END
   END dout1[373]
   PIN dout1[374]
      DIRECTION OUTPUT ;
      PORT
         LAYER met4 ;
         RECT  1669.965 592.37 1670.345 592.75 ;
      END
   END dout1[374]
   PIN dout1[375]
      DIRECTION OUTPUT ;
      PORT
         LAYER met4 ;
         RECT  1674.935 592.37 1675.315 592.75 ;
      END
   END dout1[375]
   PIN dout1[376]
      DIRECTION OUTPUT ;
      PORT
         LAYER met4 ;
         RECT  1676.205 592.37 1676.585 592.75 ;
      END
   END dout1[376]
   PIN dout1[377]
      DIRECTION OUTPUT ;
      PORT
         LAYER met4 ;
         RECT  1681.175 592.37 1681.555 592.75 ;
      END
   END dout1[377]
   PIN dout1[378]
      DIRECTION OUTPUT ;
      PORT
         LAYER met4 ;
         RECT  1682.445 592.37 1682.825 592.75 ;
      END
   END dout1[378]
   PIN dout1[379]
      DIRECTION OUTPUT ;
      PORT
         LAYER met4 ;
         RECT  1687.415 592.37 1687.795 592.75 ;
      END
   END dout1[379]
   PIN dout1[380]
      DIRECTION OUTPUT ;
      PORT
         LAYER met4 ;
         RECT  1688.685 592.37 1689.065 592.75 ;
      END
   END dout1[380]
   PIN dout1[381]
      DIRECTION OUTPUT ;
      PORT
         LAYER met4 ;
         RECT  1693.655 592.37 1694.035 592.75 ;
      END
   END dout1[381]
   PIN dout1[382]
      DIRECTION OUTPUT ;
      PORT
         LAYER met4 ;
         RECT  1694.925 592.37 1695.305 592.75 ;
      END
   END dout1[382]
   PIN dout1[383]
      DIRECTION OUTPUT ;
      PORT
         LAYER met4 ;
         RECT  1699.895 592.37 1700.275 592.75 ;
      END
   END dout1[383]
   PIN dout1[384]
      DIRECTION OUTPUT ;
      PORT
         LAYER met4 ;
         RECT  1701.165 592.37 1701.545 592.75 ;
      END
   END dout1[384]
   PIN dout1[385]
      DIRECTION OUTPUT ;
      PORT
         LAYER met4 ;
         RECT  1706.135 592.37 1706.515 592.75 ;
      END
   END dout1[385]
   PIN dout1[386]
      DIRECTION OUTPUT ;
      PORT
         LAYER met4 ;
         RECT  1707.405 592.37 1707.785 592.75 ;
      END
   END dout1[386]
   PIN dout1[387]
      DIRECTION OUTPUT ;
      PORT
         LAYER met4 ;
         RECT  1712.375 592.37 1712.755 592.75 ;
      END
   END dout1[387]
   PIN dout1[388]
      DIRECTION OUTPUT ;
      PORT
         LAYER met4 ;
         RECT  1713.645 592.37 1714.025 592.75 ;
      END
   END dout1[388]
   PIN dout1[389]
      DIRECTION OUTPUT ;
      PORT
         LAYER met4 ;
         RECT  1718.615 592.37 1718.995 592.75 ;
      END
   END dout1[389]
   PIN dout1[390]
      DIRECTION OUTPUT ;
      PORT
         LAYER met4 ;
         RECT  1719.885 592.37 1720.265 592.75 ;
      END
   END dout1[390]
   PIN dout1[391]
      DIRECTION OUTPUT ;
      PORT
         LAYER met4 ;
         RECT  1724.855 592.37 1725.235 592.75 ;
      END
   END dout1[391]
   PIN dout1[392]
      DIRECTION OUTPUT ;
      PORT
         LAYER met4 ;
         RECT  1726.125 592.37 1726.505 592.75 ;
      END
   END dout1[392]
   PIN dout1[393]
      DIRECTION OUTPUT ;
      PORT
         LAYER met4 ;
         RECT  1731.095 592.37 1731.475 592.75 ;
      END
   END dout1[393]
   PIN dout1[394]
      DIRECTION OUTPUT ;
      PORT
         LAYER met4 ;
         RECT  1732.365 592.37 1732.745 592.75 ;
      END
   END dout1[394]
   PIN dout1[395]
      DIRECTION OUTPUT ;
      PORT
         LAYER met4 ;
         RECT  1737.335 592.37 1737.715 592.75 ;
      END
   END dout1[395]
   PIN dout1[396]
      DIRECTION OUTPUT ;
      PORT
         LAYER met4 ;
         RECT  1738.605 592.37 1738.985 592.75 ;
      END
   END dout1[396]
   PIN dout1[397]
      DIRECTION OUTPUT ;
      PORT
         LAYER met4 ;
         RECT  1743.575 592.37 1743.955 592.75 ;
      END
   END dout1[397]
   PIN dout1[398]
      DIRECTION OUTPUT ;
      PORT
         LAYER met4 ;
         RECT  1744.845 592.37 1745.225 592.75 ;
      END
   END dout1[398]
   PIN dout1[399]
      DIRECTION OUTPUT ;
      PORT
         LAYER met4 ;
         RECT  1749.815 592.37 1750.195 592.75 ;
      END
   END dout1[399]
   PIN dout1[400]
      DIRECTION OUTPUT ;
      PORT
         LAYER met4 ;
         RECT  1751.085 592.37 1751.465 592.75 ;
      END
   END dout1[400]
   PIN dout1[401]
      DIRECTION OUTPUT ;
      PORT
         LAYER met4 ;
         RECT  1756.055 592.37 1756.435 592.75 ;
      END
   END dout1[401]
   PIN dout1[402]
      DIRECTION OUTPUT ;
      PORT
         LAYER met4 ;
         RECT  1757.325 592.37 1757.705 592.75 ;
      END
   END dout1[402]
   PIN dout1[403]
      DIRECTION OUTPUT ;
      PORT
         LAYER met4 ;
         RECT  1762.295 592.37 1762.675 592.75 ;
      END
   END dout1[403]
   PIN dout1[404]
      DIRECTION OUTPUT ;
      PORT
         LAYER met4 ;
         RECT  1763.565 592.37 1763.945 592.75 ;
      END
   END dout1[404]
   PIN dout1[405]
      DIRECTION OUTPUT ;
      PORT
         LAYER met4 ;
         RECT  1768.535 592.37 1768.915 592.75 ;
      END
   END dout1[405]
   PIN dout1[406]
      DIRECTION OUTPUT ;
      PORT
         LAYER met4 ;
         RECT  1769.805 592.37 1770.185 592.75 ;
      END
   END dout1[406]
   PIN dout1[407]
      DIRECTION OUTPUT ;
      PORT
         LAYER met4 ;
         RECT  1774.775 592.37 1775.155 592.75 ;
      END
   END dout1[407]
   PIN dout1[408]
      DIRECTION OUTPUT ;
      PORT
         LAYER met4 ;
         RECT  1776.045 592.37 1776.425 592.75 ;
      END
   END dout1[408]
   PIN dout1[409]
      DIRECTION OUTPUT ;
      PORT
         LAYER met4 ;
         RECT  1781.015 592.37 1781.395 592.75 ;
      END
   END dout1[409]
   PIN dout1[410]
      DIRECTION OUTPUT ;
      PORT
         LAYER met4 ;
         RECT  1782.285 592.37 1782.665 592.75 ;
      END
   END dout1[410]
   PIN dout1[411]
      DIRECTION OUTPUT ;
      PORT
         LAYER met4 ;
         RECT  1787.255 592.37 1787.635 592.75 ;
      END
   END dout1[411]
   PIN dout1[412]
      DIRECTION OUTPUT ;
      PORT
         LAYER met4 ;
         RECT  1788.525 592.37 1788.905 592.75 ;
      END
   END dout1[412]
   PIN dout1[413]
      DIRECTION OUTPUT ;
      PORT
         LAYER met4 ;
         RECT  1793.495 592.37 1793.875 592.75 ;
      END
   END dout1[413]
   PIN dout1[414]
      DIRECTION OUTPUT ;
      PORT
         LAYER met4 ;
         RECT  1794.765 592.37 1795.145 592.75 ;
      END
   END dout1[414]
   PIN dout1[415]
      DIRECTION OUTPUT ;
      PORT
         LAYER met4 ;
         RECT  1799.735 592.37 1800.115 592.75 ;
      END
   END dout1[415]
   PIN dout1[416]
      DIRECTION OUTPUT ;
      PORT
         LAYER met4 ;
         RECT  1801.005 592.37 1801.385 592.75 ;
      END
   END dout1[416]
   PIN dout1[417]
      DIRECTION OUTPUT ;
      PORT
         LAYER met4 ;
         RECT  1805.975 592.37 1806.355 592.75 ;
      END
   END dout1[417]
   PIN dout1[418]
      DIRECTION OUTPUT ;
      PORT
         LAYER met4 ;
         RECT  1807.245 592.37 1807.625 592.75 ;
      END
   END dout1[418]
   PIN dout1[419]
      DIRECTION OUTPUT ;
      PORT
         LAYER met4 ;
         RECT  1812.215 592.37 1812.595 592.75 ;
      END
   END dout1[419]
   PIN dout1[420]
      DIRECTION OUTPUT ;
      PORT
         LAYER met4 ;
         RECT  1813.485 592.37 1813.865 592.75 ;
      END
   END dout1[420]
   PIN dout1[421]
      DIRECTION OUTPUT ;
      PORT
         LAYER met4 ;
         RECT  1818.455 592.37 1818.835 592.75 ;
      END
   END dout1[421]
   PIN dout1[422]
      DIRECTION OUTPUT ;
      PORT
         LAYER met4 ;
         RECT  1819.725 592.37 1820.105 592.75 ;
      END
   END dout1[422]
   PIN dout1[423]
      DIRECTION OUTPUT ;
      PORT
         LAYER met4 ;
         RECT  1824.695 592.37 1825.075 592.75 ;
      END
   END dout1[423]
   PIN dout1[424]
      DIRECTION OUTPUT ;
      PORT
         LAYER met4 ;
         RECT  1825.965 592.37 1826.345 592.75 ;
      END
   END dout1[424]
   PIN dout1[425]
      DIRECTION OUTPUT ;
      PORT
         LAYER met4 ;
         RECT  1830.935 592.37 1831.315 592.75 ;
      END
   END dout1[425]
   PIN dout1[426]
      DIRECTION OUTPUT ;
      PORT
         LAYER met4 ;
         RECT  1832.205 592.37 1832.585 592.75 ;
      END
   END dout1[426]
   PIN dout1[427]
      DIRECTION OUTPUT ;
      PORT
         LAYER met4 ;
         RECT  1837.175 592.37 1837.555 592.75 ;
      END
   END dout1[427]
   PIN dout1[428]
      DIRECTION OUTPUT ;
      PORT
         LAYER met4 ;
         RECT  1838.445 592.37 1838.825 592.75 ;
      END
   END dout1[428]
   PIN dout1[429]
      DIRECTION OUTPUT ;
      PORT
         LAYER met4 ;
         RECT  1843.415 592.37 1843.795 592.75 ;
      END
   END dout1[429]
   PIN dout1[430]
      DIRECTION OUTPUT ;
      PORT
         LAYER met4 ;
         RECT  1844.685 592.37 1845.065 592.75 ;
      END
   END dout1[430]
   PIN dout1[431]
      DIRECTION OUTPUT ;
      PORT
         LAYER met4 ;
         RECT  1849.655 592.37 1850.035 592.75 ;
      END
   END dout1[431]
   PIN dout1[432]
      DIRECTION OUTPUT ;
      PORT
         LAYER met4 ;
         RECT  1850.925 592.37 1851.305 592.75 ;
      END
   END dout1[432]
   PIN dout1[433]
      DIRECTION OUTPUT ;
      PORT
         LAYER met4 ;
         RECT  1855.895 592.37 1856.275 592.75 ;
      END
   END dout1[433]
   PIN dout1[434]
      DIRECTION OUTPUT ;
      PORT
         LAYER met4 ;
         RECT  1857.165 592.37 1857.545 592.75 ;
      END
   END dout1[434]
   PIN dout1[435]
      DIRECTION OUTPUT ;
      PORT
         LAYER met4 ;
         RECT  1862.135 592.37 1862.515 592.75 ;
      END
   END dout1[435]
   PIN dout1[436]
      DIRECTION OUTPUT ;
      PORT
         LAYER met4 ;
         RECT  1863.405 592.37 1863.785 592.75 ;
      END
   END dout1[436]
   PIN dout1[437]
      DIRECTION OUTPUT ;
      PORT
         LAYER met4 ;
         RECT  1868.375 592.37 1868.755 592.75 ;
      END
   END dout1[437]
   PIN dout1[438]
      DIRECTION OUTPUT ;
      PORT
         LAYER met4 ;
         RECT  1869.645 592.37 1870.025 592.75 ;
      END
   END dout1[438]
   PIN dout1[439]
      DIRECTION OUTPUT ;
      PORT
         LAYER met4 ;
         RECT  1874.615 592.37 1874.995 592.75 ;
      END
   END dout1[439]
   PIN dout1[440]
      DIRECTION OUTPUT ;
      PORT
         LAYER met4 ;
         RECT  1875.885 592.37 1876.265 592.75 ;
      END
   END dout1[440]
   PIN dout1[441]
      DIRECTION OUTPUT ;
      PORT
         LAYER met4 ;
         RECT  1880.855 592.37 1881.235 592.75 ;
      END
   END dout1[441]
   PIN dout1[442]
      DIRECTION OUTPUT ;
      PORT
         LAYER met4 ;
         RECT  1882.125 592.37 1882.505 592.75 ;
      END
   END dout1[442]
   PIN dout1[443]
      DIRECTION OUTPUT ;
      PORT
         LAYER met4 ;
         RECT  1887.095 592.37 1887.475 592.75 ;
      END
   END dout1[443]
   PIN dout1[444]
      DIRECTION OUTPUT ;
      PORT
         LAYER met4 ;
         RECT  1888.365 592.37 1888.745 592.75 ;
      END
   END dout1[444]
   PIN dout1[445]
      DIRECTION OUTPUT ;
      PORT
         LAYER met4 ;
         RECT  1893.335 592.37 1893.715 592.75 ;
      END
   END dout1[445]
   PIN dout1[446]
      DIRECTION OUTPUT ;
      PORT
         LAYER met4 ;
         RECT  1894.605 592.37 1894.985 592.75 ;
      END
   END dout1[446]
   PIN dout1[447]
      DIRECTION OUTPUT ;
      PORT
         LAYER met4 ;
         RECT  1899.575 592.37 1899.955 592.75 ;
      END
   END dout1[447]
   PIN dout1[448]
      DIRECTION OUTPUT ;
      PORT
         LAYER met4 ;
         RECT  1900.845 592.37 1901.225 592.75 ;
      END
   END dout1[448]
   PIN dout1[449]
      DIRECTION OUTPUT ;
      PORT
         LAYER met4 ;
         RECT  1905.815 592.37 1906.195 592.75 ;
      END
   END dout1[449]
   PIN dout1[450]
      DIRECTION OUTPUT ;
      PORT
         LAYER met4 ;
         RECT  1907.085 592.37 1907.465 592.75 ;
      END
   END dout1[450]
   PIN dout1[451]
      DIRECTION OUTPUT ;
      PORT
         LAYER met4 ;
         RECT  1912.055 592.37 1912.435 592.75 ;
      END
   END dout1[451]
   PIN dout1[452]
      DIRECTION OUTPUT ;
      PORT
         LAYER met4 ;
         RECT  1913.325 592.37 1913.705 592.75 ;
      END
   END dout1[452]
   PIN dout1[453]
      DIRECTION OUTPUT ;
      PORT
         LAYER met4 ;
         RECT  1918.295 592.37 1918.675 592.75 ;
      END
   END dout1[453]
   PIN dout1[454]
      DIRECTION OUTPUT ;
      PORT
         LAYER met4 ;
         RECT  1919.565 592.37 1919.945 592.75 ;
      END
   END dout1[454]
   PIN dout1[455]
      DIRECTION OUTPUT ;
      PORT
         LAYER met4 ;
         RECT  1924.535 592.37 1924.915 592.75 ;
      END
   END dout1[455]
   PIN dout1[456]
      DIRECTION OUTPUT ;
      PORT
         LAYER met4 ;
         RECT  1925.805 592.37 1926.185 592.75 ;
      END
   END dout1[456]
   PIN dout1[457]
      DIRECTION OUTPUT ;
      PORT
         LAYER met4 ;
         RECT  1930.775 592.37 1931.155 592.75 ;
      END
   END dout1[457]
   PIN dout1[458]
      DIRECTION OUTPUT ;
      PORT
         LAYER met4 ;
         RECT  1932.045 592.37 1932.425 592.75 ;
      END
   END dout1[458]
   PIN dout1[459]
      DIRECTION OUTPUT ;
      PORT
         LAYER met4 ;
         RECT  1937.015 592.37 1937.395 592.75 ;
      END
   END dout1[459]
   PIN dout1[460]
      DIRECTION OUTPUT ;
      PORT
         LAYER met4 ;
         RECT  1938.285 592.37 1938.665 592.75 ;
      END
   END dout1[460]
   PIN dout1[461]
      DIRECTION OUTPUT ;
      PORT
         LAYER met4 ;
         RECT  1943.255 592.37 1943.635 592.75 ;
      END
   END dout1[461]
   PIN dout1[462]
      DIRECTION OUTPUT ;
      PORT
         LAYER met4 ;
         RECT  1944.525 592.37 1944.905 592.75 ;
      END
   END dout1[462]
   PIN dout1[463]
      DIRECTION OUTPUT ;
      PORT
         LAYER met4 ;
         RECT  1949.495 592.37 1949.875 592.75 ;
      END
   END dout1[463]
   PIN dout1[464]
      DIRECTION OUTPUT ;
      PORT
         LAYER met4 ;
         RECT  1950.765 592.37 1951.145 592.75 ;
      END
   END dout1[464]
   PIN dout1[465]
      DIRECTION OUTPUT ;
      PORT
         LAYER met4 ;
         RECT  1955.735 592.37 1956.115 592.75 ;
      END
   END dout1[465]
   PIN dout1[466]
      DIRECTION OUTPUT ;
      PORT
         LAYER met4 ;
         RECT  1957.005 592.37 1957.385 592.75 ;
      END
   END dout1[466]
   PIN dout1[467]
      DIRECTION OUTPUT ;
      PORT
         LAYER met4 ;
         RECT  1961.975 592.37 1962.355 592.75 ;
      END
   END dout1[467]
   PIN dout1[468]
      DIRECTION OUTPUT ;
      PORT
         LAYER met4 ;
         RECT  1963.245 592.37 1963.625 592.75 ;
      END
   END dout1[468]
   PIN dout1[469]
      DIRECTION OUTPUT ;
      PORT
         LAYER met4 ;
         RECT  1968.215 592.37 1968.595 592.75 ;
      END
   END dout1[469]
   PIN dout1[470]
      DIRECTION OUTPUT ;
      PORT
         LAYER met4 ;
         RECT  1969.485 592.37 1969.865 592.75 ;
      END
   END dout1[470]
   PIN dout1[471]
      DIRECTION OUTPUT ;
      PORT
         LAYER met4 ;
         RECT  1974.455 592.37 1974.835 592.75 ;
      END
   END dout1[471]
   PIN dout1[472]
      DIRECTION OUTPUT ;
      PORT
         LAYER met4 ;
         RECT  1975.725 592.37 1976.105 592.75 ;
      END
   END dout1[472]
   PIN dout1[473]
      DIRECTION OUTPUT ;
      PORT
         LAYER met4 ;
         RECT  1980.695 592.37 1981.075 592.75 ;
      END
   END dout1[473]
   PIN dout1[474]
      DIRECTION OUTPUT ;
      PORT
         LAYER met4 ;
         RECT  1981.965 592.37 1982.345 592.75 ;
      END
   END dout1[474]
   PIN dout1[475]
      DIRECTION OUTPUT ;
      PORT
         LAYER met4 ;
         RECT  1986.935 592.37 1987.315 592.75 ;
      END
   END dout1[475]
   PIN dout1[476]
      DIRECTION OUTPUT ;
      PORT
         LAYER met4 ;
         RECT  1988.205 592.37 1988.585 592.75 ;
      END
   END dout1[476]
   PIN dout1[477]
      DIRECTION OUTPUT ;
      PORT
         LAYER met4 ;
         RECT  1993.175 592.37 1993.555 592.75 ;
      END
   END dout1[477]
   PIN dout1[478]
      DIRECTION OUTPUT ;
      PORT
         LAYER met4 ;
         RECT  1994.445 592.37 1994.825 592.75 ;
      END
   END dout1[478]
   PIN dout1[479]
      DIRECTION OUTPUT ;
      PORT
         LAYER met4 ;
         RECT  1999.415 592.37 1999.795 592.75 ;
      END
   END dout1[479]
   PIN dout1[480]
      DIRECTION OUTPUT ;
      PORT
         LAYER met4 ;
         RECT  2000.685 592.37 2001.065 592.75 ;
      END
   END dout1[480]
   PIN dout1[481]
      DIRECTION OUTPUT ;
      PORT
         LAYER met4 ;
         RECT  2005.655 592.37 2006.035 592.75 ;
      END
   END dout1[481]
   PIN dout1[482]
      DIRECTION OUTPUT ;
      PORT
         LAYER met4 ;
         RECT  2006.925 592.37 2007.305 592.75 ;
      END
   END dout1[482]
   PIN dout1[483]
      DIRECTION OUTPUT ;
      PORT
         LAYER met4 ;
         RECT  2011.895 592.37 2012.275 592.75 ;
      END
   END dout1[483]
   PIN dout1[484]
      DIRECTION OUTPUT ;
      PORT
         LAYER met4 ;
         RECT  2013.165 592.37 2013.545 592.75 ;
      END
   END dout1[484]
   PIN dout1[485]
      DIRECTION OUTPUT ;
      PORT
         LAYER met4 ;
         RECT  2018.135 592.37 2018.515 592.75 ;
      END
   END dout1[485]
   PIN dout1[486]
      DIRECTION OUTPUT ;
      PORT
         LAYER met4 ;
         RECT  2019.405 592.37 2019.785 592.75 ;
      END
   END dout1[486]
   PIN dout1[487]
      DIRECTION OUTPUT ;
      PORT
         LAYER met4 ;
         RECT  2024.375 592.37 2024.755 592.75 ;
      END
   END dout1[487]
   PIN dout1[488]
      DIRECTION OUTPUT ;
      PORT
         LAYER met4 ;
         RECT  2025.645 592.37 2026.025 592.75 ;
      END
   END dout1[488]
   PIN dout1[489]
      DIRECTION OUTPUT ;
      PORT
         LAYER met4 ;
         RECT  2030.615 592.37 2030.995 592.75 ;
      END
   END dout1[489]
   PIN dout1[490]
      DIRECTION OUTPUT ;
      PORT
         LAYER met4 ;
         RECT  2031.885 592.37 2032.265 592.75 ;
      END
   END dout1[490]
   PIN dout1[491]
      DIRECTION OUTPUT ;
      PORT
         LAYER met4 ;
         RECT  2036.855 592.37 2037.235 592.75 ;
      END
   END dout1[491]
   PIN dout1[492]
      DIRECTION OUTPUT ;
      PORT
         LAYER met4 ;
         RECT  2038.125 592.37 2038.505 592.75 ;
      END
   END dout1[492]
   PIN dout1[493]
      DIRECTION OUTPUT ;
      PORT
         LAYER met4 ;
         RECT  2043.095 592.37 2043.475 592.75 ;
      END
   END dout1[493]
   PIN dout1[494]
      DIRECTION OUTPUT ;
      PORT
         LAYER met4 ;
         RECT  2044.365 592.37 2044.745 592.75 ;
      END
   END dout1[494]
   PIN dout1[495]
      DIRECTION OUTPUT ;
      PORT
         LAYER met4 ;
         RECT  2049.335 592.37 2049.715 592.75 ;
      END
   END dout1[495]
   PIN dout1[496]
      DIRECTION OUTPUT ;
      PORT
         LAYER met4 ;
         RECT  2050.605 592.37 2050.985 592.75 ;
      END
   END dout1[496]
   PIN dout1[497]
      DIRECTION OUTPUT ;
      PORT
         LAYER met4 ;
         RECT  2055.575 592.37 2055.955 592.75 ;
      END
   END dout1[497]
   PIN dout1[498]
      DIRECTION OUTPUT ;
      PORT
         LAYER met4 ;
         RECT  2056.845 592.37 2057.225 592.75 ;
      END
   END dout1[498]
   PIN dout1[499]
      DIRECTION OUTPUT ;
      PORT
         LAYER met4 ;
         RECT  2061.815 592.37 2062.195 592.75 ;
      END
   END dout1[499]
   PIN dout1[500]
      DIRECTION OUTPUT ;
      PORT
         LAYER met4 ;
         RECT  2063.085 592.37 2063.465 592.75 ;
      END
   END dout1[500]
   PIN dout1[501]
      DIRECTION OUTPUT ;
      PORT
         LAYER met4 ;
         RECT  2068.055 592.37 2068.435 592.75 ;
      END
   END dout1[501]
   PIN dout1[502]
      DIRECTION OUTPUT ;
      PORT
         LAYER met4 ;
         RECT  2069.325 592.37 2069.705 592.75 ;
      END
   END dout1[502]
   PIN dout1[503]
      DIRECTION OUTPUT ;
      PORT
         LAYER met4 ;
         RECT  2074.295 592.37 2074.675 592.75 ;
      END
   END dout1[503]
   PIN dout1[504]
      DIRECTION OUTPUT ;
      PORT
         LAYER met4 ;
         RECT  2075.565 592.37 2075.945 592.75 ;
      END
   END dout1[504]
   PIN dout1[505]
      DIRECTION OUTPUT ;
      PORT
         LAYER met4 ;
         RECT  2080.535 592.37 2080.915 592.75 ;
      END
   END dout1[505]
   PIN dout1[506]
      DIRECTION OUTPUT ;
      PORT
         LAYER met4 ;
         RECT  2081.805 592.37 2082.185 592.75 ;
      END
   END dout1[506]
   PIN dout1[507]
      DIRECTION OUTPUT ;
      PORT
         LAYER met4 ;
         RECT  2086.775 592.37 2087.155 592.75 ;
      END
   END dout1[507]
   PIN dout1[508]
      DIRECTION OUTPUT ;
      PORT
         LAYER met4 ;
         RECT  2088.045 592.37 2088.425 592.75 ;
      END
   END dout1[508]
   PIN dout1[509]
      DIRECTION OUTPUT ;
      PORT
         LAYER met4 ;
         RECT  2093.015 592.37 2093.395 592.75 ;
      END
   END dout1[509]
   PIN dout1[510]
      DIRECTION OUTPUT ;
      PORT
         LAYER met4 ;
         RECT  2094.285 592.37 2094.665 592.75 ;
      END
   END dout1[510]
   PIN dout1[511]
      DIRECTION OUTPUT ;
      PORT
         LAYER met4 ;
         RECT  2099.255 592.37 2099.635 592.75 ;
      END
   END dout1[511]
   PIN vccd1
      DIRECTION INOUT ;
      USE POWER ; 
      SHAPE ABUTMENT ; 
      PORT
         LAYER met4 ;
         RECT  0.0 0.0 1.74 592.75 ;
         LAYER met3 ;
         RECT  0.0 0.0 3441.56 1.74 ;
         LAYER met4 ;
         RECT  3439.82 0.0 3441.56 592.75 ;
         LAYER met3 ;
         RECT  0.0 591.01 3441.56 592.75 ;
      END
   END vccd1
   PIN vssd1
      DIRECTION INOUT ;
      USE GROUND ; 
      SHAPE ABUTMENT ; 
      PORT
         LAYER met4 ;
         RECT  3.48 3.48 5.22 589.27 ;
         LAYER met4 ;
         RECT  3436.34 3.48 3438.08 589.27 ;
         LAYER met3 ;
         RECT  3.48 3.48 3438.08 5.22 ;
         LAYER met3 ;
         RECT  3.48 587.53 3438.08 589.27 ;
      END
   END vssd1
   OBS
   LAYER  met1 ;
      RECT  0.62 0.62 3440.94 592.13 ;
   LAYER  met2 ;
      RECT  0.62 0.62 3440.94 592.13 ;
   LAYER  met3 ;
      RECT  0.98 268.585 3440.94 270.165 ;
      RECT  0.62 2.34 0.98 268.585 ;
      RECT  0.62 271.655 0.98 590.41 ;
      RECT  0.98 2.34 2.88 2.88 ;
      RECT  0.98 2.88 2.88 5.82 ;
      RECT  0.98 5.82 2.88 268.585 ;
      RECT  2.88 2.34 3438.68 2.88 ;
      RECT  2.88 5.82 3438.68 268.585 ;
      RECT  3438.68 2.34 3440.94 2.88 ;
      RECT  3438.68 2.88 3440.94 5.82 ;
      RECT  3438.68 5.82 3440.94 268.585 ;
      RECT  0.98 270.165 2.88 586.93 ;
      RECT  0.98 586.93 2.88 589.87 ;
      RECT  0.98 589.87 2.88 590.41 ;
      RECT  2.88 270.165 3438.68 586.93 ;
      RECT  2.88 589.87 3438.68 590.41 ;
      RECT  3438.68 270.165 3440.94 586.93 ;
      RECT  3438.68 586.93 3440.94 589.87 ;
      RECT  3438.68 589.87 3440.94 590.41 ;
   LAYER  met4 ;
      RECT  439.3 0.98 440.88 592.13 ;
      RECT  440.88 0.62 445.14 0.98 ;
      RECT  446.72 0.62 450.98 0.98 ;
      RECT  452.56 0.62 456.82 0.98 ;
      RECT  458.4 0.62 462.66 0.98 ;
      RECT  464.24 0.62 468.5 0.98 ;
      RECT  470.08 0.62 474.34 0.98 ;
      RECT  475.92 0.62 480.18 0.98 ;
      RECT  481.76 0.62 486.02 0.98 ;
      RECT  487.6 0.62 491.86 0.98 ;
      RECT  493.44 0.62 497.7 0.98 ;
      RECT  499.28 0.62 503.54 0.98 ;
      RECT  505.12 0.62 509.38 0.98 ;
      RECT  510.96 0.62 515.22 0.98 ;
      RECT  516.8 0.62 521.06 0.98 ;
      RECT  522.64 0.62 526.9 0.98 ;
      RECT  528.48 0.62 532.74 0.98 ;
      RECT  534.32 0.62 538.58 0.98 ;
      RECT  540.16 0.62 544.42 0.98 ;
      RECT  546.0 0.62 550.26 0.98 ;
      RECT  551.84 0.62 556.1 0.98 ;
      RECT  557.68 0.62 561.94 0.98 ;
      RECT  563.52 0.62 567.78 0.98 ;
      RECT  569.36 0.62 573.62 0.98 ;
      RECT  575.2 0.62 579.46 0.98 ;
      RECT  581.04 0.62 585.3 0.98 ;
      RECT  586.88 0.62 591.14 0.98 ;
      RECT  592.72 0.62 596.98 0.98 ;
      RECT  598.56 0.62 602.82 0.98 ;
      RECT  604.4 0.62 608.66 0.98 ;
      RECT  610.24 0.62 614.5 0.98 ;
      RECT  616.08 0.62 620.34 0.98 ;
      RECT  621.92 0.62 626.18 0.98 ;
      RECT  627.76 0.62 632.02 0.98 ;
      RECT  633.6 0.62 637.86 0.98 ;
      RECT  639.44 0.62 643.7 0.98 ;
      RECT  645.28 0.62 649.54 0.98 ;
      RECT  651.12 0.62 655.38 0.98 ;
      RECT  656.96 0.62 661.22 0.98 ;
      RECT  662.8 0.62 667.06 0.98 ;
      RECT  668.64 0.62 672.9 0.98 ;
      RECT  674.48 0.62 678.74 0.98 ;
      RECT  680.32 0.62 684.58 0.98 ;
      RECT  686.16 0.62 690.42 0.98 ;
      RECT  692.0 0.62 696.26 0.98 ;
      RECT  697.84 0.62 702.1 0.98 ;
      RECT  703.68 0.62 707.94 0.98 ;
      RECT  709.52 0.62 713.78 0.98 ;
      RECT  715.36 0.62 719.62 0.98 ;
      RECT  721.2 0.62 725.46 0.98 ;
      RECT  727.04 0.62 731.3 0.98 ;
      RECT  732.88 0.62 737.14 0.98 ;
      RECT  738.72 0.62 742.98 0.98 ;
      RECT  744.56 0.62 748.82 0.98 ;
      RECT  750.4 0.62 754.66 0.98 ;
      RECT  756.24 0.62 760.5 0.98 ;
      RECT  762.08 0.62 766.34 0.98 ;
      RECT  767.92 0.62 772.18 0.98 ;
      RECT  773.76 0.62 778.02 0.98 ;
      RECT  779.6 0.62 783.86 0.98 ;
      RECT  785.44 0.62 789.7 0.98 ;
      RECT  791.28 0.62 795.54 0.98 ;
      RECT  797.12 0.62 801.38 0.98 ;
      RECT  802.96 0.62 807.22 0.98 ;
      RECT  808.8 0.62 813.06 0.98 ;
      RECT  814.64 0.62 818.9 0.98 ;
      RECT  820.48 0.62 824.74 0.98 ;
      RECT  826.32 0.62 830.58 0.98 ;
      RECT  832.16 0.62 836.42 0.98 ;
      RECT  838.0 0.62 842.26 0.98 ;
      RECT  843.84 0.62 848.1 0.98 ;
      RECT  849.68 0.62 853.94 0.98 ;
      RECT  855.52 0.62 859.78 0.98 ;
      RECT  861.36 0.62 865.62 0.98 ;
      RECT  867.2 0.62 871.46 0.98 ;
      RECT  873.04 0.62 877.3 0.98 ;
      RECT  878.88 0.62 883.14 0.98 ;
      RECT  884.72 0.62 888.98 0.98 ;
      RECT  890.56 0.62 894.82 0.98 ;
      RECT  896.4 0.62 900.66 0.98 ;
      RECT  902.24 0.62 906.5 0.98 ;
      RECT  908.08 0.62 912.34 0.98 ;
      RECT  913.92 0.62 918.18 0.98 ;
      RECT  919.76 0.62 924.02 0.98 ;
      RECT  925.6 0.62 929.86 0.98 ;
      RECT  931.44 0.62 935.7 0.98 ;
      RECT  937.28 0.62 941.54 0.98 ;
      RECT  943.12 0.62 947.38 0.98 ;
      RECT  948.96 0.62 953.22 0.98 ;
      RECT  954.8 0.62 959.06 0.98 ;
      RECT  960.64 0.62 964.9 0.98 ;
      RECT  966.48 0.62 970.74 0.98 ;
      RECT  972.32 0.62 976.58 0.98 ;
      RECT  978.16 0.62 982.42 0.98 ;
      RECT  984.0 0.62 988.26 0.98 ;
      RECT  989.84 0.62 994.1 0.98 ;
      RECT  995.68 0.62 999.94 0.98 ;
      RECT  1001.52 0.62 1005.78 0.98 ;
      RECT  1007.36 0.62 1011.62 0.98 ;
      RECT  1013.2 0.62 1017.46 0.98 ;
      RECT  1019.04 0.62 1023.3 0.98 ;
      RECT  1024.88 0.62 1029.14 0.98 ;
      RECT  1030.72 0.62 1034.98 0.98 ;
      RECT  1036.56 0.62 1040.82 0.98 ;
      RECT  1042.4 0.62 1046.66 0.98 ;
      RECT  1048.24 0.62 1052.5 0.98 ;
      RECT  1054.08 0.62 1058.34 0.98 ;
      RECT  1059.92 0.62 1064.18 0.98 ;
      RECT  1065.76 0.62 1070.02 0.98 ;
      RECT  1071.6 0.62 1075.86 0.98 ;
      RECT  1077.44 0.62 1081.7 0.98 ;
      RECT  1083.28 0.62 1087.54 0.98 ;
      RECT  1089.12 0.62 1093.38 0.98 ;
      RECT  1094.96 0.62 1099.22 0.98 ;
      RECT  1100.8 0.62 1105.06 0.98 ;
      RECT  1106.64 0.62 1110.9 0.98 ;
      RECT  1112.48 0.62 1116.74 0.98 ;
      RECT  1118.32 0.62 1122.58 0.98 ;
      RECT  1124.16 0.62 1128.42 0.98 ;
      RECT  1130.0 0.62 1134.26 0.98 ;
      RECT  1135.84 0.62 1140.1 0.98 ;
      RECT  1141.68 0.62 1145.94 0.98 ;
      RECT  1147.52 0.62 1151.78 0.98 ;
      RECT  1153.36 0.62 1157.62 0.98 ;
      RECT  1159.2 0.62 1163.46 0.98 ;
      RECT  1165.04 0.62 1169.3 0.98 ;
      RECT  1170.88 0.62 1175.14 0.98 ;
      RECT  1176.72 0.62 1180.98 0.98 ;
      RECT  1182.56 0.62 1186.82 0.98 ;
      RECT  1188.4 0.62 1192.66 0.98 ;
      RECT  1194.24 0.62 1198.5 0.98 ;
      RECT  1200.08 0.62 1204.34 0.98 ;
      RECT  1205.92 0.62 1210.18 0.98 ;
      RECT  1211.76 0.62 1216.02 0.98 ;
      RECT  1217.6 0.62 1221.86 0.98 ;
      RECT  1223.44 0.62 1227.7 0.98 ;
      RECT  1229.28 0.62 1233.54 0.98 ;
      RECT  1235.12 0.62 1239.38 0.98 ;
      RECT  1240.96 0.62 1245.22 0.98 ;
      RECT  1246.8 0.62 1251.06 0.98 ;
      RECT  1252.64 0.62 1256.9 0.98 ;
      RECT  1258.48 0.62 1262.74 0.98 ;
      RECT  1264.32 0.62 1268.58 0.98 ;
      RECT  1270.16 0.62 1274.42 0.98 ;
      RECT  1276.0 0.62 1280.26 0.98 ;
      RECT  1281.84 0.62 1286.1 0.98 ;
      RECT  1287.68 0.62 1291.94 0.98 ;
      RECT  1293.52 0.62 1297.78 0.98 ;
      RECT  1299.36 0.62 1303.62 0.98 ;
      RECT  1305.2 0.62 1309.46 0.98 ;
      RECT  1311.04 0.62 1315.3 0.98 ;
      RECT  1316.88 0.62 1321.14 0.98 ;
      RECT  1322.72 0.62 1326.98 0.98 ;
      RECT  1328.56 0.62 1332.82 0.98 ;
      RECT  1334.4 0.62 1338.66 0.98 ;
      RECT  1340.24 0.62 1344.5 0.98 ;
      RECT  1346.08 0.62 1350.34 0.98 ;
      RECT  1351.92 0.62 1356.18 0.98 ;
      RECT  1357.76 0.62 1362.02 0.98 ;
      RECT  1363.6 0.62 1367.86 0.98 ;
      RECT  1369.44 0.62 1373.7 0.98 ;
      RECT  1375.28 0.62 1379.54 0.98 ;
      RECT  1381.12 0.62 1385.38 0.98 ;
      RECT  1386.96 0.62 1391.22 0.98 ;
      RECT  1392.8 0.62 1397.06 0.98 ;
      RECT  1398.64 0.62 1402.9 0.98 ;
      RECT  1404.48 0.62 1408.74 0.98 ;
      RECT  1410.32 0.62 1414.58 0.98 ;
      RECT  1416.16 0.62 1420.42 0.98 ;
      RECT  1422.0 0.62 1426.26 0.98 ;
      RECT  1427.84 0.62 1432.1 0.98 ;
      RECT  1433.68 0.62 1437.94 0.98 ;
      RECT  1439.52 0.62 1443.78 0.98 ;
      RECT  1445.36 0.62 1449.62 0.98 ;
      RECT  1451.2 0.62 1455.46 0.98 ;
      RECT  1457.04 0.62 1461.3 0.98 ;
      RECT  1462.88 0.62 1467.14 0.98 ;
      RECT  1468.72 0.62 1472.98 0.98 ;
      RECT  1474.56 0.62 1478.82 0.98 ;
      RECT  1480.4 0.62 1484.66 0.98 ;
      RECT  1486.24 0.62 1490.5 0.98 ;
      RECT  1492.08 0.62 1496.34 0.98 ;
      RECT  1497.92 0.62 1502.18 0.98 ;
      RECT  1503.76 0.62 1508.02 0.98 ;
      RECT  1509.6 0.62 1513.86 0.98 ;
      RECT  1515.44 0.62 1519.7 0.98 ;
      RECT  1521.28 0.62 1525.54 0.98 ;
      RECT  1527.12 0.62 1531.38 0.98 ;
      RECT  1532.96 0.62 1537.22 0.98 ;
      RECT  1538.8 0.62 1543.06 0.98 ;
      RECT  1544.64 0.62 1548.9 0.98 ;
      RECT  1550.48 0.62 1554.74 0.98 ;
      RECT  1556.32 0.62 1560.58 0.98 ;
      RECT  1562.16 0.62 1566.42 0.98 ;
      RECT  1568.0 0.62 1572.26 0.98 ;
      RECT  1573.84 0.62 1578.1 0.98 ;
      RECT  1579.68 0.62 1583.94 0.98 ;
      RECT  1585.52 0.62 1589.78 0.98 ;
      RECT  1591.36 0.62 1595.62 0.98 ;
      RECT  1597.2 0.62 1601.46 0.98 ;
      RECT  1603.04 0.62 1607.3 0.98 ;
      RECT  1608.88 0.62 1613.14 0.98 ;
      RECT  1614.72 0.62 1618.98 0.98 ;
      RECT  1620.56 0.62 1624.82 0.98 ;
      RECT  1626.4 0.62 1630.66 0.98 ;
      RECT  1632.24 0.62 1636.5 0.98 ;
      RECT  1638.08 0.62 1642.34 0.98 ;
      RECT  1643.92 0.62 1648.18 0.98 ;
      RECT  1649.76 0.62 1654.02 0.98 ;
      RECT  1655.6 0.62 1659.86 0.98 ;
      RECT  1661.44 0.62 1665.7 0.98 ;
      RECT  1667.28 0.62 1671.54 0.98 ;
      RECT  1673.12 0.62 1677.38 0.98 ;
      RECT  1678.96 0.62 1683.22 0.98 ;
      RECT  1684.8 0.62 1689.06 0.98 ;
      RECT  1690.64 0.62 1694.9 0.98 ;
      RECT  1696.48 0.62 1700.74 0.98 ;
      RECT  1702.32 0.62 1706.58 0.98 ;
      RECT  1708.16 0.62 1712.42 0.98 ;
      RECT  1714.0 0.62 1718.26 0.98 ;
      RECT  1719.84 0.62 1724.1 0.98 ;
      RECT  1725.68 0.62 1729.94 0.98 ;
      RECT  1731.52 0.62 1735.78 0.98 ;
      RECT  1737.36 0.62 1741.62 0.98 ;
      RECT  1743.2 0.62 1747.46 0.98 ;
      RECT  1749.04 0.62 1753.3 0.98 ;
      RECT  1754.88 0.62 1759.14 0.98 ;
      RECT  1760.72 0.62 1764.98 0.98 ;
      RECT  1766.56 0.62 1770.82 0.98 ;
      RECT  1772.4 0.62 1776.66 0.98 ;
      RECT  1778.24 0.62 1782.5 0.98 ;
      RECT  1784.08 0.62 1788.34 0.98 ;
      RECT  1789.92 0.62 1794.18 0.98 ;
      RECT  1795.76 0.62 1800.02 0.98 ;
      RECT  1801.6 0.62 1805.86 0.98 ;
      RECT  1807.44 0.62 1811.7 0.98 ;
      RECT  1813.28 0.62 1817.54 0.98 ;
      RECT  1819.12 0.62 1823.38 0.98 ;
      RECT  1824.96 0.62 1829.22 0.98 ;
      RECT  1830.8 0.62 1835.06 0.98 ;
      RECT  1836.64 0.62 1840.9 0.98 ;
      RECT  1842.48 0.62 1846.74 0.98 ;
      RECT  1848.32 0.62 1852.58 0.98 ;
      RECT  1854.16 0.62 1858.42 0.98 ;
      RECT  1860.0 0.62 1864.26 0.98 ;
      RECT  1865.84 0.62 1870.1 0.98 ;
      RECT  1871.68 0.62 1875.94 0.98 ;
      RECT  1877.52 0.62 1881.78 0.98 ;
      RECT  1883.36 0.62 1887.62 0.98 ;
      RECT  1889.2 0.62 1893.46 0.98 ;
      RECT  1895.04 0.62 1899.3 0.98 ;
      RECT  1900.88 0.62 1905.14 0.98 ;
      RECT  1906.72 0.62 1910.98 0.98 ;
      RECT  1912.56 0.62 1916.82 0.98 ;
      RECT  1918.4 0.62 1922.66 0.98 ;
      RECT  1924.24 0.62 1928.5 0.98 ;
      RECT  1930.08 0.62 1934.34 0.98 ;
      RECT  1935.92 0.62 1940.18 0.98 ;
      RECT  1941.76 0.62 1946.02 0.98 ;
      RECT  1947.6 0.62 1951.86 0.98 ;
      RECT  1953.44 0.62 1957.7 0.98 ;
      RECT  1959.28 0.62 1963.54 0.98 ;
      RECT  1965.12 0.62 1969.38 0.98 ;
      RECT  1970.96 0.62 1975.22 0.98 ;
      RECT  1976.8 0.62 1981.06 0.98 ;
      RECT  1982.64 0.62 1986.9 0.98 ;
      RECT  1988.48 0.62 1992.74 0.98 ;
      RECT  1994.32 0.62 1998.58 0.98 ;
      RECT  2000.16 0.62 2004.42 0.98 ;
      RECT  2006.0 0.62 2010.26 0.98 ;
      RECT  2011.84 0.62 2016.1 0.98 ;
      RECT  2017.68 0.62 2021.94 0.98 ;
      RECT  2023.52 0.62 2027.78 0.98 ;
      RECT  2029.36 0.62 2033.62 0.98 ;
      RECT  2035.2 0.62 2039.46 0.98 ;
      RECT  2041.04 0.62 2045.3 0.98 ;
      RECT  2046.88 0.62 2051.14 0.98 ;
      RECT  2052.72 0.62 2056.98 0.98 ;
      RECT  2058.56 0.62 2062.82 0.98 ;
      RECT  2064.4 0.62 2068.66 0.98 ;
      RECT  2070.24 0.62 2074.5 0.98 ;
      RECT  2076.08 0.62 2080.34 0.98 ;
      RECT  2081.92 0.62 2086.18 0.98 ;
      RECT  2087.76 0.62 2092.02 0.98 ;
      RECT  2093.6 0.62 2097.86 0.98 ;
      RECT  2099.44 0.62 2103.7 0.98 ;
      RECT  2105.28 0.62 2109.54 0.98 ;
      RECT  2111.12 0.62 2115.38 0.98 ;
      RECT  2116.96 0.62 2121.22 0.98 ;
      RECT  2122.8 0.62 2127.06 0.98 ;
      RECT  2128.64 0.62 2132.9 0.98 ;
      RECT  2134.48 0.62 2138.74 0.98 ;
      RECT  2140.32 0.62 2144.58 0.98 ;
      RECT  2146.16 0.62 2150.42 0.98 ;
      RECT  2152.0 0.62 2156.26 0.98 ;
      RECT  2157.84 0.62 2162.1 0.98 ;
      RECT  2163.68 0.62 2167.94 0.98 ;
      RECT  2181.2 0.62 2185.46 0.98 ;
      RECT  2187.04 0.62 2191.3 0.98 ;
      RECT  2192.88 0.62 2197.14 0.98 ;
      RECT  2198.72 0.62 2202.98 0.98 ;
      RECT  2204.56 0.62 2208.82 0.98 ;
      RECT  2210.4 0.62 2214.66 0.98 ;
      RECT  2216.24 0.62 2220.5 0.98 ;
      RECT  2222.08 0.62 2226.34 0.98 ;
      RECT  2227.92 0.62 2232.18 0.98 ;
      RECT  2233.76 0.62 2238.02 0.98 ;
      RECT  2239.6 0.62 2243.86 0.98 ;
      RECT  2245.44 0.62 2249.7 0.98 ;
      RECT  2251.28 0.62 2255.54 0.98 ;
      RECT  2257.12 0.62 2261.38 0.98 ;
      RECT  2262.96 0.62 2267.22 0.98 ;
      RECT  2268.8 0.62 2273.06 0.98 ;
      RECT  2274.64 0.62 2278.9 0.98 ;
      RECT  2280.48 0.62 2284.74 0.98 ;
      RECT  2286.32 0.62 2290.58 0.98 ;
      RECT  2292.16 0.62 2296.42 0.98 ;
      RECT  2298.0 0.62 2302.26 0.98 ;
      RECT  2303.84 0.62 2308.1 0.98 ;
      RECT  2309.68 0.62 2313.94 0.98 ;
      RECT  2315.52 0.62 2319.78 0.98 ;
      RECT  2321.36 0.62 2325.62 0.98 ;
      RECT  2327.2 0.62 2331.46 0.98 ;
      RECT  2333.04 0.62 2337.3 0.98 ;
      RECT  2338.88 0.62 2343.14 0.98 ;
      RECT  2344.72 0.62 2348.98 0.98 ;
      RECT  2350.56 0.62 2354.82 0.98 ;
      RECT  2356.4 0.62 2360.66 0.98 ;
      RECT  2362.24 0.62 2366.5 0.98 ;
      RECT  2368.08 0.62 2372.34 0.98 ;
      RECT  2373.92 0.62 2378.18 0.98 ;
      RECT  2379.76 0.62 2384.02 0.98 ;
      RECT  2385.6 0.62 2389.86 0.98 ;
      RECT  2391.44 0.62 2395.7 0.98 ;
      RECT  2397.28 0.62 2401.54 0.98 ;
      RECT  2403.12 0.62 2407.38 0.98 ;
      RECT  2408.96 0.62 2413.22 0.98 ;
      RECT  2414.8 0.62 2419.06 0.98 ;
      RECT  2420.64 0.62 2424.9 0.98 ;
      RECT  2426.48 0.62 2430.74 0.98 ;
      RECT  2432.32 0.62 2436.58 0.98 ;
      RECT  2438.16 0.62 2442.42 0.98 ;
      RECT  2444.0 0.62 2448.26 0.98 ;
      RECT  2449.84 0.62 2454.1 0.98 ;
      RECT  2455.68 0.62 2459.94 0.98 ;
      RECT  2461.52 0.62 2465.78 0.98 ;
      RECT  2467.36 0.62 2471.62 0.98 ;
      RECT  2473.2 0.62 2477.46 0.98 ;
      RECT  2479.04 0.62 2483.3 0.98 ;
      RECT  2484.88 0.62 2489.14 0.98 ;
      RECT  2490.72 0.62 2494.98 0.98 ;
      RECT  2496.56 0.62 2500.82 0.98 ;
      RECT  2502.4 0.62 2506.66 0.98 ;
      RECT  2508.24 0.62 2512.5 0.98 ;
      RECT  2514.08 0.62 2518.34 0.98 ;
      RECT  2519.92 0.62 2524.18 0.98 ;
      RECT  2525.76 0.62 2530.02 0.98 ;
      RECT  2531.6 0.62 2535.86 0.98 ;
      RECT  2537.44 0.62 2541.7 0.98 ;
      RECT  2543.28 0.62 2547.54 0.98 ;
      RECT  2549.12 0.62 2553.38 0.98 ;
      RECT  2554.96 0.62 2559.22 0.98 ;
      RECT  2560.8 0.62 2565.06 0.98 ;
      RECT  2566.64 0.62 2570.9 0.98 ;
      RECT  2572.48 0.62 2576.74 0.98 ;
      RECT  2578.32 0.62 2582.58 0.98 ;
      RECT  2584.16 0.62 2588.42 0.98 ;
      RECT  2590.0 0.62 2594.26 0.98 ;
      RECT  2595.84 0.62 2600.1 0.98 ;
      RECT  2601.68 0.62 2605.94 0.98 ;
      RECT  2607.52 0.62 2611.78 0.98 ;
      RECT  2613.36 0.62 2617.62 0.98 ;
      RECT  2619.2 0.62 2623.46 0.98 ;
      RECT  2625.04 0.62 2629.3 0.98 ;
      RECT  2630.88 0.62 2635.14 0.98 ;
      RECT  2636.72 0.62 2640.98 0.98 ;
      RECT  2642.56 0.62 2646.82 0.98 ;
      RECT  2648.4 0.62 2652.66 0.98 ;
      RECT  2654.24 0.62 2658.5 0.98 ;
      RECT  2660.08 0.62 2664.34 0.98 ;
      RECT  2665.92 0.62 2670.18 0.98 ;
      RECT  2671.76 0.62 2676.02 0.98 ;
      RECT  2677.6 0.62 2681.86 0.98 ;
      RECT  2683.44 0.62 2687.7 0.98 ;
      RECT  2689.28 0.62 2693.54 0.98 ;
      RECT  2695.12 0.62 2699.38 0.98 ;
      RECT  2700.96 0.62 2705.22 0.98 ;
      RECT  2706.8 0.62 2711.06 0.98 ;
      RECT  2712.64 0.62 2716.9 0.98 ;
      RECT  2718.48 0.62 2722.74 0.98 ;
      RECT  2724.32 0.62 2728.58 0.98 ;
      RECT  2730.16 0.62 2734.42 0.98 ;
      RECT  2736.0 0.62 2740.26 0.98 ;
      RECT  2741.84 0.62 2746.1 0.98 ;
      RECT  2747.68 0.62 2751.94 0.98 ;
      RECT  2753.52 0.62 2757.78 0.98 ;
      RECT  2759.36 0.62 2763.62 0.98 ;
      RECT  2765.2 0.62 2769.46 0.98 ;
      RECT  2771.04 0.62 2775.3 0.98 ;
      RECT  2776.88 0.62 2781.14 0.98 ;
      RECT  2782.72 0.62 2786.98 0.98 ;
      RECT  2788.56 0.62 2792.82 0.98 ;
      RECT  2794.4 0.62 2798.66 0.98 ;
      RECT  2800.24 0.62 2804.5 0.98 ;
      RECT  2806.08 0.62 2810.34 0.98 ;
      RECT  2811.92 0.62 2816.18 0.98 ;
      RECT  2817.76 0.62 2822.02 0.98 ;
      RECT  2823.6 0.62 2827.86 0.98 ;
      RECT  2829.44 0.62 2833.7 0.98 ;
      RECT  2835.28 0.62 2839.54 0.98 ;
      RECT  2841.12 0.62 2845.38 0.98 ;
      RECT  2846.96 0.62 2851.22 0.98 ;
      RECT  2852.8 0.62 2857.06 0.98 ;
      RECT  2858.64 0.62 2862.9 0.98 ;
      RECT  2864.48 0.62 2868.74 0.98 ;
      RECT  2870.32 0.62 2874.58 0.98 ;
      RECT  2876.16 0.62 2880.42 0.98 ;
      RECT  2882.0 0.62 2886.26 0.98 ;
      RECT  2887.84 0.62 2892.1 0.98 ;
      RECT  2893.68 0.62 2897.94 0.98 ;
      RECT  2899.52 0.62 2903.78 0.98 ;
      RECT  2905.36 0.62 2909.62 0.98 ;
      RECT  2911.2 0.62 2915.46 0.98 ;
      RECT  2917.04 0.62 2921.3 0.98 ;
      RECT  2922.88 0.62 2927.14 0.98 ;
      RECT  2928.72 0.62 2932.98 0.98 ;
      RECT  2934.56 0.62 2938.82 0.98 ;
      RECT  2940.4 0.62 2944.66 0.98 ;
      RECT  2946.24 0.62 2950.5 0.98 ;
      RECT  2952.08 0.62 2956.34 0.98 ;
      RECT  2957.92 0.62 2962.18 0.98 ;
      RECT  2963.76 0.62 2968.02 0.98 ;
      RECT  2969.6 0.62 2973.86 0.98 ;
      RECT  2975.44 0.62 2979.7 0.98 ;
      RECT  2981.28 0.62 2985.54 0.98 ;
      RECT  2987.12 0.62 2991.38 0.98 ;
      RECT  2992.96 0.62 2997.22 0.98 ;
      RECT  2998.8 0.62 3003.06 0.98 ;
      RECT  3004.64 0.62 3008.9 0.98 ;
      RECT  3010.48 0.62 3014.74 0.98 ;
      RECT  3016.32 0.62 3020.58 0.98 ;
      RECT  3022.16 0.62 3026.42 0.98 ;
      RECT  3028.0 0.62 3032.26 0.98 ;
      RECT  3033.84 0.62 3038.1 0.98 ;
      RECT  3039.68 0.62 3043.94 0.98 ;
      RECT  3045.52 0.62 3049.78 0.98 ;
      RECT  3051.36 0.62 3055.62 0.98 ;
      RECT  3057.2 0.62 3061.46 0.98 ;
      RECT  3063.04 0.62 3067.3 0.98 ;
      RECT  3068.88 0.62 3073.14 0.98 ;
      RECT  3074.72 0.62 3078.98 0.98 ;
      RECT  3080.56 0.62 3084.82 0.98 ;
      RECT  3086.4 0.62 3090.66 0.98 ;
      RECT  3092.24 0.62 3096.5 0.98 ;
      RECT  3098.08 0.62 3102.34 0.98 ;
      RECT  3103.92 0.62 3108.18 0.98 ;
      RECT  3109.76 0.62 3114.02 0.98 ;
      RECT  3115.6 0.62 3119.86 0.98 ;
      RECT  3121.44 0.62 3125.7 0.98 ;
      RECT  3127.28 0.62 3131.54 0.98 ;
      RECT  3133.12 0.62 3137.38 0.98 ;
      RECT  3138.96 0.62 3143.22 0.98 ;
      RECT  3144.8 0.62 3149.06 0.98 ;
      RECT  3150.64 0.62 3154.9 0.98 ;
      RECT  3156.48 0.62 3160.74 0.98 ;
      RECT  3162.32 0.62 3166.58 0.98 ;
      RECT  3168.16 0.62 3172.42 0.98 ;
      RECT  3174.0 0.62 3178.26 0.98 ;
      RECT  3179.84 0.62 3184.1 0.98 ;
      RECT  3185.68 0.62 3189.94 0.98 ;
      RECT  3191.52 0.62 3195.78 0.98 ;
      RECT  3197.36 0.62 3201.62 0.98 ;
      RECT  3203.2 0.62 3207.46 0.98 ;
      RECT  3209.04 0.62 3213.3 0.98 ;
      RECT  3214.88 0.62 3219.14 0.98 ;
      RECT  3220.72 0.62 3224.98 0.98 ;
      RECT  3226.56 0.62 3230.82 0.98 ;
      RECT  3232.4 0.62 3236.66 0.98 ;
      RECT  3238.24 0.62 3242.5 0.98 ;
      RECT  3244.08 0.62 3248.34 0.98 ;
      RECT  3249.92 0.62 3254.18 0.98 ;
      RECT  3255.76 0.62 3260.02 0.98 ;
      RECT  3261.6 0.62 3265.86 0.98 ;
      RECT  3267.44 0.62 3271.7 0.98 ;
      RECT  3273.28 0.62 3277.54 0.98 ;
      RECT  3279.12 0.62 3283.38 0.98 ;
      RECT  3284.96 0.62 3289.22 0.98 ;
      RECT  3290.8 0.62 3295.06 0.98 ;
      RECT  3296.64 0.62 3300.9 0.98 ;
      RECT  3302.48 0.62 3306.74 0.98 ;
      RECT  3308.32 0.62 3312.58 0.98 ;
      RECT  3314.16 0.62 3318.42 0.98 ;
      RECT  3320.0 0.62 3324.26 0.98 ;
      RECT  3325.84 0.62 3330.1 0.98 ;
      RECT  3331.68 0.62 3335.94 0.98 ;
      RECT  3337.52 0.62 3341.78 0.98 ;
      RECT  3343.36 0.62 3347.62 0.98 ;
      RECT  3349.2 0.62 3353.46 0.98 ;
      RECT  3355.04 0.62 3359.3 0.98 ;
      RECT  3360.88 0.62 3365.14 0.98 ;
      RECT  3366.72 0.62 3370.98 0.98 ;
      RECT  3372.56 0.62 3376.82 0.98 ;
      RECT  3378.4 0.62 3382.66 0.98 ;
      RECT  3384.24 0.62 3388.5 0.98 ;
      RECT  3390.08 0.62 3394.34 0.98 ;
      RECT  3395.92 0.62 3400.18 0.98 ;
      RECT  3401.76 0.62 3406.02 0.98 ;
      RECT  3407.6 0.62 3411.86 0.98 ;
      RECT  3413.44 0.62 3417.7 0.98 ;
      RECT  3419.28 0.62 3423.54 0.98 ;
      RECT  425.39 0.98 426.97 591.77 ;
      RECT  426.97 0.98 439.3 591.77 ;
      RECT  431.325 591.77 439.3 592.13 ;
      RECT  440.88 0.98 2173.94 591.77 ;
      RECT  2173.94 0.98 2175.52 591.77 ;
      RECT  2177.06 0.62 2179.62 0.98 ;
      RECT  2169.52 0.62 2171.975 0.98 ;
      RECT  2173.555 0.62 2173.78 0.98 ;
      RECT  2175.52 591.77 2571.9 592.13 ;
      RECT  2573.48 591.77 2588.67 592.13 ;
      RECT  440.88 591.77 502.485 592.13 ;
      RECT  504.065 591.77 507.455 592.13 ;
      RECT  510.305 591.77 513.695 592.13 ;
      RECT  516.545 591.77 519.935 592.13 ;
      RECT  522.785 591.77 526.175 592.13 ;
      RECT  529.025 591.77 532.415 592.13 ;
      RECT  535.265 591.77 538.655 592.13 ;
      RECT  541.505 591.77 544.895 592.13 ;
      RECT  547.745 591.77 551.135 592.13 ;
      RECT  553.985 591.77 557.375 592.13 ;
      RECT  560.225 591.77 563.615 592.13 ;
      RECT  566.465 591.77 569.855 592.13 ;
      RECT  572.705 591.77 576.095 592.13 ;
      RECT  578.945 591.77 582.335 592.13 ;
      RECT  585.185 591.77 588.575 592.13 ;
      RECT  591.425 591.77 594.815 592.13 ;
      RECT  597.665 591.77 601.055 592.13 ;
      RECT  603.905 591.77 607.295 592.13 ;
      RECT  610.145 591.77 613.535 592.13 ;
      RECT  616.385 591.77 619.775 592.13 ;
      RECT  622.625 591.77 626.015 592.13 ;
      RECT  628.865 591.77 632.255 592.13 ;
      RECT  635.105 591.77 638.495 592.13 ;
      RECT  641.345 591.77 644.735 592.13 ;
      RECT  647.585 591.77 650.975 592.13 ;
      RECT  653.825 591.77 657.215 592.13 ;
      RECT  660.065 591.77 663.455 592.13 ;
      RECT  666.305 591.77 669.695 592.13 ;
      RECT  672.545 591.77 675.935 592.13 ;
      RECT  678.785 591.77 682.175 592.13 ;
      RECT  685.025 591.77 688.415 592.13 ;
      RECT  691.265 591.77 694.655 592.13 ;
      RECT  697.505 591.77 700.895 592.13 ;
      RECT  703.745 591.77 707.135 592.13 ;
      RECT  709.985 591.77 713.375 592.13 ;
      RECT  716.225 591.77 719.615 592.13 ;
      RECT  722.465 591.77 725.855 592.13 ;
      RECT  728.705 591.77 732.095 592.13 ;
      RECT  734.945 591.77 738.335 592.13 ;
      RECT  741.185 591.77 744.575 592.13 ;
      RECT  747.425 591.77 750.815 592.13 ;
      RECT  753.665 591.77 757.055 592.13 ;
      RECT  759.905 591.77 763.295 592.13 ;
      RECT  766.145 591.77 769.535 592.13 ;
      RECT  772.385 591.77 775.775 592.13 ;
      RECT  778.625 591.77 782.015 592.13 ;
      RECT  784.865 591.77 788.255 592.13 ;
      RECT  791.105 591.77 794.495 592.13 ;
      RECT  797.345 591.77 800.735 592.13 ;
      RECT  803.585 591.77 806.975 592.13 ;
      RECT  809.825 591.77 813.215 592.13 ;
      RECT  816.065 591.77 819.455 592.13 ;
      RECT  822.305 591.77 825.695 592.13 ;
      RECT  828.545 591.77 831.935 592.13 ;
      RECT  834.785 591.77 838.175 592.13 ;
      RECT  841.025 591.77 844.415 592.13 ;
      RECT  847.265 591.77 850.655 592.13 ;
      RECT  853.505 591.77 856.895 592.13 ;
      RECT  859.745 591.77 863.135 592.13 ;
      RECT  865.985 591.77 869.375 592.13 ;
      RECT  872.225 591.77 875.615 592.13 ;
      RECT  878.465 591.77 881.855 592.13 ;
      RECT  884.705 591.77 888.095 592.13 ;
      RECT  890.945 591.77 894.335 592.13 ;
      RECT  897.185 591.77 900.575 592.13 ;
      RECT  903.425 591.77 906.815 592.13 ;
      RECT  909.665 591.77 913.055 592.13 ;
      RECT  915.905 591.77 919.295 592.13 ;
      RECT  922.145 591.77 925.535 592.13 ;
      RECT  928.385 591.77 931.775 592.13 ;
      RECT  934.625 591.77 938.015 592.13 ;
      RECT  940.865 591.77 944.255 592.13 ;
      RECT  947.105 591.77 950.495 592.13 ;
      RECT  953.345 591.77 956.735 592.13 ;
      RECT  959.585 591.77 962.975 592.13 ;
      RECT  965.825 591.77 969.215 592.13 ;
      RECT  972.065 591.77 975.455 592.13 ;
      RECT  978.305 591.77 981.695 592.13 ;
      RECT  984.545 591.77 987.935 592.13 ;
      RECT  990.785 591.77 994.175 592.13 ;
      RECT  997.025 591.77 1000.415 592.13 ;
      RECT  1003.265 591.77 1006.655 592.13 ;
      RECT  1009.505 591.77 1012.895 592.13 ;
      RECT  1015.745 591.77 1019.135 592.13 ;
      RECT  1021.985 591.77 1025.375 592.13 ;
      RECT  1028.225 591.77 1031.615 592.13 ;
      RECT  1034.465 591.77 1037.855 592.13 ;
      RECT  1040.705 591.77 1044.095 592.13 ;
      RECT  1046.945 591.77 1050.335 592.13 ;
      RECT  1053.185 591.77 1056.575 592.13 ;
      RECT  1059.425 591.77 1062.815 592.13 ;
      RECT  1065.665 591.77 1069.055 592.13 ;
      RECT  1071.905 591.77 1075.295 592.13 ;
      RECT  1078.145 591.77 1081.535 592.13 ;
      RECT  1084.385 591.77 1087.775 592.13 ;
      RECT  1090.625 591.77 1094.015 592.13 ;
      RECT  1096.865 591.77 1100.255 592.13 ;
      RECT  1103.105 591.77 1106.495 592.13 ;
      RECT  1109.345 591.77 1112.735 592.13 ;
      RECT  1115.585 591.77 1118.975 592.13 ;
      RECT  1121.825 591.77 1125.215 592.13 ;
      RECT  1128.065 591.77 1131.455 592.13 ;
      RECT  1134.305 591.77 1137.695 592.13 ;
      RECT  1140.545 591.77 1143.935 592.13 ;
      RECT  1146.785 591.77 1150.175 592.13 ;
      RECT  1153.025 591.77 1156.415 592.13 ;
      RECT  1159.265 591.77 1162.655 592.13 ;
      RECT  1165.505 591.77 1168.895 592.13 ;
      RECT  1171.745 591.77 1175.135 592.13 ;
      RECT  1177.985 591.77 1181.375 592.13 ;
      RECT  1184.225 591.77 1187.615 592.13 ;
      RECT  1190.465 591.77 1193.855 592.13 ;
      RECT  1196.705 591.77 1200.095 592.13 ;
      RECT  1202.945 591.77 1206.335 592.13 ;
      RECT  1209.185 591.77 1212.575 592.13 ;
      RECT  1215.425 591.77 1218.815 592.13 ;
      RECT  1221.665 591.77 1225.055 592.13 ;
      RECT  1227.905 591.77 1231.295 592.13 ;
      RECT  1234.145 591.77 1237.535 592.13 ;
      RECT  1240.385 591.77 1243.775 592.13 ;
      RECT  1246.625 591.77 1250.015 592.13 ;
      RECT  1252.865 591.77 1256.255 592.13 ;
      RECT  1259.105 591.77 1262.495 592.13 ;
      RECT  1265.345 591.77 1268.735 592.13 ;
      RECT  1271.585 591.77 1274.975 592.13 ;
      RECT  1277.825 591.77 1281.215 592.13 ;
      RECT  1284.065 591.77 1287.455 592.13 ;
      RECT  1290.305 591.77 1293.695 592.13 ;
      RECT  1296.545 591.77 1299.935 592.13 ;
      RECT  1302.785 591.77 1306.175 592.13 ;
      RECT  1309.025 591.77 1312.415 592.13 ;
      RECT  1315.265 591.77 1318.655 592.13 ;
      RECT  1321.505 591.77 1324.895 592.13 ;
      RECT  1327.745 591.77 1331.135 592.13 ;
      RECT  1333.985 591.77 1337.375 592.13 ;
      RECT  1340.225 591.77 1343.615 592.13 ;
      RECT  1346.465 591.77 1349.855 592.13 ;
      RECT  1352.705 591.77 1356.095 592.13 ;
      RECT  1358.945 591.77 1362.335 592.13 ;
      RECT  1365.185 591.77 1368.575 592.13 ;
      RECT  1371.425 591.77 1374.815 592.13 ;
      RECT  1377.665 591.77 1381.055 592.13 ;
      RECT  1383.905 591.77 1387.295 592.13 ;
      RECT  1390.145 591.77 1393.535 592.13 ;
      RECT  1396.385 591.77 1399.775 592.13 ;
      RECT  1402.625 591.77 1406.015 592.13 ;
      RECT  1408.865 591.77 1412.255 592.13 ;
      RECT  1415.105 591.77 1418.495 592.13 ;
      RECT  1421.345 591.77 1424.735 592.13 ;
      RECT  1427.585 591.77 1430.975 592.13 ;
      RECT  1433.825 591.77 1437.215 592.13 ;
      RECT  1440.065 591.77 1443.455 592.13 ;
      RECT  1446.305 591.77 1449.695 592.13 ;
      RECT  1452.545 591.77 1455.935 592.13 ;
      RECT  1458.785 591.77 1462.175 592.13 ;
      RECT  1465.025 591.77 1468.415 592.13 ;
      RECT  1471.265 591.77 1474.655 592.13 ;
      RECT  1477.505 591.77 1480.895 592.13 ;
      RECT  1483.745 591.77 1487.135 592.13 ;
      RECT  1489.985 591.77 1493.375 592.13 ;
      RECT  1496.225 591.77 1499.615 592.13 ;
      RECT  1502.465 591.77 1505.855 592.13 ;
      RECT  1508.705 591.77 1512.095 592.13 ;
      RECT  1514.945 591.77 1518.335 592.13 ;
      RECT  1521.185 591.77 1524.575 592.13 ;
      RECT  1527.425 591.77 1530.815 592.13 ;
      RECT  1533.665 591.77 1537.055 592.13 ;
      RECT  1539.905 591.77 1543.295 592.13 ;
      RECT  1546.145 591.77 1549.535 592.13 ;
      RECT  1552.385 591.77 1555.775 592.13 ;
      RECT  1558.625 591.77 1562.015 592.13 ;
      RECT  1564.865 591.77 1568.255 592.13 ;
      RECT  1571.105 591.77 1574.495 592.13 ;
      RECT  1577.345 591.77 1580.735 592.13 ;
      RECT  1583.585 591.77 1586.975 592.13 ;
      RECT  1589.825 591.77 1593.215 592.13 ;
      RECT  1596.065 591.77 1599.455 592.13 ;
      RECT  1602.305 591.77 1605.695 592.13 ;
      RECT  1608.545 591.77 1611.935 592.13 ;
      RECT  1614.785 591.77 1618.175 592.13 ;
      RECT  1621.025 591.77 1624.415 592.13 ;
      RECT  1627.265 591.77 1630.655 592.13 ;
      RECT  1633.505 591.77 1636.895 592.13 ;
      RECT  1639.745 591.77 1643.135 592.13 ;
      RECT  1645.985 591.77 1649.375 592.13 ;
      RECT  1652.225 591.77 1655.615 592.13 ;
      RECT  1658.465 591.77 1661.855 592.13 ;
      RECT  1664.705 591.77 1668.095 592.13 ;
      RECT  1670.945 591.77 1674.335 592.13 ;
      RECT  1677.185 591.77 1680.575 592.13 ;
      RECT  1683.425 591.77 1686.815 592.13 ;
      RECT  1689.665 591.77 1693.055 592.13 ;
      RECT  1695.905 591.77 1699.295 592.13 ;
      RECT  1702.145 591.77 1705.535 592.13 ;
      RECT  1708.385 591.77 1711.775 592.13 ;
      RECT  1714.625 591.77 1718.015 592.13 ;
      RECT  1720.865 591.77 1724.255 592.13 ;
      RECT  1727.105 591.77 1730.495 592.13 ;
      RECT  1733.345 591.77 1736.735 592.13 ;
      RECT  1739.585 591.77 1742.975 592.13 ;
      RECT  1745.825 591.77 1749.215 592.13 ;
      RECT  1752.065 591.77 1755.455 592.13 ;
      RECT  1758.305 591.77 1761.695 592.13 ;
      RECT  1764.545 591.77 1767.935 592.13 ;
      RECT  1770.785 591.77 1774.175 592.13 ;
      RECT  1777.025 591.77 1780.415 592.13 ;
      RECT  1783.265 591.77 1786.655 592.13 ;
      RECT  1789.505 591.77 1792.895 592.13 ;
      RECT  1795.745 591.77 1799.135 592.13 ;
      RECT  1801.985 591.77 1805.375 592.13 ;
      RECT  1808.225 591.77 1811.615 592.13 ;
      RECT  1814.465 591.77 1817.855 592.13 ;
      RECT  1820.705 591.77 1824.095 592.13 ;
      RECT  1826.945 591.77 1830.335 592.13 ;
      RECT  1833.185 591.77 1836.575 592.13 ;
      RECT  1839.425 591.77 1842.815 592.13 ;
      RECT  1845.665 591.77 1849.055 592.13 ;
      RECT  1851.905 591.77 1855.295 592.13 ;
      RECT  1858.145 591.77 1861.535 592.13 ;
      RECT  1864.385 591.77 1867.775 592.13 ;
      RECT  1870.625 591.77 1874.015 592.13 ;
      RECT  1876.865 591.77 1880.255 592.13 ;
      RECT  1883.105 591.77 1886.495 592.13 ;
      RECT  1889.345 591.77 1892.735 592.13 ;
      RECT  1895.585 591.77 1898.975 592.13 ;
      RECT  1901.825 591.77 1905.215 592.13 ;
      RECT  1908.065 591.77 1911.455 592.13 ;
      RECT  1914.305 591.77 1917.695 592.13 ;
      RECT  1920.545 591.77 1923.935 592.13 ;
      RECT  1926.785 591.77 1930.175 592.13 ;
      RECT  1933.025 591.77 1936.415 592.13 ;
      RECT  1939.265 591.77 1942.655 592.13 ;
      RECT  1945.505 591.77 1948.895 592.13 ;
      RECT  1951.745 591.77 1955.135 592.13 ;
      RECT  1957.985 591.77 1961.375 592.13 ;
      RECT  1964.225 591.77 1967.615 592.13 ;
      RECT  1970.465 591.77 1973.855 592.13 ;
      RECT  1976.705 591.77 1980.095 592.13 ;
      RECT  1982.945 591.77 1986.335 592.13 ;
      RECT  1989.185 591.77 1992.575 592.13 ;
      RECT  1995.425 591.77 1998.815 592.13 ;
      RECT  2001.665 591.77 2005.055 592.13 ;
      RECT  2007.905 591.77 2011.295 592.13 ;
      RECT  2014.145 591.77 2017.535 592.13 ;
      RECT  2020.385 591.77 2023.775 592.13 ;
      RECT  2026.625 591.77 2030.015 592.13 ;
      RECT  2032.865 591.77 2036.255 592.13 ;
      RECT  2039.105 591.77 2042.495 592.13 ;
      RECT  2045.345 591.77 2048.735 592.13 ;
      RECT  2051.585 591.77 2054.975 592.13 ;
      RECT  2057.825 591.77 2061.215 592.13 ;
      RECT  2064.065 591.77 2067.455 592.13 ;
      RECT  2070.305 591.77 2073.695 592.13 ;
      RECT  2076.545 591.77 2079.935 592.13 ;
      RECT  2082.785 591.77 2086.175 592.13 ;
      RECT  2089.025 591.77 2092.415 592.13 ;
      RECT  2095.265 591.77 2098.655 592.13 ;
      RECT  2100.235 591.77 2172.505 592.13 ;
      RECT  2.34 0.62 439.3 0.98 ;
      RECT  2.34 591.77 425.39 592.13 ;
      RECT  3425.12 0.62 3439.22 0.98 ;
      RECT  2590.25 591.77 3439.22 592.13 ;
      RECT  2.34 0.98 2.88 2.88 ;
      RECT  2.34 2.88 2.88 589.87 ;
      RECT  2.34 589.87 2.88 591.77 ;
      RECT  2.88 0.98 5.82 2.88 ;
      RECT  2.88 589.87 5.82 591.77 ;
      RECT  5.82 0.98 425.39 2.88 ;
      RECT  5.82 2.88 425.39 589.87 ;
      RECT  5.82 589.87 425.39 591.77 ;
      RECT  2175.52 0.98 3435.74 2.88 ;
      RECT  2175.52 2.88 3435.74 589.87 ;
      RECT  2175.52 589.87 3435.74 591.77 ;
      RECT  3435.74 0.98 3438.68 2.88 ;
      RECT  3435.74 589.87 3438.68 591.77 ;
      RECT  3438.68 0.98 3439.22 2.88 ;
      RECT  3438.68 2.88 3439.22 589.87 ;
      RECT  3438.68 589.87 3439.22 591.77 ;
   END
END    sky130_sram_512x64
END    LIBRARY
